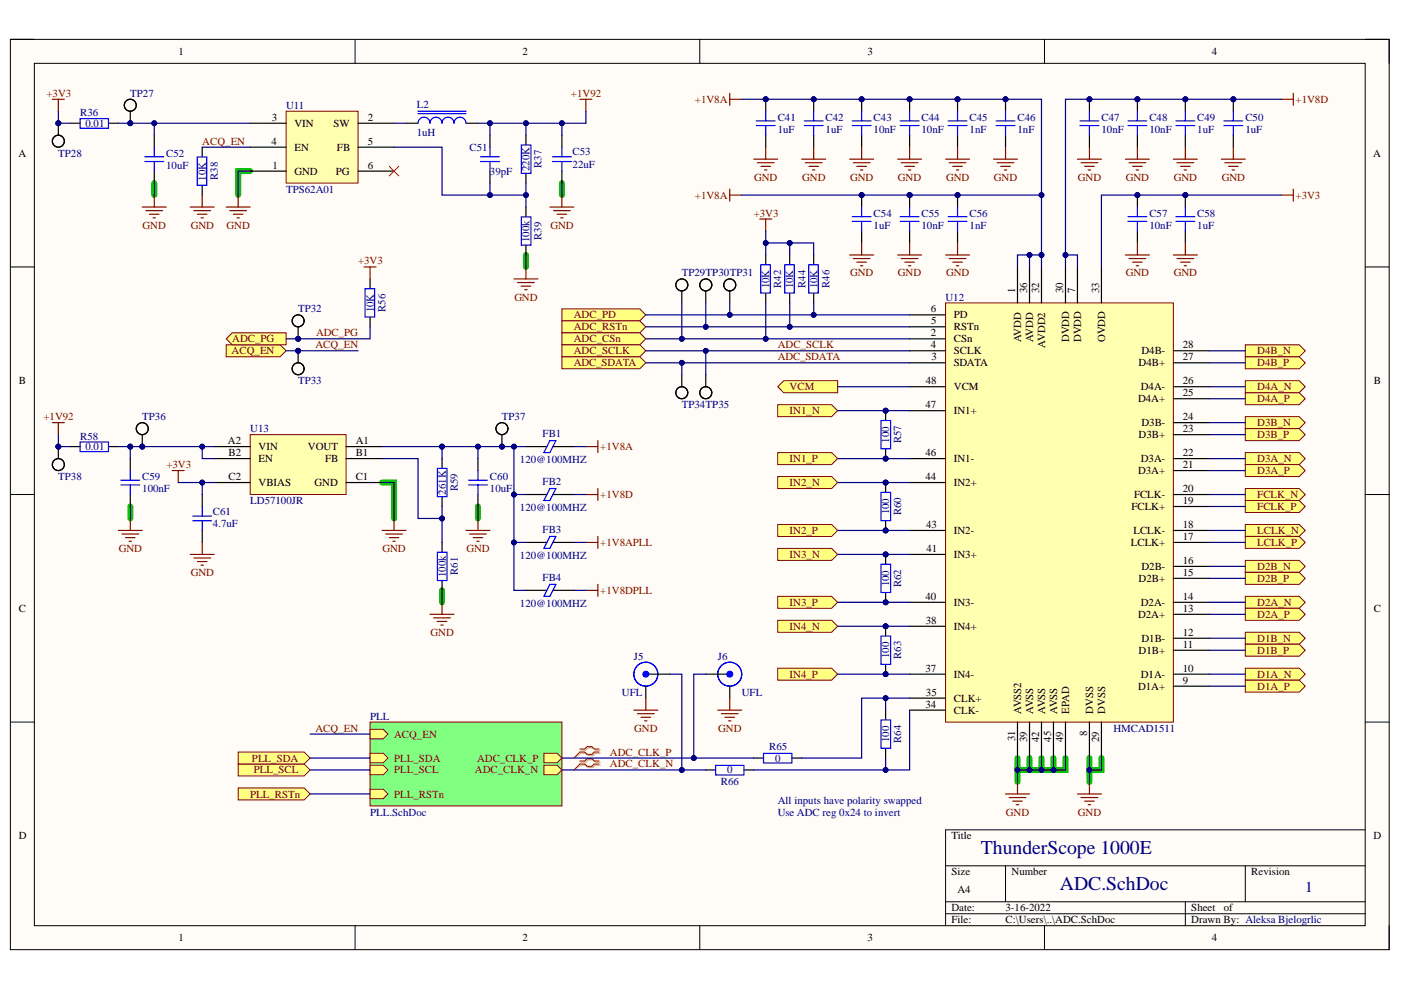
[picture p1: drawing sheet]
<svg xmlns="http://www.w3.org/2000/svg" width="297mm" height="210mm" viewBox="0 0 297 210" stroke-linecap="round" stroke-linejoin="round" font-family="sans-serif">
<defs><g id="words">
<g font-size="4.1" fill="#000080">
<text x="208" y="181.2">ThunderScope 1000E</text>
<text x="224.7" y="188.8">ADC.SchDoc</text>
</g>
<text font-size="3.2" fill="#000080" x="276.7" y="189.2">1</text>
<g font-size="2.3">
<text x="37.9" y="11.7">1</text>
<text x="110.8" y="11.7">2</text>
<text x="184" y="11.7">3</text>
<text x="256.9" y="11.7">4</text>
<text x="57.7" y="25.6">3</text>
<text x="62.4" y="26.9">VIN</text>
<text x="70.7" y="26.9">SW</text>
<text x="78" y="25.6">2</text>
<text x="3.9" y="33.2">A</text>
<text x="57.6" y="30.7">4</text>
<text x="57.8" y="35.8">1</text>
<text x="62.4" y="31.9">EN</text>
<text x="71.4" y="31.9">FB</text>
<text x="78" y="30.7">5</text>
<text x="78" y="35.8">6</text>
<text x="291.1" y="33.2">A</text>
<text x="62.4" y="37.1">GND</text>
<text x="71.2" y="37.1">PG</text>
<text x="215.2" y="62.2" transform="rotate(-90 215.2 62.2)">1</text>
<text x="217.8" y="62.2" transform="rotate(-90 217.8 62.2)">36</text>
<text x="220.3" y="62.2" transform="rotate(-90 220.3 62.2)">32</text>
<text x="225.4" y="62.2" transform="rotate(-90 225.4 62.2)">30</text>
<text x="228" y="62.2" transform="rotate(-90 228 62.2)">7</text>
<text x="233" y="62.2" transform="rotate(-90 233 62.2)">33</text>
<text x="197.4" y="66.3">6</text>
<text x="197.4" y="71.3">2</text>
<text x="197.5" y="68.8">5</text>
<text x="202.2" y="67.5">PD</text>
<text x="202.2" y="70.1">RSTn</text>
<text x="197.4" y="73.9">4</text>
<text x="197.5" y="76.4">3</text>
<text x="202.2" y="72.6">CSn</text>
<text x="202.2" y="75.1">SCLK</text>
<text x="202.2" y="77.7">SDATA</text>
<text x="216.5" y="72.5" transform="rotate(-90 216.5 72.5)">AVDD</text>
<text x="219" y="72.5" transform="rotate(-90 219 72.5)">AVDD</text>
<text x="221.6" y="73.7" transform="rotate(-90 221.6 73.7)">AVDD2</text>
<text x="226.7" y="72.5" transform="rotate(-90 226.7 72.5)">DVDD</text>
<text x="229.2" y="72.5" transform="rotate(-90 229.2 72.5)">DVDD</text>
<text x="234.3" y="72.5" transform="rotate(-90 234.3 72.5)">OVDD</text>
<text x="241.4" y="77.7">D4B+</text>
<text x="242" y="75.1">D4B-</text>
<text x="250.8" y="76.4">27</text>
<text x="250.8" y="73.9">28</text>
<text x="4" y="81.5">B</text>
<text x="196.3" y="81.5">48</text>
<text x="202.2" y="82.7">VCM</text>
<text x="241.9" y="82.7">D4A-</text>
<text x="250.8" y="81.5">26</text>
<text x="291.3" y="81.5">B</text>
<text x="196.2" y="86.5">47</text>
<text x="202.2" y="87.8">IN1+</text>
<text x="241.3" y="85.3">D4A+</text>
<text x="250.8" y="89.1">24</text>
<text x="250.8" y="84">25</text>
<text x="48.3" y="94.2">A2</text>
<text x="54.8" y="95.5">VIN</text>
<text x="65.3" y="95.5">VOUT</text>
<text x="75.4" y="94.2">A1</text>
<text x="241.4" y="92.9">D3B+</text>
<text x="242" y="90.4">D3B-</text>
<text x="250.8" y="91.6">23</text>
<text x="48.4" y="96.7">B2</text>
<text x="48.4" y="101.8">C2</text>
<text x="54.8" y="98">EN</text>
<text x="68.9" y="98">FB</text>
<text x="75.4" y="96.7">B1</text>
<text x="75.4" y="101.8">C1</text>
<text x="196.2" y="96.7">46</text>
<text x="196.2" y="101.8">44</text>
<text x="202.2" y="98">IN1-</text>
<text x="241.3" y="100.5">D3A+</text>
<text x="241.9" y="98">D3A-</text>
<text x="250.8" y="99.3">21</text>
<text x="250.8" y="96.7">22</text>
<text x="54.8" y="103.1">VBIAS</text>
<text x="66.7" y="103.1">GND</text>
<text x="202.2" y="103.1">IN2+</text>
<text x="240.4" y="105.6">FCLK-</text>
<text x="250.8" y="106.9">19</text>
<text x="250.8" y="104.3">20</text>
<text x="196.4" y="111.9">43</text>
<text x="202.2" y="113.2">IN2-</text>
<text x="239.9" y="108.1">FCLK+</text>
<text x="240.3" y="113.2">LCLK-</text>
<text x="250.8" y="111.9">18</text>
<text x="196.4" y="117">41</text>
<text x="202.2" y="118.3">IN3+</text>
<text x="239.8" y="115.8">LCLK+</text>
<text x="250.8" y="119.6">16</text>
<text x="250.8" y="114.5">17</text>
<text x="241.4" y="123.4">D2B+</text>
<text x="242" y="120.8">D2B-</text>
<text x="250.8" y="122.1">15</text>
<text x="4" y="129.7">C</text>
<text x="196.2" y="127.2">40</text>
<text x="202.2" y="128.5">IN3-</text>
<text x="241.3" y="131">D2A+</text>
<text x="241.9" y="128.5">D2A-</text>
<text x="250.8" y="129.7">13</text>
<text x="250.8" y="127.2">14</text>
<text x="291.3" y="129.7">C</text>
<text x="196.3" y="132.3">38</text>
<text x="202.2" y="133.5">IN4+</text>
<text x="242" y="136.1">D1B-</text>
<text x="250.8" y="137.3">11</text>
<text x="250.8" y="134.8">12</text>
<text x="196.2" y="142.4">37</text>
<text x="202.2" y="143.7">IN4-</text>
<text x="241.4" y="138.6">D1B+</text>
<text x="241.9" y="143.7">D1A-</text>
<text x="250.8" y="142.4">10</text>
<text x="196.3" y="147.5">35</text>
<text x="202.2" y="148.8">CLK+</text>
<text x="241.3" y="146.2">D1A+</text>
<text x="250.8" y="145">9</text>
<text x="196.2" y="150">34</text>
<text x="202.2" y="151.3">CLK-</text>
<text x="216.5" y="151.3" transform="rotate(-90 216.5 151.3)">AVSS2</text>
<text x="219" y="151.3" transform="rotate(-90 219 151.3)">AVSS</text>
<text x="221.6" y="151.3" transform="rotate(-90 221.6 151.3)">AVSS</text>
<text x="224.1" y="151.3" transform="rotate(-90 224.1 151.3)">AVSS</text>
<text x="226.7" y="151.3" transform="rotate(-90 226.7 151.3)">EPAD</text>
<text x="231.8" y="151.3" transform="rotate(-90 231.8 151.3)">DVSS</text>
<text x="234.3" y="151.3" transform="rotate(-90 234.3 151.3)">DVSS</text>
<text x="215.2" y="157.1" transform="rotate(-90 215.2 157.1)">31</text>
<text x="217.8" y="157.3" transform="rotate(-90 217.8 157.3)">39</text>
<text x="220.3" y="157.3" transform="rotate(-90 220.3 157.3)">42</text>
<text x="222.8" y="157.3" transform="rotate(-90 222.8 157.3)">45</text>
<text x="225.4" y="157.3" transform="rotate(-90 225.4 157.3)">49</text>
<text x="230.5" y="156.1" transform="rotate(-90 230.5 156.1)">8</text>
<text x="233" y="157.3" transform="rotate(-90 233 157.3)">29</text>
<text x="4" y="178">D</text>
<text x="201.7" y="178">Title</text>
<text x="291.2" y="178">D</text>
<text x="201.7" y="185.6">Size</text>
<text x="214.5" y="185.6">Number</text>
<text x="265.3" y="185.6">Revision</text>
<text x="203" y="189.4">A4</text>
<text x="201.7" y="193.2">Date:</text>
<text x="201.7" y="195.7">File:</text>
<text x="213.2" y="193.2">3-16-2022</text>
<text x="213.2" y="195.7">C:\Users\..\ADC.SchDoc</text>
<text x="252.6" y="193.2">Sheet</text>
<text x="252.6" y="195.7">Drawn By: Aleksa Bjelogrlic</text>
<text x="259.5" y="193.2">of</text>
<text x="37.9" y="199.6">1</text>
<text x="110.8" y="199.6">2</text>
<text x="184" y="199.6">3</text>
<text x="256.9" y="199.6">4</text>
</g>
<g font-size="2.3" fill="#800000">
<text x="9.9" y="20.5">+3V3</text>
<text x="121.1" y="20.5">+1V92</text>
<text x="147.3" y="21.8">+1V8A</text>
<text x="274.7" y="21.8">+1V8D</text>
<text x="42.9" y="30.7">ACQ_EN</text>
<text x="159.9" y="38.3">GND</text>
<text x="170.1" y="38.3">GND</text>
<text x="180.2" y="38.3">GND</text>
<text x="190.4" y="38.3">GND</text>
<text x="200.6" y="38.3">GND</text>
<text x="210.7" y="38.3">GND</text>
<text x="228.5" y="38.3">GND</text>
<text x="238.7" y="38.3">GND</text>
<text x="248.8" y="38.3">GND</text>
<text x="259" y="38.3">GND</text>
<text x="147.3" y="42.1">+1V8A</text>
<text x="159.8" y="45.9">+3V3</text>
<text x="274.7" y="42.1">+3V3</text>
<text x="30.2" y="48.5">GND</text>
<text x="40.4" y="48.5">GND</text>
<text x="48.1" y="48.5">GND</text>
<text x="116.7" y="48.5">GND</text>
<text x="75.9" y="56.1">+3V3</text>
<text x="180.2" y="58.6">GND</text>
<text x="190.4" y="58.6">GND</text>
<text x="200.6" y="58.6">GND</text>
<text x="238.7" y="58.6">GND</text>
<text x="248.8" y="58.6">GND</text>
<text x="109" y="63.7">GND</text>
<text x="67" y="71.3">ADC_PG</text>
<text x="121.7" y="67.5">ADC_PD</text>
<text x="121.7" y="70.1">ADC_RSTn</text>
<text x="49.1" y="75.1">ACQ_EN</text>
<text x="49.2" y="72.6">ADC_PG</text>
<text x="66.9" y="73.9">ACQ_EN</text>
<text x="121.7" y="72.6">ADC_CSn</text>
<text x="121.7" y="75.1">ADC_SCLK</text>
<text x="121.7" y="77.7">ADC_SDATA</text>
<text x="164.9" y="73.9">ADC_SCLK</text>
<text x="164.9" y="76.4">ADC_SDATA</text>
<text x="266.6" y="75.1">D4B_N</text>
<text x="266.6" y="77.7">D4B_P</text>
<text x="167.4" y="82.7">VCM</text>
<text x="266.6" y="82.7">D4A_N</text>
<text x="9.2" y="89.1">+1V92</text>
<text x="167.4" y="87.8">IN1_N</text>
<text x="266.6" y="85.3">D4A_P</text>
<text x="127.3" y="95.5">+1V8A</text>
<text x="266.6" y="90.4">D3B_N</text>
<text x="266.6" y="92.9">D3B_P</text>
<text x="35.3" y="99.3">+3V3</text>
<text x="167.4" y="98">IN1_P</text>
<text x="266.6" y="98">D3A_N</text>
<text x="266.6" y="100.5">D3A_P</text>
<text x="127.3" y="105.6">+1V8D</text>
<text x="167.4" y="103.1">IN2_N</text>
<text x="266.6" y="105.6">FCLK_N</text>
<text x="167.4" y="113.2">IN2_P</text>
<text x="266.6" y="108.1">FCLK_P</text>
<text x="266.6" y="113.2">LCLK_N</text>
<text x="25.2" y="117">GND</text>
<text x="81.1" y="117">GND</text>
<text x="98.9" y="117">GND</text>
<text x="127.3" y="115.8">+1V8APLL</text>
<text x="167.4" y="118.3">IN3_N</text>
<text x="266.6" y="115.8">LCLK_P</text>
<text x="40.4" y="122.1">GND</text>
<text x="127.3" y="125.9">+1V8DPLL</text>
<text x="266.6" y="120.8">D2B_N</text>
<text x="266.6" y="123.4">D2B_P</text>
<text x="167.4" y="128.5">IN3_P</text>
<text x="266.6" y="128.5">D2A_N</text>
<text x="266.6" y="131">D2A_P</text>
<text x="91.3" y="134.8">GND</text>
<text x="167.4" y="133.5">IN4_N</text>
<text x="266.6" y="136.1">D1B_N</text>
<text x="167.4" y="143.7">IN4_P</text>
<text x="266.6" y="138.6">D1B_P</text>
<text x="266.6" y="143.7">D1A_N</text>
<text x="266.6" y="146.2">D1A_P</text>
<text x="66.9" y="155.1">ACQ_EN</text>
<text x="134.5" y="155.1">GND</text>
<text x="152.3" y="155.1">GND</text>
<text x="53.4" y="161.5">PLL_SDA</text>
<text x="83.5" y="161.5">PLL_SDA</text>
<text x="83.5" y="156.4">ACQ_EN</text>
<text x="101.1" y="161.5">ADC_CLK_P</text>
<text x="129.3" y="160.2">ADC_CLK_P</text>
<text x="53.8" y="164">PLL_SCL</text>
<text x="83.5" y="164">PLL_SCL</text>
<text x="100.7" y="164">ADC_CLK_N</text>
<text x="129.3" y="162.7">ADC_CLK_N</text>
<text x="53" y="169.1">PLL_RSTn</text>
<text x="83.5" y="169.1">PLL_RSTn</text>
<text x="213.3" y="172.9">GND</text>
<text x="228.5" y="172.9">GND</text>
</g>
<g font-size="2.3" fill="#000080">
<text x="27.6" y="20.5">TP27</text>
<text x="60.7" y="23.1">U11</text>
<text x="88.4" y="22.8">L2</text>
<text x="17" y="24.6">R36</text>
<text x="18.1" y="26.9">0.01</text>
<text x="88.4" y="28.9">1uH</text>
<text x="164.9" y="25.6">C41</text>
<text x="164.9" y="28.1">1uF</text>
<text x="175" y="25.6">C42</text>
<text x="175" y="28.1">1uF</text>
<text x="185.2" y="25.6">C43</text>
<text x="185.2" y="28.1">10nF</text>
<text x="195.4" y="25.6">C44</text>
<text x="195.4" y="28.1">10nF</text>
<text x="205.6" y="25.6">C45</text>
<text x="205.6" y="28.1">1nF</text>
<text x="215.7" y="25.6">C46</text>
<text x="215.7" y="28.1">1nF</text>
<text x="233.5" y="25.6">C47</text>
<text x="233.5" y="28.1">10nF</text>
<text x="243.7" y="25.6">C48</text>
<text x="243.7" y="28.1">10nF</text>
<text x="253.8" y="25.6">C49</text>
<text x="253.8" y="28.1">1uF</text>
<text x="264" y="25.6">C50</text>
<text x="264" y="28.1">1uF</text>
<text x="12.4" y="33.2">TP28</text>
<text x="35.2" y="33.2">C52</text>
<text x="35.2" y="35.8">10uF</text>
<text x="99.6" y="31.9">C51</text>
<text x="114.8" y="35.6" transform="rotate(-90 114.8 35.6)">R37</text>
<text x="121.4" y="33">C53</text>
<text x="121.4" y="35.5">22uF</text>
<text x="43.7" y="38.3" transform="rotate(-90 43.7 38.3)">10K</text>
<text x="46.2" y="38.1" transform="rotate(-90 46.2 38.1)">R38</text>
<text x="60.7" y="40.9">TPS62A01</text>
<text x="103.9" y="37.1">39pF</text>
<text x="112.3" y="36.3" transform="rotate(-90 112.3 36.3)">220K</text>
<text x="185.2" y="45.9">C54</text>
<text x="195.4" y="45.9">C55</text>
<text x="205.6" y="45.9">C56</text>
<text x="243.7" y="45.9">C57</text>
<text x="253.8" y="45.9">C58</text>
<text x="112.3" y="51.3" transform="rotate(-90 112.3 51.3)">100k</text>
<text x="114.8" y="50.8" transform="rotate(-90 114.8 50.8)">R39</text>
<text x="185.2" y="48.5">1uF</text>
<text x="195.4" y="48.5">10nF</text>
<text x="205.6" y="48.5">1nF</text>
<text x="243.7" y="48.5">10nF</text>
<text x="253.8" y="48.5">1uF</text>
<text x="144.5" y="58.6">TP29TP30TP31</text>
<text x="163.1" y="61.1" transform="rotate(-90 163.1 61.1)">10K</text>
<text x="165.6" y="61" transform="rotate(-90 165.6 61)">R42</text>
<text x="168.2" y="61.1" transform="rotate(-90 168.2 61.1)">10K</text>
<text x="170.8" y="61" transform="rotate(-90 170.8 61)">R44</text>
<text x="173.3" y="61.1" transform="rotate(-90 173.3 61.1)">10K</text>
<text x="175.8" y="61" transform="rotate(-90 175.8 61)">R46</text>
<text x="200.5" y="63.7">U12</text>
<text x="63.2" y="66.3">TP32</text>
<text x="79.2" y="66.2" transform="rotate(-90 79.2 66.2)">10K</text>
<text x="81.8" y="66.1" transform="rotate(-90 81.8 66.1)">R56</text>
<text x="63.2" y="81.5">TP33</text>
<text x="30.2" y="89.1">TP36</text>
<text x="106.4" y="89.1">TP37</text>
<text x="144.5" y="86.5">TP34TP35</text>
<text x="17" y="93.2">R58</text>
<text x="18.1" y="95.5">0.01</text>
<text x="53" y="91.6">U13</text>
<text x="115.1" y="92.7">FB1</text>
<text x="188.5" y="93.8" transform="rotate(-90 188.5 93.8)">100</text>
<text x="191.1" y="94" transform="rotate(-90 191.1 94)">R57</text>
<text x="12.4" y="101.8">TP38</text>
<text x="30.2" y="101.8">C59</text>
<text x="103.9" y="101.8">C60</text>
<text x="110.2" y="98.2">120@100MHZ</text>
<text x="30.2" y="104.3">100nF</text>
<text x="53" y="106.9">LD57100JR</text>
<text x="94.5" y="104.9" transform="rotate(-90 94.5 104.9)">261K</text>
<text x="97" y="104.2" transform="rotate(-90 97 104.2)">R59</text>
<text x="103.9" y="104.3">10uF</text>
<text x="115.1" y="102.8">FB2</text>
<text x="45.1" y="109.1">C61</text>
<text x="45.1" y="111.7">4.7uF</text>
<text x="110.2" y="108.4">120@100MHZ</text>
<text x="115.1" y="112.9">FB3</text>
<text x="188.5" y="109.1" transform="rotate(-90 188.5 109.1)">100</text>
<text x="191.1" y="109.3" transform="rotate(-90 191.1 109.3)">R60</text>
<text x="110.2" y="118.6">120@100MHZ</text>
<text x="94.5" y="122.4" transform="rotate(-90 94.5 122.4)">100k</text>
<text x="97" y="121.9" transform="rotate(-90 97 121.9)">R61</text>
<text x="115.1" y="123.1">FB4</text>
<text x="188.5" y="124.3" transform="rotate(-90 188.5 124.3)">100</text>
<text x="191.1" y="124.5" transform="rotate(-90 191.1 124.5)">R62</text>
<text x="110.2" y="128.7">120@100MHZ</text>
<text x="134.4" y="139.9">J5</text>
<text x="152.2" y="139.9">J6</text>
<text x="188.5" y="139.5" transform="rotate(-90 188.5 139.5)">100</text>
<text x="191.1" y="139.7" transform="rotate(-90 191.1 139.7)">R63</text>
<text x="131.8" y="147.5">UFL</text>
<text x="157.3" y="147.5">UFL</text>
<text x="78.5" y="152.6">PLL</text>
<text x="236.1" y="155.1">HMCAD1511</text>
<text x="163.1" y="158.9">R65</text>
<text x="164.3" y="161.5">0</text>
<text x="188.5" y="157.3" transform="rotate(-90 188.5 157.3)">100</text>
<text x="191.1" y="157.5" transform="rotate(-90 191.1 157.5)">R64</text>
<text x="152.8" y="166.5">R66</text>
<text x="154.2" y="164">0</text>
<text x="78.5" y="172.9">PLL.SchDoc</text>
<text x="164.9" y="170.4">All inputs have polarity swapped</text>
<text x="164.9" y="172.9">Use ADC reg 0x24 to invert</text>
</g>
</g></defs>
<path d="M2.2 8.3h292.3v193.1h-292.3z" fill-rule="evenodd" fill="#fffcf8"/>
<path d="M2.2 8.3h292.3v193.1h-292.3z" fill="none" stroke="#000" stroke-width=".21"/>
<path d="M7.3 13.4h282.1v182.9h-282.1z" fill-rule="evenodd" fill="#fffcf8"/>
<g fill="none" stroke="#000" stroke-width=".21">
<path d="M2.2 8.3h5.1M7.3 13.4h282.1v182.9h-282.1zM75.3 8.3v5.1M148.4 8.3v5.1M221.5 8.3v5.1M289.4 8.3h5.1v5.1M2.2 56.6h5.1M289.4 56.6h5.1M2.2 104.8h5.1M289.4 104.9h5.1M2.2 153.1h5.1M289.4 153.1h5.1"/>
<path d="M289.4 176h-88.9v20.3M75.3 196.3v5.1M148.4 196.3v5.1M200.5 183.6h88.9M200.5 191.2h88.9M200.5 193.7h88.9M213.2 183.6v7.6M221.5 196.3v5.1M251.3 191.2v5.1M264 183.6v7.6M294.5 196.3v5.1"/>
</g>
<g fill="none" stroke="#00be00" stroke-width="1.3">
<path d="M32.7 38.8v2.6M53 36.3h-2.5v5.1M119.1 38.8v2.6M111.5 54.1v2.5M27.6 107.4v2.5M81 102.3h2.5v7.6M101.3 107.4v2.5M93.7 125.2v2.5M215.7 160.7v2.6M218.3 160.7v2.6M220.8 163.3h-5.1v2.5M220.8 160.7v2.6"/>
<path d="M223.4 160.7v2.6M225.9 160.7v2.6h-5.1M231 160.7v2.6h2.5v-2.6M231 163.3v2.5"/>
</g>
<path d="M93.7 97.2v2M101.3 97.2v2.6M93.7 105.4v2M93.7 115v2M101.3 104.8v2.6M93.7 123.2v2" fill="none" stroke="#000" stroke-width=".25"/>
<path d="M92.7 99.3h2.1v6h-2.1zM101.3 99.8v2M92.7 117.1h2.1v6h-2.1zM99.3 102.8h4M99.3 101.8h4M101.3 102.8v2" fill="none" stroke="#00f" stroke-width=".25"/>
<path d="M98.8 112.5h5.1M99.6 113.2h3.5M100.3 114h2.1M101.1 114.8h.5M101.3 109.9v2.6M91.2 130.2h5.1M91.9 131h3.6M92.7 131.8h2M93.5 132.5h.5M93.7 127.7v2.5" fill="none" stroke="#800000" stroke-width=".25"/>
<circle cx="241.2" cy="41.4" r=".51" fill="#000080"/>
<circle cx="241.2" cy="41.4" r=".51" fill="none" stroke="#000080" stroke-width=".21"/>
<path d="M241.2 41.4v2.5M241.2 49v2.5" fill="none" stroke="#000" stroke-width=".25"/>
<circle cx="241.2" cy="41.4" r=".51" fill="#000080"/>
<circle cx="241.2" cy="41.4" r=".51" fill="none" stroke="#000080" stroke-width=".21"/>
<path d="M239.2 46.9h3.9M239.2 45.9h3.9M241.2 43.9v2M241.2 46.9v2.1" fill="none" stroke="#00f" stroke-width=".25"/>
<circle cx="251.3" cy="41.4" r=".51" fill="#000080"/>
<circle cx="251.3" cy="41.4" r=".51" fill="none" stroke="#000080" stroke-width=".21"/>
<path d="M251.3 41.4v2.5M251.3 49v2.5" fill="none" stroke="#000" stroke-width=".25"/>
<circle cx="251.3" cy="41.4" r=".51" fill="#000080"/>
<circle cx="251.3" cy="41.4" r=".51" fill="none" stroke="#000080" stroke-width=".21"/>
<path d="M249.3 46.9h4M249.3 45.9h4M251.3 43.9v2M251.3 46.9v2.1" fill="none" stroke="#00f" stroke-width=".25"/>
<path d="M238.6 54.1h5.1M239.4 54.8h3.5M240.1 55.6h2.1M240.9 56.4h.5M241.2 51.5v2.6M248.8 54.1h5.1M249.5 54.8h3.6M250.3 55.6h2M251.1 56.4h.5M251.3 51.5v2.6M271.6 41.4h2.6M274.2 40.1v2.5" fill="none" stroke="#800000" stroke-width=".25"/>
<circle cx="231" cy="21" r=".51" fill="#000080"/>
<circle cx="231" cy="21" r=".51" fill="none" stroke="#000080" stroke-width=".21"/>
<path d="M231 21v2.6M231 28.7v2.5" fill="none" stroke="#000" stroke-width=".25"/>
<circle cx="231" cy="21" r=".51" fill="#000080"/>
<circle cx="231" cy="21" r=".51" fill="none" stroke="#000080" stroke-width=".21"/>
<path d="M229 26.6h4M229 25.6h4M231 23.6v2M231 26.6v2.1" fill="none" stroke="#00f" stroke-width=".25"/>
<circle cx="261.5" cy="21" r=".51" fill="#000080"/>
<circle cx="261.5" cy="21" r=".51" fill="none" stroke="#000080" stroke-width=".21"/>
<path d="M261.5 21v2.6M261.5 28.7v2.5" fill="none" stroke="#000" stroke-width=".25"/>
<circle cx="261.5" cy="21" r=".51" fill="#000080"/>
<circle cx="261.5" cy="21" r=".51" fill="none" stroke="#000080" stroke-width=".21"/>
<path d="M259.5 26.6h4M259.5 25.6h4M261.5 23.6v2M261.5 26.6v2.1" fill="none" stroke="#00f" stroke-width=".25"/>
<path d="M228.4 33.7h5.1M229.2 34.5h3.6M230 35.3h2M230.7 36h.5M231 31.2v2.5M258.9 33.7h5.1M259.7 34.5h3.6M260.5 35.3h2M261.2 36h.5M261.5 31.2v2.5" fill="none" stroke="#800000" stroke-width=".25"/>
<circle cx="241.2" cy="21" r=".51" fill="#000080"/>
<circle cx="241.2" cy="21" r=".51" fill="none" stroke="#000080" stroke-width=".21"/>
<path d="M241.2 21v2.6M241.2 28.7v2.5" fill="none" stroke="#000" stroke-width=".25"/>
<circle cx="241.2" cy="21" r=".51" fill="#000080"/>
<circle cx="241.2" cy="21" r=".51" fill="none" stroke="#000080" stroke-width=".21"/>
<path d="M239.2 26.6h3.9M239.2 25.6h3.9M241.2 23.6v2M241.2 26.6v2.1" fill="none" stroke="#00f" stroke-width=".25"/>
<circle cx="251.3" cy="21" r=".51" fill="#000080"/>
<circle cx="251.3" cy="21" r=".51" fill="none" stroke="#000080" stroke-width=".21"/>
<path d="M251.3 21v2.6M251.3 28.7v2.5" fill="none" stroke="#000" stroke-width=".25"/>
<circle cx="251.3" cy="21" r=".51" fill="#000080"/>
<circle cx="251.3" cy="21" r=".51" fill="none" stroke="#000080" stroke-width=".21"/>
<path d="M249.3 26.6h4M249.3 25.6h4M251.3 23.6v2M251.3 26.6v2.1" fill="none" stroke="#00f" stroke-width=".25"/>
<path d="M274.2 19.8v2.5M238.6 33.7h5.1M239.4 34.5h3.5M240.1 35.3h2.1M240.9 36h.5M241.2 31.2v2.5M248.8 33.7h5.1M249.5 34.5h3.6M250.3 35.3h2M251.1 36h.5M251.3 31.2v2.5M271.6 21h2.6" fill="none" stroke="#800000" stroke-width=".25"/>
<circle cx="192.9" cy="21" r=".51" fill="#000080"/>
<circle cx="192.9" cy="21" r=".51" fill="none" stroke="#000080" stroke-width=".21"/>
<path d="M192.9 21v2.6M192.9 28.7v2.5" fill="none" stroke="#000" stroke-width=".25"/>
<circle cx="192.9" cy="21" r=".51" fill="#000080"/>
<circle cx="192.9" cy="21" r=".51" fill="none" stroke="#000080" stroke-width=".21"/>
<path d="M190.8 26.6h4.1M190.8 25.6h4.1M192.9 23.6v2M192.9 26.6v2.1" fill="none" stroke="#00f" stroke-width=".25"/>
<circle cx="162.3" cy="21" r=".51" fill="#000080"/>
<circle cx="162.3" cy="21" r=".51" fill="none" stroke="#000080" stroke-width=".21"/>
<path d="M162.3 21v2.6M162.3 28.7v2.5" fill="none" stroke="#000" stroke-width=".25"/>
<circle cx="162.3" cy="21" r=".51" fill="#000080"/>
<circle cx="162.3" cy="21" r=".51" fill="none" stroke="#000080" stroke-width=".21"/>
<path d="M160.3 26.6h4M160.3 25.6h4M162.3 23.6v2M162.3 26.6v2.1" fill="none" stroke="#00f" stroke-width=".25"/>
<path d="M159.8 33.7h5.1M160.6 34.5h3.5M161.3 35.3h2.1M162.1 36h.5M162.3 31.2v2.5M190.3 33.7h5.1M191.1 34.5h3.5M191.8 35.3h2.1M192.6 36h.5M192.9 31.2v2.5" fill="none" stroke="#800000" stroke-width=".25"/>
<circle cx="182.7" cy="21" r=".51" fill="#000080"/>
<circle cx="182.7" cy="21" r=".51" fill="none" stroke="#000080" stroke-width=".21"/>
<path d="M182.7 21v2.6M182.7 28.7v2.5" fill="none" stroke="#000" stroke-width=".25"/>
<circle cx="182.7" cy="21" r=".51" fill="#000080"/>
<circle cx="182.7" cy="21" r=".51" fill="none" stroke="#000080" stroke-width=".21"/>
<path d="M180.7 26.6h4M180.7 25.6h4M182.7 23.6v2M182.7 26.6v2.1" fill="none" stroke="#00f" stroke-width=".25"/>
<circle cx="172.5" cy="21" r=".51" fill="#000080"/>
<circle cx="172.5" cy="21" r=".51" fill="none" stroke="#000080" stroke-width=".21"/>
<path d="M172.5 21v2.6M172.5 28.7v2.5" fill="none" stroke="#000" stroke-width=".25"/>
<circle cx="172.5" cy="21" r=".51" fill="#000080"/>
<circle cx="172.5" cy="21" r=".51" fill="none" stroke="#000080" stroke-width=".21"/>
<path d="M170.5 26.6h4M170.5 25.6h4M172.5 23.6v2M172.5 26.6v2.1" fill="none" stroke="#00f" stroke-width=".25"/>
<path d="M170 33.7h5.1M170.7 34.5h3.6M171.5 35.3h2M172.3 36h.5M172.5 31.2v2.5M180.1 33.7h5.1M180.9 34.5h3.6M181.7 35.3h2M182.4 36h.5M182.7 31.2v2.5" fill="none" stroke="#800000" stroke-width=".25"/>
<circle cx="203" cy="21" r=".51" fill="#000080"/>
<circle cx="203" cy="21" r=".51" fill="none" stroke="#000080" stroke-width=".21"/>
<path d="M203 21v2.6M203 28.7v2.5" fill="none" stroke="#000" stroke-width=".25"/>
<circle cx="203" cy="21" r=".51" fill="#000080"/>
<circle cx="203" cy="21" r=".51" fill="none" stroke="#000080" stroke-width=".21"/>
<path d="M201 26.6h4M201 25.6h4M203 23.6v2M203 26.6v2.1" fill="none" stroke="#00f" stroke-width=".25"/>
<path d="M200.5 33.7h5.1M201.2 34.5h3.6M202 35.3h2M202.8 36h.5M203 31.2v2.5" fill="none" stroke="#800000" stroke-width=".25"/>
<circle cx="213.2" cy="21" r=".51" fill="#000080"/>
<circle cx="213.2" cy="21" r=".51" fill="none" stroke="#000080" stroke-width=".21"/>
<path d="M213.2 21v2.6M213.2 28.7v2.5" fill="none" stroke="#000" stroke-width=".25"/>
<circle cx="213.2" cy="21" r=".51" fill="#000080"/>
<circle cx="213.2" cy="21" r=".51" fill="none" stroke="#000080" stroke-width=".21"/>
<path d="M211.2 26.6h4M211.2 25.6h4M213.2 23.6v2M213.2 26.6v2.1" fill="none" stroke="#00f" stroke-width=".25"/>
<path d="M210.6 33.7h5.1M211.4 34.5h3.6M212.2 35.3h2M212.9 36h.5M213.2 31.2v2.5" fill="none" stroke="#800000" stroke-width=".25"/>
<circle cx="182.7" cy="41.4" r=".51" fill="#000080"/>
<circle cx="182.7" cy="41.4" r=".51" fill="none" stroke="#000080" stroke-width=".21"/>
<path d="M182.7 41.4v2.5M182.7 49v2.5" fill="none" stroke="#000" stroke-width=".25"/>
<circle cx="182.7" cy="41.4" r=".51" fill="#000080"/>
<circle cx="182.7" cy="41.4" r=".51" fill="none" stroke="#000080" stroke-width=".21"/>
<path d="M180.7 46.9h4M180.7 45.9h4M182.7 43.9v2M182.7 46.9v2.1" fill="none" stroke="#00f" stroke-width=".25"/>
<path d="M180.1 54.1h5.1M180.9 54.8h3.6M181.7 55.6h2M182.4 56.4h.5M182.7 51.5v2.6" fill="none" stroke="#800000" stroke-width=".25"/>
<circle cx="192.9" cy="41.4" r=".51" fill="#000080"/>
<circle cx="192.9" cy="41.4" r=".51" fill="none" stroke="#000080" stroke-width=".21"/>
<path d="M192.9 41.4v2.5M192.9 49v2.5" fill="none" stroke="#000" stroke-width=".25"/>
<circle cx="192.9" cy="41.4" r=".51" fill="#000080"/>
<circle cx="192.9" cy="41.4" r=".51" fill="none" stroke="#000080" stroke-width=".21"/>
<path d="M190.8 46.9h4.1M190.8 45.9h4.1M192.9 43.9v2M192.9 46.9v2.1" fill="none" stroke="#00f" stroke-width=".25"/>
<path d="M190.3 54.1h5.1M191.1 54.8h3.5M191.8 55.6h2.1M192.6 56.4h.5M192.9 51.5v2.6" fill="none" stroke="#800000" stroke-width=".25"/>
<circle cx="203" cy="41.4" r=".51" fill="#000080"/>
<circle cx="203" cy="41.4" r=".51" fill="none" stroke="#000080" stroke-width=".21"/>
<path d="M203 41.4v2.5M203 49v2.5" fill="none" stroke="#000" stroke-width=".25"/>
<circle cx="203" cy="41.4" r=".51" fill="#000080"/>
<circle cx="203" cy="41.4" r=".51" fill="none" stroke="#000080" stroke-width=".21"/>
<path d="M161.3 56.1h2v6h-2zM166.4 56.1h2v6h-2zM171.5 56.1h2v6h-2zM201 46.9h4M201 45.9h4M203 43.9v2M203 46.9v2.1" fill="none" stroke="#00f" stroke-width=".25"/>
<path d="M200.5 54.1h5.1M201.2 54.8h3.6M202 55.6h2M202.8 56.4h.5M203 51.5v2.6" fill="none" stroke="#800000" stroke-width=".25"/>
<path d="M162.3 54.1v2M167.4 54.1v2M172.5 54.1v2M162.3 62.2v2M167.4 62.2v2M172.5 62.2v2" fill="none" stroke="#000" stroke-width=".25"/>
<path d="M200.5 64.2h48.3v88.9h-48.3z" fill-rule="evenodd" fill="#ffffb0"/>
<path d="M200.5 64.2h48.3v88.9h-48.3z" fill="none" stroke="#800000" stroke-width=".21"/>
<g fill="none" stroke="#000" stroke-width=".25">
<path d="M215.7 56.6v7.6M218.3 56.6v7.6M220.8 56.6v7.6M225.9 56.6v7.6M228.4 56.6v7.6M233.5 56.6v7.6M192.9 66.8h7.6M192.9 69.3h7.6M192.9 71.8h7.6M192.9 74.4h7.6M192.9 76.9h7.6M248.8 74.4h7.6"/>
<path d="M248.8 76.9h7.6M192.9 82h7.6M192.9 87.1h7.6M192.9 97.2h7.6M248.8 82h7.6M248.8 97.2h7.6M248.8 99.8h7.6M248.8 92.2h7.6M248.8 89.6h7.6M248.8 84.5h7.6M192.9 102.3h7.6M192.9 112.5h7.6"/>
<path d="M192.9 117.6h7.6M248.8 112.5h7.6M248.8 115h7.6M248.8 107.4h7.6M248.8 104.9h7.6M192.9 127.7h7.6M192.9 132.8h7.6M248.8 127.7h7.6M248.8 137.9h7.6M248.8 135.3h7.6M248.8 130.3h7.6M248.8 122.6h7.6"/>
<path d="M248.8 120.1h7.6M192.9 142.9h7.6M192.9 148h7.6M192.9 150.6h7.6M215.7 153.1v7.6M218.3 153.1v7.6M220.8 153.1v7.6M223.4 153.1v7.6M225.9 153.1v7.6M231 153.1v7.6M233.5 153.1v7.6M248.8 142.9h7.6"/>
<path d="M248.8 145.5h7.6"/>
</g>
<g fill="none" stroke="#800000" stroke-width=".25">
<path d="M154.7 19.8v2.5M154.7 21h2.6M154.7 40.1v2.5M154.7 41.4h2.6M161.1 46.4h2.5M162.3 46.4v2.6M213.2 168.3h5.1M214 169.1h3.5M214.7 169.9h2M215.5 170.6h.5M215.7 165.8v2.5M228.4 168.3h5.1"/>
<path d="M229.2 169.1h3.6M230 169.9h2M230.7 170.6h.5M231 165.8v2.5"/>
</g>
<circle cx="187.8" cy="87.1" r=".51" fill="#000080"/>
<circle cx="187.8" cy="87.1" r=".51" fill="none" stroke="#000080" stroke-width=".21"/>
<circle cx="187.8" cy="97.2" r=".51" fill="#000080"/>
<circle cx="187.8" cy="97.2" r=".51" fill="none" stroke="#000080" stroke-width=".21"/>
<path d="M187.8 87.1v2" fill="none" stroke="#000" stroke-width=".25"/>
<circle cx="187.8" cy="87.1" r=".51" fill="#000080"/>
<circle cx="187.8" cy="87.1" r=".51" fill="none" stroke="#000080" stroke-width=".21"/>
<path d="M187.8 95.2v2" fill="none" stroke="#000" stroke-width=".25"/>
<circle cx="187.8" cy="97.2" r=".51" fill="#000080"/>
<circle cx="187.8" cy="97.2" r=".51" fill="none" stroke="#000080" stroke-width=".21"/>
<path d="M186.8 89.2h2v6h-2z" fill="none" stroke="#00f" stroke-width=".25"/>
<circle cx="187.8" cy="102.3" r=".51" fill="#000080"/>
<circle cx="187.8" cy="102.3" r=".51" fill="none" stroke="#000080" stroke-width=".21"/>
<circle cx="187.8" cy="112.5" r=".51" fill="#000080"/>
<circle cx="187.8" cy="112.5" r=".51" fill="none" stroke="#000080" stroke-width=".21"/>
<path d="M187.8 102.3v2" fill="none" stroke="#000" stroke-width=".25"/>
<circle cx="187.8" cy="102.3" r=".51" fill="#000080"/>
<circle cx="187.8" cy="102.3" r=".51" fill="none" stroke="#000080" stroke-width=".21"/>
<path d="M187.8 110.5v2" fill="none" stroke="#000" stroke-width=".25"/>
<circle cx="187.8" cy="112.5" r=".51" fill="#000080"/>
<circle cx="187.8" cy="112.5" r=".51" fill="none" stroke="#000080" stroke-width=".21"/>
<path d="M186.8 104.4h2v6h-2z" fill="none" stroke="#00f" stroke-width=".25"/>
<circle cx="187.8" cy="117.6" r=".51" fill="#000080"/>
<circle cx="187.8" cy="117.6" r=".51" fill="none" stroke="#000080" stroke-width=".21"/>
<circle cx="187.8" cy="127.7" r=".51" fill="#000080"/>
<circle cx="187.8" cy="127.7" r=".51" fill="none" stroke="#000080" stroke-width=".21"/>
<path d="M187.8 117.6v1.9" fill="none" stroke="#000" stroke-width=".25"/>
<circle cx="187.8" cy="117.6" r=".51" fill="#000080"/>
<circle cx="187.8" cy="117.6" r=".51" fill="none" stroke="#000080" stroke-width=".21"/>
<path d="M187.8 125.7v2" fill="none" stroke="#000" stroke-width=".25"/>
<circle cx="187.8" cy="127.7" r=".51" fill="#000080"/>
<circle cx="187.8" cy="127.7" r=".51" fill="none" stroke="#000080" stroke-width=".21"/>
<path d="M186.8 119.6h2v6h-2z" fill="none" stroke="#00f" stroke-width=".25"/>
<circle cx="187.8" cy="132.8" r=".51" fill="#000080"/>
<circle cx="187.8" cy="132.8" r=".51" fill="none" stroke="#000080" stroke-width=".21"/>
<circle cx="187.8" cy="142.9" r=".51" fill="#000080"/>
<circle cx="187.8" cy="142.9" r=".51" fill="none" stroke="#000080" stroke-width=".21"/>
<path d="M187.8 132.8v2" fill="none" stroke="#000" stroke-width=".25"/>
<circle cx="187.8" cy="132.8" r=".51" fill="#000080"/>
<circle cx="187.8" cy="132.8" r=".51" fill="none" stroke="#000080" stroke-width=".21"/>
<path d="M187.8 140.9v2" fill="none" stroke="#000" stroke-width=".25"/>
<circle cx="187.8" cy="142.9" r=".51" fill="#000080"/>
<circle cx="187.8" cy="142.9" r=".51" fill="none" stroke="#000080" stroke-width=".21"/>
<path d="M186.8 134.9h2v6h-2z" fill="none" stroke="#00f" stroke-width=".25"/>
<path d="M264 73.1h11.5l1.2 1.3-1.2 1.2h-11.5z" fill-rule="evenodd" fill="#ffff80"/>
<path d="M264 73.1h11.5l1.2 1.3-1.2 1.2h-11.5z" fill="none" stroke="#800000" stroke-width=".21"/>
<path d="M264 75.6h11.5l1.2 1.3-1.2 1.3h-11.5z" fill-rule="evenodd" fill="#ffff80"/>
<path d="M264 75.6h11.5l1.2 1.3-1.2 1.3h-11.5z" fill="none" stroke="#800000" stroke-width=".21"/>
<path d="M264 80.7h11.5l1.2 1.3-1.2 1.3h-11.5z" fill-rule="evenodd" fill="#ffff80"/>
<path d="M264 80.7h11.5l1.2 1.3-1.2 1.3h-11.5z" fill="none" stroke="#800000" stroke-width=".21"/>
<path d="M264 83.3h11.5l1.2 1.2-1.2 1.3h-11.5z" fill-rule="evenodd" fill="#ffff80"/>
<path d="M264 83.3h11.5l1.2 1.2-1.2 1.3h-11.5z" fill="none" stroke="#800000" stroke-width=".21"/>
<path d="M264 88.3h11.5l1.2 1.3-1.2 1.3h-11.5z" fill-rule="evenodd" fill="#ffff80"/>
<path d="M264 88.3h11.5l1.2 1.3-1.2 1.3h-11.5z" fill="none" stroke="#800000" stroke-width=".21"/>
<path d="M264 90.9h11.5l1.2 1.3-1.2 1.2h-11.5z" fill-rule="evenodd" fill="#ffff80"/>
<path d="M264 90.9h11.5l1.2 1.3-1.2 1.2h-11.5z" fill="none" stroke="#800000" stroke-width=".21"/>
<path d="M264 96h11.5l1.2 1.2-1.2 1.3h-11.5z" fill-rule="evenodd" fill="#ffff80"/>
<path d="M264 96h11.5l1.2 1.2-1.2 1.3h-11.5z" fill="none" stroke="#800000" stroke-width=".21"/>
<path d="M264 98.5h11.5l1.2 1.3-1.2 1.2h-11.5z" fill-rule="evenodd" fill="#ffff80"/>
<path d="M264 98.5h11.5l1.2 1.3-1.2 1.2h-11.5z" fill="none" stroke="#800000" stroke-width=".21"/>
<path d="M264 103.6h11.5l1.2 1.3-1.2 1.2h-11.5z" fill-rule="evenodd" fill="#ffff80"/>
<path d="M264 103.6h11.5l1.2 1.3-1.2 1.2h-11.5z" fill="none" stroke="#800000" stroke-width=".21"/>
<path d="M264 106.1h11.5l1.2 1.3-1.2 1.3h-11.5z" fill-rule="evenodd" fill="#ffff80"/>
<path d="M264 106.1h11.5l1.2 1.3-1.2 1.3h-11.5z" fill="none" stroke="#800000" stroke-width=".21"/>
<path d="M264 111.2h11.5l1.2 1.3-1.2 1.2h-11.5z" fill-rule="evenodd" fill="#ffff80"/>
<path d="M264 111.2h11.5l1.2 1.3-1.2 1.2h-11.5z" fill="none" stroke="#800000" stroke-width=".21"/>
<path d="M264 113.7h11.5l1.2 1.3-1.2 1.3h-11.5z" fill-rule="evenodd" fill="#ffff80"/>
<path d="M264 113.7h11.5l1.2 1.3-1.2 1.3h-11.5z" fill="none" stroke="#800000" stroke-width=".21"/>
<path d="M264 118.8h11.5l1.2 1.3-1.2 1.3h-11.5z" fill-rule="evenodd" fill="#ffff80"/>
<path d="M264 118.8h11.5l1.2 1.3-1.2 1.3h-11.5z" fill="none" stroke="#800000" stroke-width=".21"/>
<path d="M264 121.4h11.5l1.2 1.2-1.2 1.3h-11.5z" fill-rule="evenodd" fill="#ffff80"/>
<path d="M264 121.4h11.5l1.2 1.2-1.2 1.3h-11.5z" fill="none" stroke="#800000" stroke-width=".21"/>
<path d="M264 126.4h11.5l1.2 1.3-1.2 1.3h-11.5z" fill-rule="evenodd" fill="#ffff80"/>
<path d="M264 126.4h11.5l1.2 1.3-1.2 1.3h-11.5z" fill="none" stroke="#800000" stroke-width=".21"/>
<path d="M264 129h11.5l1.2 1.3-1.2 1.2h-11.5z" fill-rule="evenodd" fill="#ffff80"/>
<path d="M264 129h11.5l1.2 1.3-1.2 1.2h-11.5z" fill="none" stroke="#800000" stroke-width=".21"/>
<path d="M264 134.1h11.5l1.2 1.2-1.2 1.3h-11.5z" fill-rule="evenodd" fill="#ffff80"/>
<path d="M264 134.1h11.5l1.2 1.2-1.2 1.3h-11.5z" fill="none" stroke="#800000" stroke-width=".21"/>
<path d="M264 136.6h11.5l1.2 1.3-1.2 1.2h-11.5z" fill-rule="evenodd" fill="#ffff80"/>
<path d="M264 136.6h11.5l1.2 1.3-1.2 1.2h-11.5z" fill="none" stroke="#800000" stroke-width=".21"/>
<path d="M264 141.7h11.5l1.2 1.2-1.2 1.3h-11.5z" fill-rule="evenodd" fill="#ffff80"/>
<path d="M264 141.7h11.5l1.2 1.2-1.2 1.3h-11.5z" fill="none" stroke="#800000" stroke-width=".21"/>
<path d="M264 144.2h11.5l1.2 1.3-1.2 1.3h-11.5z" fill-rule="evenodd" fill="#ffff80"/>
<path d="M264 144.2h11.5l1.2 1.3-1.2 1.3h-11.5z" fill="none" stroke="#800000" stroke-width=".21"/>
<path d="M119.1 65.5h16.6l1.2 1.3-1.2 1.2h-16.6z" fill-rule="evenodd" fill="#ffff80"/>
<path d="M119.1 65.5h16.6l1.2 1.3-1.2 1.2h-16.6z" fill="none" stroke="#800000" stroke-width=".21"/>
<path d="M119.1 68h16.6l1.2 1.3-1.2 1.3h-16.6z" fill-rule="evenodd" fill="#ffff80"/>
<path d="M119.1 68h16.6l1.2 1.3-1.2 1.3h-16.6z" fill="none" stroke="#800000" stroke-width=".21"/>
<path d="M119.1 70.6h16.6l1.2 1.2-1.2 1.3h-16.6z" fill-rule="evenodd" fill="#ffff80"/>
<path d="M119.1 70.6h16.6l1.2 1.2-1.2 1.3h-16.6z" fill="none" stroke="#800000" stroke-width=".21"/>
<path d="M164.9 82l1.3-1.3h11.4v2.6h-11.4z" fill-rule="evenodd" fill="#ffff80"/>
<path d="M164.9 82l1.3-1.3h11.4v2.6h-11.4z" fill="none" stroke="#800000" stroke-width=".21"/>
<path d="M119.1 73.1h16.6l1.2 1.3-1.2 1.2h-16.6z" fill-rule="evenodd" fill="#ffff80"/>
<path d="M119.1 73.1h16.6l1.2 1.3-1.2 1.2h-16.6z" fill="none" stroke="#800000" stroke-width=".21"/>
<path d="M119.1 75.6h16.6l1.2 1.3-1.2 1.3h-16.6z" fill-rule="evenodd" fill="#ffff80"/>
<path d="M119.1 75.6h16.6l1.2 1.3-1.2 1.3h-16.6z" fill="none" stroke="#800000" stroke-width=".21"/>
<path d="M48 73.1h11.4l1.3 1.3-1.3 1.2h-11.4z" fill-rule="evenodd" fill="#ffff80"/>
<path d="M48 73.1h11.4l1.3 1.3-1.3 1.2h-11.4z" fill="none" stroke="#800000" stroke-width=".21"/>
<path d="M111.5 94.7h4.5M117.2 94.7h4.5M111.5 104.8h4.5M117.2 104.8h4.5" fill="none" stroke="#000" stroke-width=".25"/>
<path d="M116.6 93.4h1.3l-1.3 2.6h-1.3zM116.6 103.6h1.3l-1.3 2.5h-1.3z" fill="none" stroke="#00f" stroke-width=".25"/>
<path d="M124.2 94.7h2.6M126.8 93.4v2.6M124.2 104.8h2.6M126.8 103.6v2.5" fill="none" stroke="#800000" stroke-width=".25"/>
<path d="M49.2 70.6h11.5v2.5h-11.5l-1.2-1.3z" fill-rule="evenodd" fill="#ffff80"/>
<path d="M49.2 70.6h11.5v2.5h-11.5l-1.2-1.3z" fill="none" stroke="#800000" stroke-width=".21"/>
<path d="M78.5 59.1v2M78.5 67.3v2M187.8 150.6v2M187.8 158.7v2" fill="none" stroke="#000" stroke-width=".25"/>
<path d="M77.4 61.2h2v6h-2zM186.8 152.6h2v6h-2z" fill="none" stroke="#00f" stroke-width=".25"/>
<path d="M77.2 56.6h2.5M78.5 56.6v2.5" fill="none" stroke="#800000" stroke-width=".25"/>
<circle cx="63.2" cy="71.8" r=".51" fill="#000080"/>
<circle cx="63.2" cy="71.8" r=".51" fill="none" stroke="#000080" stroke-width=".21"/>
<path d="M63.2 69.3v2.5" fill="none" stroke="#000" stroke-width=".25"/>
<circle cx="63.2" cy="71.8" r=".51" fill="#000080"/>
<circle cx="63.2" cy="71.8" r=".51" fill="none" stroke="#000080" stroke-width=".21"/>
<circle cx="63.2" cy="68" r="1.27" fill="none" stroke="#000" stroke-width=".25"/>
<circle cx="63.2" cy="74.4" r=".51" fill="#000080"/>
<circle cx="63.2" cy="74.4" r=".51" fill="none" stroke="#000080" stroke-width=".21"/>
<path d="M63.2 74.4v2.5" fill="none" stroke="#000" stroke-width=".25"/>
<circle cx="63.2" cy="74.4" r=".51" fill="#000080"/>
<circle cx="63.2" cy="74.4" r=".51" fill="none" stroke="#000080" stroke-width=".21"/>
<g fill="none" stroke="#000" stroke-width=".25">
<path d="M136.9 142.9h5.1M136.9 145.5v2.5M149.6 163.3h2M157.8 163.3h2M159.8 160.7h2M168 160.7h2"/>
<circle cx="63.2" cy="78.2" r="1.27"/>
</g>
<g fill="none" stroke="#00f" stroke-width=".25">
<path d="M161.9 159.7h6v2.1h-6zM151.7 162.3h6v2h-6z"/>
<circle cx="136.9" cy="142.9" r="2.54"/>
</g>
<circle cx="136.9" cy="142.9" r=".64" fill="#00f"/>
<circle cx="136.9" cy="142.9" r=".64" fill="none" stroke="#00f" stroke-width=".21"/>
<path d="M134.4 150.6h5.1M135.1 151.3h3.6M135.9 152.1h2M136.7 152.8h.5M136.9 148v2.6" fill="none" stroke="#800000" stroke-width=".25"/>
<circle cx="154.7" cy="142.9" r="2.54" fill="none" stroke="#00f" stroke-width=".25"/>
<path d="M149.6 142.9h5.1M154.7 145.5v2.5" fill="none" stroke="#000" stroke-width=".25"/>
<circle cx="154.7" cy="142.9" r=".63" fill="#00f"/>
<circle cx="154.7" cy="142.9" r=".63" fill="none" stroke="#00f" stroke-width=".21"/>
<path d="M152.2 150.6h5.1M152.9 151.3h3.6M153.7 152.1h2M154.5 152.8h.5M154.7 148v2.6" fill="none" stroke="#800000" stroke-width=".25"/>
<circle cx="106.4" cy="94.7" r=".51" fill="#000080"/>
<circle cx="106.4" cy="94.7" r=".51" fill="none" stroke="#000080" stroke-width=".21"/>
<path d="M106.4 92.2v2.5" fill="none" stroke="#000" stroke-width=".25"/>
<circle cx="106.4" cy="94.7" r=".51" fill="#000080"/>
<circle cx="106.4" cy="94.7" r=".51" fill="none" stroke="#000080" stroke-width=".21"/>
<g fill="none" stroke="#000" stroke-width=".25">
<path d="M144.6 61.7v2.5M144.6 79.5v2.5M149.6 61.7v2.5M149.6 79.5v2.5M154.7 61.7v2.5"/>
<circle cx="144.6" cy="60.4" r="1.27"/>
<circle cx="149.6" cy="60.4" r="1.27"/>
<circle cx="154.7" cy="60.4" r="1.27"/>
<circle cx="106.4" cy="90.9" r="1.27"/>
<circle cx="144.6" cy="83.3" r="1.27"/>
<circle cx="149.6" cy="83.3" r="1.27"/>
</g>
<path d="M164.9 96h11.4l1.3 1.2-1.3 1.3h-11.4z" fill-rule="evenodd" fill="#ffff80"/>
<path d="M164.9 96h11.4l1.3 1.2-1.3 1.3h-11.4z" fill="none" stroke="#800000" stroke-width=".21"/>
<path d="M164.9 85.8h11.4l1.3 1.3-1.3 1.2h-11.4z" fill-rule="evenodd" fill="#ffff80"/>
<path d="M164.9 85.8h11.4l1.3 1.3-1.3 1.2h-11.4z" fill="none" stroke="#800000" stroke-width=".21"/>
<path d="M164.9 111.2h11.4l1.3 1.3-1.3 1.2h-11.4z" fill-rule="evenodd" fill="#ffff80"/>
<path d="M164.9 111.2h11.4l1.3 1.3-1.3 1.2h-11.4z" fill="none" stroke="#800000" stroke-width=".21"/>
<path d="M164.9 101h11.4l1.3 1.3-1.3 1.3h-11.4z" fill-rule="evenodd" fill="#ffff80"/>
<path d="M164.9 101h11.4l1.3 1.3-1.3 1.3h-11.4z" fill="none" stroke="#800000" stroke-width=".21"/>
<path d="M164.9 126.4h11.4l1.3 1.3-1.3 1.3h-11.4z" fill-rule="evenodd" fill="#ffff80"/>
<path d="M164.9 126.4h11.4l1.3 1.3-1.3 1.3h-11.4z" fill="none" stroke="#800000" stroke-width=".21"/>
<path d="M164.9 116.3h11.4l1.3 1.3-1.3 1.2h-11.4z" fill-rule="evenodd" fill="#ffff80"/>
<path d="M164.9 116.3h11.4l1.3 1.3-1.3 1.2h-11.4z" fill="none" stroke="#800000" stroke-width=".21"/>
<path d="M164.9 141.7h11.4l1.3 1.2-1.3 1.3h-11.4z" fill-rule="evenodd" fill="#ffff80"/>
<path d="M164.9 141.7h11.4l1.3 1.2-1.3 1.3h-11.4z" fill="none" stroke="#800000" stroke-width=".21"/>
<path d="M164.9 131.5h11.4l1.3 1.3-1.3 1.3h-11.4z" fill-rule="evenodd" fill="#ffff80"/>
<path d="M164.9 131.5h11.4l1.3 1.3-1.3 1.3h-11.4z" fill="none" stroke="#800000" stroke-width=".21"/>
<path d="M78.5 153.1h40.6v17.8h-40.6z" fill-rule="evenodd" fill="#80ff80"/>
<path d="M78.5 153.1h40.6v17.8h-40.6z" fill="none" stroke="#800000" stroke-width=".21"/>
<path d="M115.3 159.7h2.8l1 1-1 1h-2.8z" fill-rule="evenodd" fill="#ffff80"/>
<path d="M115.3 159.7h2.8l1 1-1 1h-2.8z" fill="none" stroke="#800000" stroke-width=".21"/>
<path d="M115.3 162.2h2.8l1 1.1-1 1h-2.8z" fill-rule="evenodd" fill="#ffff80"/>
<path d="M115.3 162.2h2.8l1 1.1-1 1h-2.8z" fill="none" stroke="#800000" stroke-width=".21"/>
<path d="M78.5 167.3h2.8l1 1-1 1.1h-2.8z" fill-rule="evenodd" fill="#ffff80"/>
<path d="M78.5 167.3h2.8l1 1-1 1.1h-2.8z" fill="none" stroke="#800000" stroke-width=".21"/>
<path d="M78.5 159.7h2.8l1 1-1 1h-2.8z" fill-rule="evenodd" fill="#ffff80"/>
<path d="M78.5 159.7h2.8l1 1-1 1h-2.8z" fill="none" stroke="#800000" stroke-width=".21"/>
<path d="M78.5 162.2h2.8l1 1.1-1 1h-2.8z" fill-rule="evenodd" fill="#ffff80"/>
<path d="M78.5 162.2h2.8l1 1.1-1 1h-2.8z" fill="none" stroke="#800000" stroke-width=".21"/>
<path d="M78.5 154.6h2.8l1 1-1 1.1h-2.8z" fill-rule="evenodd" fill="#ffff80"/>
<path d="M78.5 154.6h2.8l1 1-1 1.1h-2.8z" fill="none" stroke="#800000" stroke-width=".21"/>
<path d="M123.2 159.1h1l.5-.5h1l.5 .5h1.1M123.2 159.7h1l.5 .5h1l.5-.5h1.1M123.2 161.6h1l.5-.5h1l.5 .5h1.1M123.2 162.2h1l.5 .5h1l.5-.5h1.1" fill="none" stroke="#d0a19e" stroke-width=".25"/>
<path d="M123.2 159.7l-1.5 1M123.2 162.2l-1.5 1.1" fill="none" stroke="#d0a19e" stroke-width=".21"/>
<path d="M122.9 158.8h1.1l.5-.5h1l.5 .5h1M122.9 159.4h1.1l.5 .6h1l.5-.6h1M122.9 161.4h1.1l.5-.6h1l.5 .6h1M122.9 162h1.1l.5 .5h1l.5-.5h1" fill="none" stroke="#f00" stroke-width=".25"/>
<path d="M122.9 159.4l-1.2 1.3M122.9 162l-1.2 1.3" fill="none" stroke="#f00" stroke-width=".21"/>
<path d="M60.7 23.6h15.2v15.2h-15.2z" fill-rule="evenodd" fill="#ffffb0"/>
<path d="M60.7 23.6h15.2v15.2h-15.2z" fill="none" stroke="#800000" stroke-width=".21"/>
<g fill="none" stroke="#000" stroke-width=".25">
<path d="M14.9 26.1h2M23.1 26.1h2M32.7 28.7v2.5M32.7 36.3v2.5M42.9 31.2v2M42.9 39.4v2M53 26.1h7.7M53 36.3h7.7M53 31.2h7.7M75.9 26.1h7.6M75.9 36.3h7.6M75.9 31.2h7.6"/>
<path d="M86.1 26.1h2.5M98.8 26.1h2.5M103.9 28.7v2.5M103.9 36.3v2.5M111.5 28.7v2M111.5 36.8v2M119.1 28.7v2.5M119.1 36.3v2.5M111.5 43.9v2M111.5 52.1v2"/>
</g>
<g fill="none" stroke="#800000" stroke-width=".25">
<path d="M122.9 21h2.6M124.2 21v2.6M30.2 43.9h5M30.9 44.7h3.6M31.7 45.4h2M32.4 46.2h.6M32.7 41.4v2.5M40.3 43.9h5.1M41.1 44.7h3.6M41.9 45.4h2M42.6 46.2h.5M42.9 41.4v2.5"/>
<path d="M48 43.9h5M48.7 44.7h3.6M49.5 45.4h2M50.2 46.2h.6M50.5 41.4v2.5M109 59.1h5.1M109.7 59.9h3.6M111.5 56.6v2.5M116.6 43.9h5.1M117.4 44.7h3.5M118.1 45.4h2M118.9 46.2h.5"/>
<path d="M119.1 41.4v2.5M110.5 60.7h2M111.3 61.4h.5"/>
</g>
<g fill="none" stroke="#00f" stroke-width=".25">
<path d="M17 25.1h6v2.1h-6zM30.7 34.2h4M30.7 33.2h4M32.7 31.2v2M32.7 34.2v2.1M41.8 33.3h2v6h-2zM88.6 26.1a1.27 1.27 0 0 1 1.3-1.2 1.27 1.27 0 0 1 1.3 1.2 1.27 1.27 0 0 1 1.2-1.2 1.27 1.27 0 0 1 1.3 1.2 1.27 1.27 0 0 1 1.3-1.2 1.27 1.27 0 0 1 1.3 1.2 1.27 1.27 0 0 1 1.2-1.2 1.27 1.27 0 0 1 1.3 1.2M88.6 24.1h10.2M88.6 23.6h10.2M101.9 34.2h4M101.9 33.2h4M103.9 31.2v2"/>
<path d="M103.9 34.2v2.1M110.5 30.7h2.1v6h-2.1zM117.1 34.2h4M117.1 33.2h4M119.1 31.2v2M119.1 34.2v2.1M110.5 46h2.1v6h-2.1z"/>
</g>
<path d="M82.5 35.3l2.1 2M84.6 35.3l-2.1 2" fill="none" stroke="#f00" stroke-width=".21"/>
<circle cx="12.4" cy="26.1" r=".51" fill="#000080"/>
<circle cx="12.4" cy="26.1" r=".51" fill="none" stroke="#000080" stroke-width=".21"/>
<path d="M12.4 26.1v2.6" fill="none" stroke="#000" stroke-width=".25"/>
<circle cx="12.4" cy="26.1" r=".51" fill="#000080"/>
<circle cx="12.4" cy="26.1" r=".51" fill="none" stroke="#000080" stroke-width=".21"/>
<circle cx="12.4" cy="29.9" r="1.27" fill="none" stroke="#000" stroke-width=".25"/>
<circle cx="27.6" cy="26.1" r=".51" fill="#000080"/>
<circle cx="27.6" cy="26.1" r=".51" fill="none" stroke="#000080" stroke-width=".21"/>
<path d="M27.6 23.6v2.5" fill="none" stroke="#000" stroke-width=".25"/>
<circle cx="27.6" cy="26.1" r=".51" fill="#000080"/>
<circle cx="27.6" cy="26.1" r=".51" fill="none" stroke="#000080" stroke-width=".21"/>
<circle cx="27.6" cy="22.3" r="1.27" fill="none" stroke="#000" stroke-width=".25"/>
<path d="M11.1 21h2.5M12.4 21v2.6" fill="none" stroke="#800000" stroke-width=".25"/>
<path d="M53 92.2h20.4v12.6h-20.4z" fill-rule="evenodd" fill="#ffffb0"/>
<path d="M53 92.2h20.4v12.6h-20.4z" fill="none" stroke="#800000" stroke-width=".21"/>
<path d="M14.9 94.7h2M23.1 94.7h2M27.6 97.2v2.6M45.4 94.7h7.6M45.4 97.2h7.6M73.4 94.7h7.6M73.4 97.2h7.6M27.6 104.8v2.6M45.4 102.3h7.6M73.4 102.3h7.6" fill="none" stroke="#000" stroke-width=".25"/>
<path d="M17 93.7h6v2h-6zM27.6 99.8v2M25.6 102.8h4M25.6 101.8h4M27.6 102.8v2" fill="none" stroke="#00f" stroke-width=".25"/>
<path d="M25.1 112.5h5.1M25.8 113.2h3.6M26.6 114h2M27.4 114.8h.5M27.6 109.9v2.6" fill="none" stroke="#800000" stroke-width=".25"/>
<circle cx="12.4" cy="94.7" r=".51" fill="#000080"/>
<circle cx="12.4" cy="94.7" r=".51" fill="none" stroke="#000080" stroke-width=".21"/>
<path d="M12.4 94.7v2.5" fill="none" stroke="#000" stroke-width=".25"/>
<circle cx="12.4" cy="94.7" r=".51" fill="#000080"/>
<circle cx="12.4" cy="94.7" r=".51" fill="none" stroke="#000080" stroke-width=".21"/>
<circle cx="12.4" cy="98.5" r="1.27" fill="none" stroke="#000" stroke-width=".25"/>
<circle cx="30.2" cy="94.7" r=".51" fill="#000080"/>
<circle cx="30.2" cy="94.7" r=".51" fill="none" stroke="#000080" stroke-width=".21"/>
<path d="M30.2 92.2v2.5" fill="none" stroke="#000" stroke-width=".25"/>
<circle cx="30.2" cy="94.7" r=".51" fill="#000080"/>
<circle cx="30.2" cy="94.7" r=".51" fill="none" stroke="#000080" stroke-width=".21"/>
<g fill="none" stroke="#000" stroke-width=".25">
<path d="M42.9 104.8v2.6M42.9 112.5v2.5M111.5 115h4.5M117.2 115h4.5M111.5 125.2h4.5M117.2 125.2h4.5"/>
<circle cx="30.2" cy="90.9" r="1.27"/>
</g>
<g fill="none" stroke="#800000" stroke-width=".25">
<path d="M11.1 89.6h2.5M12.4 89.6v2.6M36.5 99.8h2.6M37.8 99.8v2.5M40.3 117.5h5.1M41.1 118.3h3.6M41.9 119.1h2M42.6 119.8h.5M42.9 115v2.5M81 112.5h5.1M81.8 113.2h3.5M82.5 114h2.1"/>
<path d="M83.3 114.8h.5M83.5 109.9v2.6M124.2 115h2.6M126.8 113.7v2.6M124.2 125.2h2.6M126.8 123.9v2.5"/>
</g>
<path d="M40.9 110.4h4M40.9 109.4h4M42.9 107.4v2M42.9 110.4v2.1M116.6 113.7h1.3l-1.3 2.6h-1.3zM116.6 123.9h1.3l-1.3 2.5h-1.3z" fill="none" stroke="#00f" stroke-width=".25"/>
<path d="M50.5 167.1h14l1.2 1.2-1.2 1.3h-14z" fill-rule="evenodd" fill="#ffff80"/>
<path d="M50.5 167.1h14l1.2 1.2-1.2 1.3h-14z" fill="none" stroke="#800000" stroke-width=".21"/>
<path d="M50.5 162h14l1.2 1.3-1.2 1.2h-14z" fill-rule="evenodd" fill="#ffff80"/>
<path d="M50.5 162h14l1.2 1.3-1.2 1.2h-14z" fill="none" stroke="#800000" stroke-width=".21"/>
<path d="M50.5 159.4h14l1.2 1.3-1.2 1.3h-14z" fill-rule="evenodd" fill="#ffff80"/>
<path d="M50.5 159.4h14l1.2 1.3-1.2 1.3h-14z" fill="none" stroke="#800000" stroke-width=".21"/>
<path d="M93.7 107.4v2.5M101.3 107.4v2.5M93.7 125.2v2.5" fill="none" stroke="#000080" stroke-width=".25"/>
<circle cx="93.7" cy="109.9" r=".51" fill="#000080"/>
<circle cx="93.7" cy="109.9" r=".51" fill="none" stroke="#000080" stroke-width=".21"/>
<path d="M93.7 94.7v2.5" fill="none" stroke="#000080" stroke-width=".25"/>
<circle cx="93.7" cy="94.7" r=".51" fill="#000080"/>
<circle cx="93.7" cy="94.7" r=".51" fill="none" stroke="#000080" stroke-width=".21"/>
<path d="M172.5 64.2v2.6h20.4" fill="none" stroke="#000080" stroke-width=".25"/>
<circle cx="172.5" cy="66.8" r=".51" fill="#000080"/>
<circle cx="172.5" cy="66.8" r=".51" fill="none" stroke="#000080" stroke-width=".21"/>
<path d="M167.4 64.2v5.1h25.5" fill="none" stroke="#000080" stroke-width=".25"/>
<circle cx="167.4" cy="69.3" r=".51" fill="#000080"/>
<circle cx="167.4" cy="69.3" r=".51" fill="none" stroke="#000080" stroke-width=".21"/>
<path d="M162.3 64.2v7.6h30.6" fill="none" stroke="#000080" stroke-width=".25"/>
<circle cx="162.3" cy="71.8" r=".51" fill="#000080"/>
<circle cx="162.3" cy="71.8" r=".51" fill="none" stroke="#000080" stroke-width=".21"/>
<path d="M136.9 66.8h35.6" fill="none" stroke="#000080" stroke-width=".25"/>
<circle cx="172.5" cy="66.8" r=".51" fill="#000080"/>
<circle cx="172.5" cy="66.8" r=".51" fill="none" stroke="#000080" stroke-width=".21"/>
<circle cx="154.7" cy="66.8" r=".51" fill="#000080"/>
<circle cx="154.7" cy="66.8" r=".51" fill="none" stroke="#000080" stroke-width=".21"/>
<path d="M136.9 69.3h30.5" fill="none" stroke="#000080" stroke-width=".25"/>
<circle cx="167.4" cy="69.3" r=".51" fill="#000080"/>
<circle cx="167.4" cy="69.3" r=".51" fill="none" stroke="#000080" stroke-width=".21"/>
<circle cx="149.6" cy="69.3" r=".51" fill="#000080"/>
<circle cx="149.6" cy="69.3" r=".51" fill="none" stroke="#000080" stroke-width=".21"/>
<path d="M136.9 71.8h25.4" fill="none" stroke="#000080" stroke-width=".25"/>
<circle cx="144.6" cy="71.8" r=".51" fill="#000080"/>
<circle cx="144.6" cy="71.8" r=".51" fill="none" stroke="#000080" stroke-width=".21"/>
<circle cx="162.3" cy="71.8" r=".51" fill="#000080"/>
<circle cx="162.3" cy="71.8" r=".51" fill="none" stroke="#000080" stroke-width=".21"/>
<path d="M220.8 163.3h-5.1v2.5" fill="none" stroke="#000080" stroke-width=".25"/>
<circle cx="215.7" cy="163.3" r=".51" fill="#000080"/>
<circle cx="215.7" cy="163.3" r=".51" fill="none" stroke="#000080" stroke-width=".21"/>
<circle cx="218.3" cy="163.3" r=".51" fill="#000080"/>
<circle cx="218.3" cy="163.3" r=".51" fill="none" stroke="#000080" stroke-width=".21"/>
<circle cx="220.8" cy="163.3" r=".51" fill="#000080"/>
<circle cx="220.8" cy="163.3" r=".51" fill="none" stroke="#000080" stroke-width=".21"/>
<path d="M218.3 160.7v2.6" fill="none" stroke="#000080" stroke-width=".25"/>
<circle cx="218.3" cy="163.3" r=".51" fill="#000080"/>
<circle cx="218.3" cy="163.3" r=".51" fill="none" stroke="#000080" stroke-width=".21"/>
<path d="M220.8 160.7v2.6" fill="none" stroke="#000080" stroke-width=".25"/>
<circle cx="220.8" cy="163.3" r=".51" fill="#000080"/>
<circle cx="220.8" cy="163.3" r=".51" fill="none" stroke="#000080" stroke-width=".21"/>
<path d="M223.4 160.7v2.6" fill="none" stroke="#000080" stroke-width=".25"/>
<circle cx="223.4" cy="163.3" r=".51" fill="#000080"/>
<circle cx="223.4" cy="163.3" r=".51" fill="none" stroke="#000080" stroke-width=".21"/>
<path d="M231 160.7v2.6h2.5v-2.6" fill="none" stroke="#000080" stroke-width=".25"/>
<circle cx="231" cy="163.3" r=".51" fill="#000080"/>
<circle cx="231" cy="163.3" r=".51" fill="none" stroke="#000080" stroke-width=".21"/>
<path d="M231 163.3v2.5" fill="none" stroke="#000080" stroke-width=".25"/>
<circle cx="231" cy="163.3" r=".51" fill="#000080"/>
<circle cx="231" cy="163.3" r=".51" fill="none" stroke="#000080" stroke-width=".21"/>
<path d="M225.9 160.7v2.6h-5.1" fill="none" stroke="#000080" stroke-width=".25"/>
<circle cx="223.4" cy="163.3" r=".51" fill="#000080"/>
<circle cx="223.4" cy="163.3" r=".51" fill="none" stroke="#000080" stroke-width=".21"/>
<circle cx="220.8" cy="163.3" r=".51" fill="#000080"/>
<circle cx="220.8" cy="163.3" r=".51" fill="none" stroke="#000080" stroke-width=".21"/>
<path d="M215.7 160.7v2.6" fill="none" stroke="#000080" stroke-width=".25"/>
<circle cx="215.7" cy="163.3" r=".51" fill="#000080"/>
<circle cx="215.7" cy="163.3" r=".51" fill="none" stroke="#000080" stroke-width=".21"/>
<path d="M192.9 41.4h27.9v12.7" fill="none" stroke="#000080" stroke-width=".25"/>
<circle cx="220.8" cy="54.1" r=".51" fill="#000080"/>
<circle cx="220.8" cy="54.1" r=".51" fill="none" stroke="#000080" stroke-width=".21"/>
<circle cx="220.8" cy="41.4" r=".51" fill="#000080"/>
<circle cx="220.8" cy="41.4" r=".51" fill="none" stroke="#000080" stroke-width=".21"/>
<circle cx="203" cy="41.4" r=".51" fill="#000080"/>
<circle cx="203" cy="41.4" r=".51" fill="none" stroke="#000080" stroke-width=".21"/>
<circle cx="192.9" cy="41.4" r=".51" fill="#000080"/>
<circle cx="192.9" cy="41.4" r=".51" fill="none" stroke="#000080" stroke-width=".21"/>
<path d="M271.6 21h-45.7v33.1" fill="none" stroke="#000080" stroke-width=".25"/>
<circle cx="225.9" cy="54.1" r=".51" fill="#000080"/>
<circle cx="225.9" cy="54.1" r=".51" fill="none" stroke="#000080" stroke-width=".21"/>
<circle cx="231" cy="21" r=".51" fill="#000080"/>
<circle cx="231" cy="21" r=".51" fill="none" stroke="#000080" stroke-width=".21"/>
<circle cx="241.2" cy="21" r=".51" fill="#000080"/>
<circle cx="241.2" cy="21" r=".51" fill="none" stroke="#000080" stroke-width=".21"/>
<circle cx="251.3" cy="21" r=".51" fill="#000080"/>
<circle cx="251.3" cy="21" r=".51" fill="none" stroke="#000080" stroke-width=".21"/>
<circle cx="261.5" cy="21" r=".51" fill="#000080"/>
<circle cx="261.5" cy="21" r=".51" fill="none" stroke="#000080" stroke-width=".21"/>
<path d="M162.3 54.1v-2.6h10.2v2.6" fill="none" stroke="#000080" stroke-width=".25"/>
<circle cx="162.3" cy="51.5" r=".51" fill="#000080"/>
<circle cx="162.3" cy="51.5" r=".51" fill="none" stroke="#000080" stroke-width=".21"/>
<circle cx="167.4" cy="51.5" r=".51" fill="#000080"/>
<circle cx="167.4" cy="51.5" r=".51" fill="none" stroke="#000080" stroke-width=".21"/>
<path d="M167.4 51.5v2.6" fill="none" stroke="#000080" stroke-width=".25"/>
<circle cx="167.4" cy="51.5" r=".51" fill="#000080"/>
<circle cx="167.4" cy="51.5" r=".51" fill="none" stroke="#000080" stroke-width=".21"/>
<path d="M162.3 49v2.5" fill="none" stroke="#000080" stroke-width=".25"/>
<circle cx="162.3" cy="51.5" r=".51" fill="#000080"/>
<circle cx="162.3" cy="51.5" r=".51" fill="none" stroke="#000080" stroke-width=".21"/>
<path d="M271.6 41.4h-38.1v15.2" fill="none" stroke="#000080" stroke-width=".25"/>
<circle cx="251.3" cy="41.4" r=".51" fill="#000080"/>
<circle cx="251.3" cy="41.4" r=".51" fill="none" stroke="#000080" stroke-width=".21"/>
<circle cx="241.2" cy="41.4" r=".51" fill="#000080"/>
<circle cx="241.2" cy="41.4" r=".51" fill="none" stroke="#000080" stroke-width=".21"/>
<path d="M218.3 54.1v2.5" fill="none" stroke="#000080" stroke-width=".25"/>
<circle cx="218.3" cy="54.1" r=".51" fill="#000080"/>
<circle cx="218.3" cy="54.1" r=".51" fill="none" stroke="#000080" stroke-width=".21"/>
<path d="M225.9 56.6v-2.5h2.5v2.5" fill="none" stroke="#000080" stroke-width=".25"/>
<circle cx="225.9" cy="54.1" r=".51" fill="#000080"/>
<circle cx="225.9" cy="54.1" r=".51" fill="none" stroke="#000080" stroke-width=".21"/>
<path d="M215.7 56.6v-2.5h5.1v2.5" fill="none" stroke="#000080" stroke-width=".25"/>
<circle cx="218.3" cy="54.1" r=".51" fill="#000080"/>
<circle cx="218.3" cy="54.1" r=".51" fill="none" stroke="#000080" stroke-width=".21"/>
<circle cx="220.8" cy="54.1" r=".51" fill="#000080"/>
<circle cx="220.8" cy="54.1" r=".51" fill="none" stroke="#000080" stroke-width=".21"/>
<path d="M157.3 21h63.5v20.4" fill="none" stroke="#000080" stroke-width=".25"/>
<circle cx="220.8" cy="41.4" r=".51" fill="#000080"/>
<circle cx="220.8" cy="41.4" r=".51" fill="none" stroke="#000080" stroke-width=".21"/>
<circle cx="213.2" cy="21" r=".51" fill="#000080"/>
<circle cx="213.2" cy="21" r=".51" fill="none" stroke="#000080" stroke-width=".21"/>
<circle cx="203" cy="21" r=".51" fill="#000080"/>
<circle cx="203" cy="21" r=".51" fill="none" stroke="#000080" stroke-width=".21"/>
<circle cx="192.9" cy="21" r=".51" fill="#000080"/>
<circle cx="192.9" cy="21" r=".51" fill="none" stroke="#000080" stroke-width=".21"/>
<circle cx="182.7" cy="21" r=".51" fill="#000080"/>
<circle cx="182.7" cy="21" r=".51" fill="none" stroke="#000080" stroke-width=".21"/>
<circle cx="172.5" cy="21" r=".51" fill="#000080"/>
<circle cx="172.5" cy="21" r=".51" fill="none" stroke="#000080" stroke-width=".21"/>
<circle cx="162.3" cy="21" r=".51" fill="#000080"/>
<circle cx="162.3" cy="21" r=".51" fill="none" stroke="#000080" stroke-width=".21"/>
<path d="M157.3 41.4h35.6" fill="none" stroke="#000080" stroke-width=".25"/>
<circle cx="182.7" cy="41.4" r=".51" fill="#000080"/>
<circle cx="182.7" cy="41.4" r=".51" fill="none" stroke="#000080" stroke-width=".21"/>
<circle cx="192.9" cy="41.4" r=".51" fill="#000080"/>
<circle cx="192.9" cy="41.4" r=".51" fill="none" stroke="#000080" stroke-width=".21"/>
<path d="M177.6 87.1h15.3" fill="none" stroke="#000080" stroke-width=".25"/>
<circle cx="187.8" cy="87.1" r=".51" fill="#000080"/>
<circle cx="187.8" cy="87.1" r=".51" fill="none" stroke="#000080" stroke-width=".21"/>
<path d="M177.6 97.2h15.3" fill="none" stroke="#000080" stroke-width=".25"/>
<circle cx="187.8" cy="97.2" r=".51" fill="#000080"/>
<circle cx="187.8" cy="97.2" r=".51" fill="none" stroke="#000080" stroke-width=".21"/>
<path d="M177.6 102.3h15.3" fill="none" stroke="#000080" stroke-width=".25"/>
<circle cx="187.8" cy="102.3" r=".51" fill="#000080"/>
<circle cx="187.8" cy="102.3" r=".51" fill="none" stroke="#000080" stroke-width=".21"/>
<path d="M177.6 112.5h15.3" fill="none" stroke="#000080" stroke-width=".25"/>
<circle cx="187.8" cy="112.5" r=".51" fill="#000080"/>
<circle cx="187.8" cy="112.5" r=".51" fill="none" stroke="#000080" stroke-width=".21"/>
<path d="M177.6 117.6h15.3" fill="none" stroke="#000080" stroke-width=".25"/>
<circle cx="187.8" cy="117.6" r=".51" fill="#000080"/>
<circle cx="187.8" cy="117.6" r=".51" fill="none" stroke="#000080" stroke-width=".21"/>
<path d="M177.6 127.7h15.3" fill="none" stroke="#000080" stroke-width=".25"/>
<circle cx="187.8" cy="127.7" r=".51" fill="#000080"/>
<circle cx="187.8" cy="127.7" r=".51" fill="none" stroke="#000080" stroke-width=".21"/>
<path d="M177.6 132.8h15.3" fill="none" stroke="#000080" stroke-width=".25"/>
<circle cx="187.8" cy="132.8" r=".51" fill="#000080"/>
<circle cx="187.8" cy="132.8" r=".51" fill="none" stroke="#000080" stroke-width=".21"/>
<path d="M177.6 142.9h15.3" fill="none" stroke="#000080" stroke-width=".25"/>
<circle cx="187.8" cy="142.9" r=".51" fill="#000080"/>
<circle cx="187.8" cy="142.9" r=".51" fill="none" stroke="#000080" stroke-width=".21"/>
<g fill="none" stroke="#000080" stroke-width=".25">
<path d="M136.9 74.4h56M256.4 74.4h7.6M256.4 76.9h7.6M256.4 82h7.6M256.4 84.5h7.6M256.4 89.6h7.6M256.4 92.2h7.6M256.4 97.2h7.6M256.4 99.8h7.6M256.4 104.9h7.6M256.4 107.4h7.6M256.4 112.5h7.6"/>
<path d="M256.4 115h7.6M256.4 120.1h7.6M256.4 122.6h7.6M256.4 127.7h7.6M256.4 130.3h7.6M256.4 135.3h7.6M256.4 137.9h7.6M256.4 142.9h7.6M256.4 145.5h7.6"/>
</g>
<circle cx="149.6" cy="74.4" r=".51" fill="#000080"/>
<circle cx="149.6" cy="74.4" r=".51" fill="none" stroke="#000080" stroke-width=".21"/>
<path d="M136.9 76.9h56" fill="none" stroke="#000080" stroke-width=".25"/>
<circle cx="144.6" cy="76.9" r=".51" fill="#000080"/>
<circle cx="144.6" cy="76.9" r=".51" fill="none" stroke="#000080" stroke-width=".21"/>
<path d="M60.7 74.4h15.2M177.6 82h15.3" fill="none" stroke="#000080" stroke-width=".25"/>
<circle cx="63.2" cy="74.4" r=".51" fill="#000080"/>
<circle cx="63.2" cy="74.4" r=".51" fill="none" stroke="#000080" stroke-width=".21"/>
<path d="M109 94.7v10.1h2.5" fill="none" stroke="#000080" stroke-width=".25"/>
<circle cx="109" cy="104.8" r=".51" fill="#000080"/>
<circle cx="109" cy="104.8" r=".51" fill="none" stroke="#000080" stroke-width=".21"/>
<circle cx="109" cy="94.7" r=".51" fill="#000080"/>
<circle cx="109" cy="94.7" r=".51" fill="none" stroke="#000080" stroke-width=".21"/>
<path d="M93.7 94.7h17.8M121.7 94.7h2.5M121.7 104.8h2.5" fill="none" stroke="#000080" stroke-width=".25"/>
<circle cx="93.7" cy="94.7" r=".51" fill="#000080"/>
<circle cx="93.7" cy="94.7" r=".51" fill="none" stroke="#000080" stroke-width=".21"/>
<circle cx="101.3" cy="94.7" r=".51" fill="#000080"/>
<circle cx="101.3" cy="94.7" r=".51" fill="none" stroke="#000080" stroke-width=".21"/>
<circle cx="106.4" cy="94.7" r=".51" fill="#000080"/>
<circle cx="106.4" cy="94.7" r=".51" fill="none" stroke="#000080" stroke-width=".21"/>
<circle cx="109" cy="94.7" r=".51" fill="#000080"/>
<circle cx="109" cy="94.7" r=".51" fill="none" stroke="#000080" stroke-width=".21"/>
<path d="M81 94.7h12.7" fill="none" stroke="#000080" stroke-width=".25"/>
<circle cx="93.7" cy="94.7" r=".51" fill="#000080"/>
<circle cx="93.7" cy="94.7" r=".51" fill="none" stroke="#000080" stroke-width=".21"/>
<path d="M101.3 94.7v2.5" fill="none" stroke="#000080" stroke-width=".25"/>
<circle cx="101.3" cy="94.7" r=".51" fill="#000080"/>
<circle cx="101.3" cy="94.7" r=".51" fill="none" stroke="#000080" stroke-width=".21"/>
<path d="M78.5 69.3v2.5h-17.8" fill="none" stroke="#000080" stroke-width=".25"/>
<circle cx="63.2" cy="71.8" r=".51" fill="#000080"/>
<circle cx="63.2" cy="71.8" r=".51" fill="none" stroke="#000080" stroke-width=".21"/>
<path d="M187.8 160.7v2.6" fill="none" stroke="#000080" stroke-width=".25"/>
<circle cx="187.8" cy="163.3" r=".51" fill="#000080"/>
<circle cx="187.8" cy="163.3" r=".51" fill="none" stroke="#000080" stroke-width=".21"/>
<path d="M187.8 148v2.6" fill="none" stroke="#000080" stroke-width=".25"/>
<circle cx="187.8" cy="148" r=".51" fill="#000080"/>
<circle cx="187.8" cy="148" r=".51" fill="none" stroke="#000080" stroke-width=".21"/>
<path d="M119.1 163.3h30.5" fill="none" stroke="#000080" stroke-width=".25"/>
<circle cx="144.6" cy="163.3" r=".51" fill="#000080"/>
<circle cx="144.6" cy="163.3" r=".51" fill="none" stroke="#000080" stroke-width=".21"/>
<path d="M119.1 160.7h40.7" fill="none" stroke="#000080" stroke-width=".25"/>
<circle cx="147.1" cy="160.7" r=".51" fill="#000080"/>
<circle cx="147.1" cy="160.7" r=".51" fill="none" stroke="#000080" stroke-width=".21"/>
<path d="M192.9 148h-10.2v12.7h-12.7" fill="none" stroke="#000080" stroke-width=".25"/>
<circle cx="187.8" cy="148" r=".51" fill="#000080"/>
<circle cx="187.8" cy="148" r=".51" fill="none" stroke="#000080" stroke-width=".21"/>
<path d="M142 142.9h2.6v20.4" fill="none" stroke="#000080" stroke-width=".25"/>
<circle cx="144.6" cy="163.3" r=".51" fill="#000080"/>
<circle cx="144.6" cy="163.3" r=".51" fill="none" stroke="#000080" stroke-width=".21"/>
<path d="M149.6 142.9h-2.5v17.8" fill="none" stroke="#000080" stroke-width=".25"/>
<circle cx="147.1" cy="160.7" r=".51" fill="#000080"/>
<circle cx="147.1" cy="160.7" r=".51" fill="none" stroke="#000080" stroke-width=".21"/>
<path d="M154.7 64.2v2.6" fill="none" stroke="#000080" stroke-width=".25"/>
<circle cx="154.7" cy="66.8" r=".51" fill="#000080"/>
<circle cx="154.7" cy="66.8" r=".51" fill="none" stroke="#000080" stroke-width=".21"/>
<path d="M149.6 64.2v5.1" fill="none" stroke="#000080" stroke-width=".25"/>
<circle cx="149.6" cy="69.3" r=".51" fill="#000080"/>
<circle cx="149.6" cy="69.3" r=".51" fill="none" stroke="#000080" stroke-width=".21"/>
<path d="M144.6 64.2v7.6" fill="none" stroke="#000080" stroke-width=".25"/>
<circle cx="144.6" cy="71.8" r=".51" fill="#000080"/>
<circle cx="144.6" cy="71.8" r=".51" fill="none" stroke="#000080" stroke-width=".21"/>
<path d="M149.6 74.4v5.1" fill="none" stroke="#000080" stroke-width=".25"/>
<circle cx="149.6" cy="74.4" r=".51" fill="#000080"/>
<circle cx="149.6" cy="74.4" r=".51" fill="none" stroke="#000080" stroke-width=".21"/>
<path d="M144.6 76.9v2.6" fill="none" stroke="#000080" stroke-width=".25"/>
<circle cx="144.6" cy="76.9" r=".51" fill="#000080"/>
<circle cx="144.6" cy="76.9" r=".51" fill="none" stroke="#000080" stroke-width=".21"/>
<path d="M192.9 150.6v12.7h-33.1" fill="none" stroke="#000080" stroke-width=".25"/>
<circle cx="187.8" cy="163.3" r=".51" fill="#000080"/>
<circle cx="187.8" cy="163.3" r=".51" fill="none" stroke="#000080" stroke-width=".21"/>
<path d="M32.7 38.8v2.6M42.9 31.2h10.1M53 36.3h-2.5v5.1M53 26.1h-20.3v2.6M83.5 26.1h2.6" fill="none" stroke="#000080" stroke-width=".25"/>
<circle cx="32.7" cy="26.1" r=".51" fill="#000080"/>
<circle cx="32.7" cy="26.1" r=".51" fill="none" stroke="#000080" stroke-width=".21"/>
<path d="M119.1 38.8v2.6M124.2 23.6v2.5h-5.1" fill="none" stroke="#000080" stroke-width=".25"/>
<circle cx="119.1" cy="26.1" r=".51" fill="#000080"/>
<circle cx="119.1" cy="26.1" r=".51" fill="none" stroke="#000080" stroke-width=".21"/>
<path d="M111.5 26.1v2.6" fill="none" stroke="#000080" stroke-width=".25"/>
<circle cx="111.5" cy="26.1" r=".51" fill="#000080"/>
<circle cx="111.5" cy="26.1" r=".51" fill="none" stroke="#000080" stroke-width=".21"/>
<path d="M101.3 26.1h17.8v2.6" fill="none" stroke="#000080" stroke-width=".25"/>
<circle cx="103.9" cy="26.1" r=".51" fill="#000080"/>
<circle cx="103.9" cy="26.1" r=".51" fill="none" stroke="#000080" stroke-width=".21"/>
<circle cx="111.5" cy="26.1" r=".51" fill="#000080"/>
<circle cx="111.5" cy="26.1" r=".51" fill="none" stroke="#000080" stroke-width=".21"/>
<circle cx="119.1" cy="26.1" r=".51" fill="#000080"/>
<circle cx="119.1" cy="26.1" r=".51" fill="none" stroke="#000080" stroke-width=".21"/>
<path d="M103.9 26.1v2.6" fill="none" stroke="#000080" stroke-width=".25"/>
<circle cx="103.9" cy="26.1" r=".51" fill="#000080"/>
<circle cx="103.9" cy="26.1" r=".51" fill="none" stroke="#000080" stroke-width=".21"/>
<path d="M111.5 38.8v5.1M111.5 54.1v2.5" fill="none" stroke="#000080" stroke-width=".25"/>
<circle cx="111.5" cy="41.4" r=".51" fill="#000080"/>
<circle cx="111.5" cy="41.4" r=".51" fill="none" stroke="#000080" stroke-width=".21"/>
<path d="M83.5 31.2h10.2v10.2h17.8" fill="none" stroke="#000080" stroke-width=".25"/>
<circle cx="111.5" cy="41.4" r=".51" fill="#000080"/>
<circle cx="111.5" cy="41.4" r=".51" fill="none" stroke="#000080" stroke-width=".21"/>
<circle cx="103.9" cy="41.4" r=".51" fill="#000080"/>
<circle cx="103.9" cy="41.4" r=".51" fill="none" stroke="#000080" stroke-width=".21"/>
<path d="M103.9 38.8v2.6" fill="none" stroke="#000080" stroke-width=".25"/>
<circle cx="103.9" cy="41.4" r=".51" fill="#000080"/>
<circle cx="103.9" cy="41.4" r=".51" fill="none" stroke="#000080" stroke-width=".21"/>
<path d="M12.4 23.6v2.5h2.5" fill="none" stroke="#000080" stroke-width=".25"/>
<circle cx="12.4" cy="26.1" r=".51" fill="#000080"/>
<circle cx="12.4" cy="26.1" r=".51" fill="none" stroke="#000080" stroke-width=".21"/>
<path d="M25.1 26.1h7.6" fill="none" stroke="#000080" stroke-width=".25"/>
<circle cx="27.6" cy="26.1" r=".51" fill="#000080"/>
<circle cx="27.6" cy="26.1" r=".51" fill="none" stroke="#000080" stroke-width=".21"/>
<circle cx="32.7" cy="26.1" r=".51" fill="#000080"/>
<circle cx="32.7" cy="26.1" r=".51" fill="none" stroke="#000080" stroke-width=".21"/>
<path d="M12.4 92.2v2.5h2.5M27.6 107.4v2.5" fill="none" stroke="#000080" stroke-width=".25"/>
<circle cx="12.4" cy="94.7" r=".51" fill="#000080"/>
<circle cx="12.4" cy="94.7" r=".51" fill="none" stroke="#000080" stroke-width=".21"/>
<path d="M25.1 94.7h2.5" fill="none" stroke="#000080" stroke-width=".25"/>
<circle cx="27.6" cy="94.7" r=".51" fill="#000080"/>
<circle cx="27.6" cy="94.7" r=".51" fill="none" stroke="#000080" stroke-width=".21"/>
<path d="M27.6 94.7v2.5" fill="none" stroke="#000080" stroke-width=".25"/>
<circle cx="27.6" cy="94.7" r=".51" fill="#000080"/>
<circle cx="27.6" cy="94.7" r=".51" fill="none" stroke="#000080" stroke-width=".21"/>
<path d="M42.9 94.7v2.5h2.5" fill="none" stroke="#000080" stroke-width=".25"/>
<circle cx="42.9" cy="94.7" r=".51" fill="#000080"/>
<circle cx="42.9" cy="94.7" r=".51" fill="none" stroke="#000080" stroke-width=".21"/>
<path d="M27.6 94.7h17.8M81 102.3h2.5v7.6" fill="none" stroke="#000080" stroke-width=".25"/>
<circle cx="27.6" cy="94.7" r=".51" fill="#000080"/>
<circle cx="27.6" cy="94.7" r=".51" fill="none" stroke="#000080" stroke-width=".21"/>
<circle cx="30.2" cy="94.7" r=".51" fill="#000080"/>
<circle cx="30.2" cy="94.7" r=".51" fill="none" stroke="#000080" stroke-width=".21"/>
<circle cx="42.9" cy="94.7" r=".51" fill="#000080"/>
<circle cx="42.9" cy="94.7" r=".51" fill="none" stroke="#000080" stroke-width=".21"/>
<path d="M81 97.2h7.6v12.7h5.1v5.1" fill="none" stroke="#000080" stroke-width=".25"/>
<circle cx="93.7" cy="109.9" r=".51" fill="#000080"/>
<circle cx="93.7" cy="109.9" r=".51" fill="none" stroke="#000080" stroke-width=".21"/>
<path d="M45.4 102.3h-2.5v2.5" fill="none" stroke="#000080" stroke-width=".25"/>
<circle cx="42.9" cy="102.3" r=".51" fill="#000080"/>
<circle cx="42.9" cy="102.3" r=".51" fill="none" stroke="#000080" stroke-width=".21"/>
<path d="M37.8 102.3h5.1" fill="none" stroke="#000080" stroke-width=".25"/>
<circle cx="42.9" cy="102.3" r=".51" fill="#000080"/>
<circle cx="42.9" cy="102.3" r=".51" fill="none" stroke="#000080" stroke-width=".21"/>
<path d="M109 115v10.2h2.5" fill="none" stroke="#000080" stroke-width=".25"/>
<circle cx="109" cy="115" r=".51" fill="#000080"/>
<circle cx="109" cy="115" r=".51" fill="none" stroke="#000080" stroke-width=".21"/>
<path d="M109 104.8v10.2h2.5M121.7 115h2.5M121.7 125.2h2.5" fill="none" stroke="#000080" stroke-width=".25"/>
<circle cx="109" cy="104.8" r=".51" fill="#000080"/>
<circle cx="109" cy="104.8" r=".51" fill="none" stroke="#000080" stroke-width=".21"/>
<circle cx="109" cy="115" r=".51" fill="#000080"/>
<circle cx="109" cy="115" r=".51" fill="none" stroke="#000080" stroke-width=".21"/>
<path d="M65.7 155.6h12.8M65.7 160.7h12.8M65.7 163.3h12.8M65.7 168.3h12.8" fill="none" stroke="#000080" stroke-width=".25"/>
<use href="#words"/>
</svg>
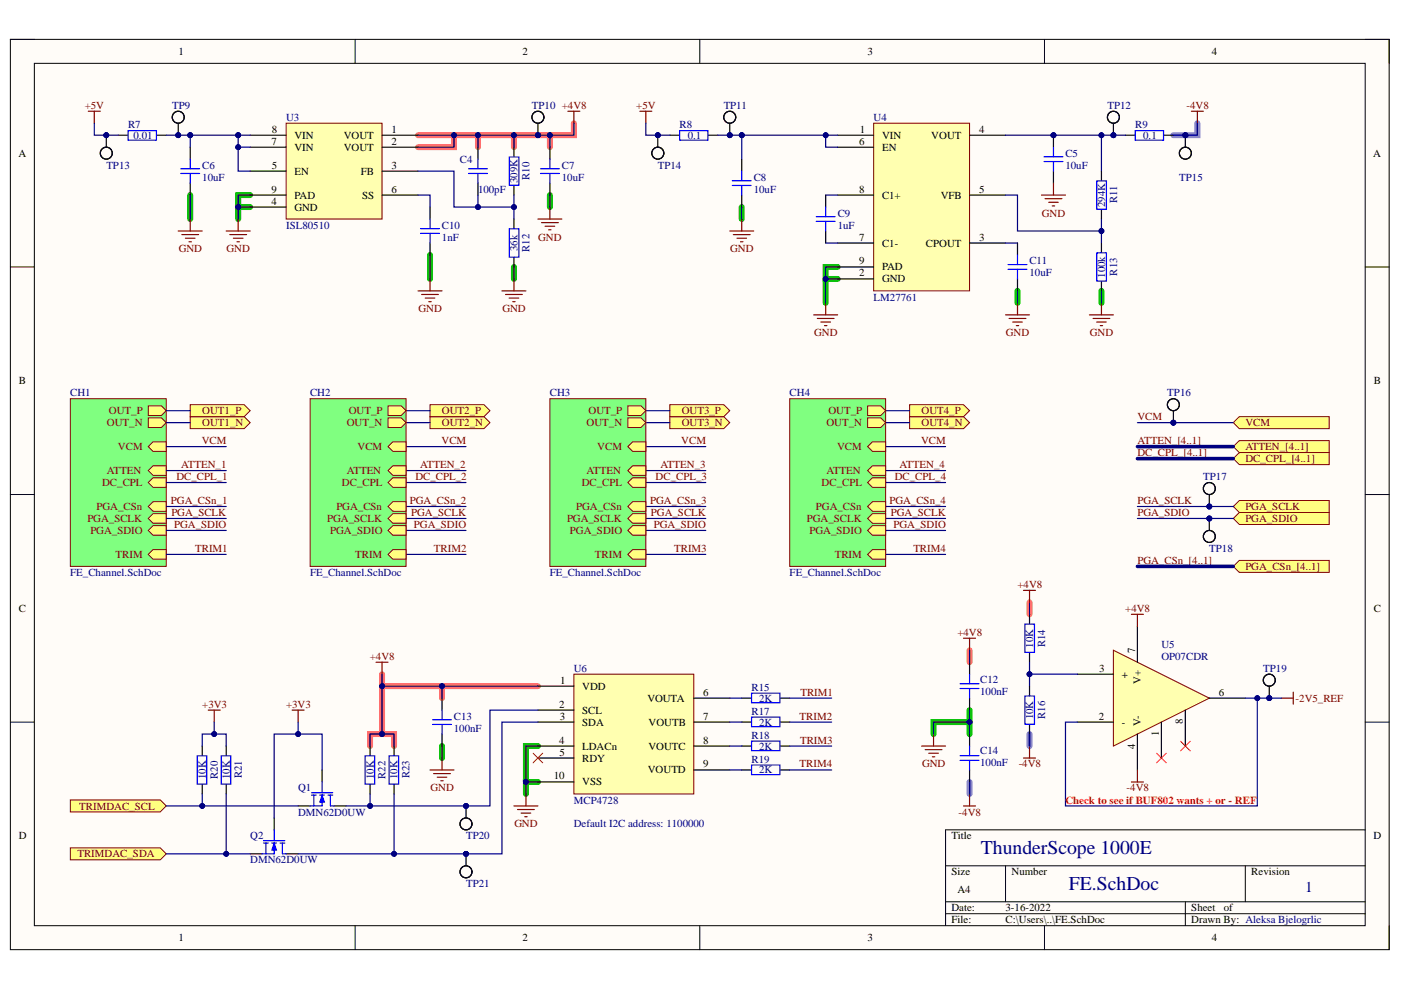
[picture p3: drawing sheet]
<svg xmlns="http://www.w3.org/2000/svg" width="297mm" height="210mm" viewBox="0 0 297 210" stroke-linecap="round" stroke-linejoin="round" font-family="sans-serif">
<defs><g id="words">
<g font-size="4.1" fill="#000080">
<text x="208" y="181.2">ThunderScope 1000E</text>
<text x="226.6" y="188.8">FE.SchDoc</text>
</g>
<text font-size="3.2" fill="#000080" x="276.7" y="189.2">1</text>
<g font-size="2.3">
<text x="37.9" y="11.7">1</text>
<text x="110.8" y="11.7">2</text>
<text x="184" y="11.7">3</text>
<text x="256.9" y="11.7">4</text>
<text x="57.6" y="28.1">8</text>
<text x="62.4" y="29.4">VIN</text>
<text x="72.9" y="29.4">VOUT</text>
<text x="83" y="28.1">1</text>
<text x="182.3" y="28.1">1</text>
<text x="187" y="29.4">VIN</text>
<text x="197.5" y="29.4">VOUT</text>
<text x="207.6" y="28.1">4</text>
<text x="3.9" y="33.2">A</text>
<text x="57.6" y="30.7">7</text>
<text x="57.7" y="35.8">5</text>
<text x="62.4" y="31.9">VIN</text>
<text x="72.9" y="31.9">VOUT</text>
<text x="83" y="30.7">2</text>
<text x="83" y="35.8">3</text>
<text x="182.1" y="30.7">6</text>
<text x="187" y="31.9">EN</text>
<text x="291.1" y="33.2">A</text>
<text x="57.6" y="40.9">9</text>
<text x="62.4" y="37.1">EN</text>
<text x="76.5" y="37.1">FB</text>
<text x="83" y="40.9">6</text>
<text x="182.2" y="40.9">8</text>
<text x="207.6" y="40.9">5</text>
<text x="57.6" y="43.4">4</text>
<text x="62.4" y="44.7">GND</text>
<text x="62.4" y="42.1">PAD</text>
<text x="76.8" y="42.1">SS</text>
<text x="187" y="42.1">C1+</text>
<text x="199.4" y="42.1">VFB</text>
<text x="182.1" y="51">7</text>
<text x="187" y="52.3">C1-</text>
<text x="196.3" y="52.3">CPOUT</text>
<text x="207.6" y="51">3</text>
<text x="182.1" y="58.6">2</text>
<text x="182.1" y="56.1">9</text>
<text x="187" y="59.9">GND</text>
<text x="187" y="57.3">PAD</text>
<text x="4" y="81.5">B</text>
<text x="291.3" y="81.5">B</text>
<text x="4" y="129.7">C</text>
<text x="291.3" y="129.7">C</text>
<text x="233.1" y="142.4">3</text>
<text x="237.9" y="143.7">+</text>
<text x="240.6" y="138.4" transform="rotate(-90 240.6 138.4)">7</text>
<text x="118.8" y="145">1</text>
<text x="123.4" y="146.2">VDD</text>
<text x="137.3" y="148.8">VOUTA</text>
<text x="149.1" y="147.5">6</text>
<text x="241.9" y="145.1" transform="rotate(-90 241.9 145.1)">V+</text>
<text x="258.4" y="147.5">6</text>
<text x="118.6" y="150">2</text>
<text x="118.7" y="152.6">3</text>
<text x="123.4" y="151.3">SCL</text>
<text x="123.4" y="153.9">SDA</text>
<text x="137.5" y="153.9">VOUTB</text>
<text x="149.1" y="152.6">7</text>
<text x="233" y="152.6">2</text>
<text x="237.9" y="153.9">-</text>
<text x="241.9" y="153.9" transform="rotate(-90 241.9 153.9)">V-</text>
<text x="250.8" y="153.6" transform="rotate(-90 250.8 153.6)">8</text>
<text x="118.6" y="157.7">4</text>
<text x="118.7" y="160.2">5</text>
<text x="123.4" y="158.9">LDACn</text>
<text x="123.4" y="161.5">RDY</text>
<text x="137.5" y="158.9">VOUTC</text>
<text x="149.1" y="157.7">8</text>
<text x="240.6" y="158.8" transform="rotate(-90 240.6 158.8)">4</text>
<text x="245.7" y="156" transform="rotate(-90 245.7 156)">1</text>
<text x="117.4" y="165.3">10</text>
<text x="123.4" y="166.5">VSS</text>
<text x="137.3" y="164">VOUTD</text>
<text x="149.1" y="162.7">9</text>
<text x="4" y="178">D</text>
<text x="201.7" y="178">Title</text>
<text x="291.2" y="178">D</text>
<text x="201.7" y="185.6">Size</text>
<text x="214.5" y="185.6">Number</text>
<text x="265.3" y="185.6">Revision</text>
<text x="203" y="189.4">A4</text>
<text x="201.7" y="193.2">Date:</text>
<text x="201.7" y="195.7">File:</text>
<text x="213.2" y="193.2">3-16-2022</text>
<text x="213.2" y="195.7">C:\Users\..\FE.SchDoc</text>
<text x="252.6" y="193.2">Sheet</text>
<text x="252.6" y="195.7">Drawn By: Aleksa Bjelogrlic</text>
<text x="259.5" y="193.2">of</text>
<text x="37.9" y="199.6">1</text>
<text x="110.8" y="199.6">2</text>
<text x="184" y="199.6">3</text>
<text x="256.9" y="199.6">4</text>
</g>
<g font-size="2.3" fill="#800000">
<text x="18" y="23.1">+5V</text>
<text x="134.9" y="23.1">+5V</text>
<text x="251.6" y="23.1">-4V8</text>
<text x="220.9" y="45.9">GND</text>
<text x="37.9" y="53.5">GND</text>
<text x="48.1" y="53.5">GND</text>
<text x="114.1" y="51">GND</text>
<text x="154.8" y="53.5">GND</text>
<text x="88.7" y="66.3">GND</text>
<text x="106.5" y="66.3">GND</text>
<text x="172.6" y="71.3">GND</text>
<text x="213.3" y="71.3">GND</text>
<text x="231.1" y="71.3">GND</text>
<text x="23.1" y="87.8">OUT_P</text>
<text x="42.9" y="87.8">OUT1_P</text>
<text x="73.9" y="87.8">OUT_P</text>
<text x="93.7" y="87.8">OUT2_P</text>
<text x="124.8" y="87.8">OUT_P</text>
<text x="144.5" y="87.8">OUT3_P</text>
<text x="175.6" y="87.8">OUT_P</text>
<text x="195.4" y="87.8">OUT4_P</text>
<text x="241.2" y="89.1">VCM</text>
<text x="22.7" y="90.4">OUT_N</text>
<text x="25" y="95.5">VCM</text>
<text x="42.8" y="94.2">VCM</text>
<text x="42.9" y="90.4">OUT1_N</text>
<text x="73.5" y="90.4">OUT_N</text>
<text x="75.8" y="95.5">VCM</text>
<text x="93.6" y="94.2">VCM</text>
<text x="93.7" y="90.4">OUT2_N</text>
<text x="124.4" y="90.4">OUT_N</text>
<text x="126.6" y="95.5">VCM</text>
<text x="144.5" y="94.2">VCM</text>
<text x="144.5" y="90.4">OUT3_N</text>
<text x="175.2" y="90.4">OUT_N</text>
<text x="177.5" y="95.5">VCM</text>
<text x="195.3" y="94.2">VCM</text>
<text x="195.4" y="90.4">OUT4_N</text>
<text x="241.2" y="94.2">ATTEN_[4..1]</text>
<text x="264" y="95.5">ATTEN_[4..1]</text>
<text x="264" y="90.4">VCM</text>
<text x="22.7" y="100.5">ATTEN</text>
<text x="37.4" y="101.8">DC_CPL_1</text>
<text x="38.4" y="99.3">ATTEN_1</text>
<text x="73.5" y="100.5">ATTEN</text>
<text x="88.1" y="101.8">DC_CPL_2</text>
<text x="89.1" y="99.3">ATTEN_2</text>
<text x="124.4" y="100.5">ATTEN</text>
<text x="139" y="101.8">DC_CPL_3</text>
<text x="140" y="99.3">ATTEN_3</text>
<text x="175.2" y="100.5">ATTEN</text>
<text x="189.7" y="101.8">DC_CPL_4</text>
<text x="190.7" y="99.3">ATTEN_4</text>
<text x="241.2" y="96.7">DC_CPL_[4..1]</text>
<text x="264" y="98">DC_CPL_[4..1]</text>
<text x="21.7" y="103.1">DC_CPL</text>
<text x="36.3" y="106.9">PGA_CSn_1</text>
<text x="72.5" y="103.1">DC_CPL</text>
<text x="86.9" y="106.9">PGA_CSn_2</text>
<text x="123.3" y="103.1">DC_CPL</text>
<text x="137.9" y="106.9">PGA_CSn_3</text>
<text x="174.2" y="103.1">DC_CPL</text>
<text x="188.6" y="106.9">PGA_CSn_4</text>
<text x="241.2" y="106.9">PGA_SCLK</text>
<text x="18.5" y="110.7">PGA_SCLK</text>
<text x="19.2" y="113.2">PGA_SDIO</text>
<text x="20.5" y="108.1">PGA_CSn</text>
<text x="36.3" y="109.4">PGA_SCLK</text>
<text x="36.9" y="111.9">PGA_SDIO</text>
<text x="69.4" y="110.7">PGA_SCLK</text>
<text x="70" y="113.2">PGA_SDIO</text>
<text x="71.3" y="108.1">PGA_CSn</text>
<text x="87.2" y="109.4">PGA_SCLK</text>
<text x="87.8" y="111.9">PGA_SDIO</text>
<text x="120.2" y="110.7">PGA_SCLK</text>
<text x="120.9" y="113.2">PGA_SDIO</text>
<text x="122.2" y="108.1">PGA_CSn</text>
<text x="138" y="109.4">PGA_SCLK</text>
<text x="138.6" y="111.9">PGA_SDIO</text>
<text x="171.1" y="110.7">PGA_SCLK</text>
<text x="171.7" y="113.2">PGA_SDIO</text>
<text x="173" y="108.1">PGA_CSn</text>
<text x="188.9" y="109.4">PGA_SCLK</text>
<text x="189.5" y="111.9">PGA_SDIO</text>
<text x="241.2" y="109.4">PGA_SDIO</text>
<text x="264" y="108.1">PGA_SCLK</text>
<text x="264" y="110.7">PGA_SDIO</text>
<text x="24.5" y="118.3">TRIM</text>
<text x="41.4" y="117">TRIM1</text>
<text x="75.3" y="118.3">TRIM</text>
<text x="92" y="117">TRIM2</text>
<text x="126.1" y="118.3">TRIM</text>
<text x="142.9" y="117">TRIM3</text>
<text x="177" y="118.3">TRIM</text>
<text x="193.6" y="117">TRIM4</text>
<text x="241.2" y="119.6">PGA_CSn_[4..1]</text>
<text x="215.7" y="124.7">+4V8</text>
<text x="264" y="120.8">PGA_CSn_[4..1]</text>
<text x="238.6" y="129.7">+4V8</text>
<text x="203" y="134.8">+4V8</text>
<text x="78.4" y="139.9">+4V8</text>
<text x="169.7" y="147.5">TRIM1</text>
<text x="274.7" y="148.8">-2V5_REF</text>
<text x="42.9" y="150">+3V3</text>
<text x="60.7" y="150">+3V3</text>
<text x="169.5" y="152.6">TRIM2</text>
<text x="169.6" y="157.7">TRIM3</text>
<text x="91.3" y="167.8">GND</text>
<text x="169.5" y="162.7">TRIM4</text>
<text x="195.5" y="162.7">GND</text>
<text x="216" y="162.7">-4V8</text>
<text x="238.9" y="167.8">-4V8</text>
<text x="16.8" y="171.6">TRIMDAC_SCL</text>
<text x="203.3" y="172.9">-4V8</text>
<text x="109" y="175.4">GND</text>
<text x="16.4" y="181.8">TRIMDAC_SDA</text>
</g>
<g font-size="2.3" fill="#000080">
<text x="36.5" y="23.1">TP9</text>
<text x="112.8" y="23.1">TP10 +4V8</text>
<text x="153.5" y="23.1">TP11</text>
<text x="234.8" y="23.1">TP12</text>
<text x="27.2" y="27.2">R7</text>
<text x="28.3" y="29.4">0.01</text>
<text x="60.7" y="25.6">U3</text>
<text x="144.1" y="27.2">R8</text>
<text x="145.8" y="29.4">0.1</text>
<text x="185.2" y="25.6">U4</text>
<text x="240.7" y="27.2">R9</text>
<text x="242.4" y="29.4">0.1</text>
<text x="22.5" y="35.8">TP13</text>
<text x="42.9" y="35.8">C6</text>
<text x="97.5" y="34.5">C4</text>
<text x="119.1" y="35.8">C7</text>
<text x="139.5" y="35.8">TP14</text>
<text x="225.9" y="33.2">C5</text>
<text x="225.9" y="35.8">10uF</text>
<text x="42.9" y="38.3">10uF</text>
<text x="101.4" y="40.9">100pF</text>
<text x="109.7" y="38.8" transform="rotate(-90 109.7 38.8)">309K</text>
<text x="112.3" y="38.2" transform="rotate(-90 112.3 38.2)">R10</text>
<text x="119.1" y="38.3">10uF</text>
<text x="159.8" y="38.3">C8</text>
<text x="159.8" y="40.9">10uF</text>
<text x="250" y="38.3">TP15</text>
<text x="177.6" y="45.9">C9</text>
<text x="234.3" y="43.9" transform="rotate(-90 234.3 43.9)">294K</text>
<text x="236.8" y="43.1" transform="rotate(-90 236.8 43.1)">R11</text>
<text x="60.7" y="48.5">ISL80510</text>
<text x="93.7" y="48.5">C10</text>
<text x="93.7" y="51">1nF</text>
<text x="109.7" y="53.2" transform="rotate(-90 109.7 53.2)">36k</text>
<text x="112.3" y="53.4" transform="rotate(-90 112.3 53.4)">R12</text>
<text x="177.6" y="48.5">1uF</text>
<text x="218.3" y="56.1">C11</text>
<text x="218.3" y="58.6">10uF</text>
<text x="234.3" y="58.9" transform="rotate(-90 234.3 58.9)">100k</text>
<text x="236.8" y="58.4" transform="rotate(-90 236.8 58.4)">R13</text>
<text x="185.2" y="63.7">LM27761</text>
<text x="14.9" y="84">CH1</text>
<text x="65.7" y="84">CH2</text>
<text x="116.6" y="84">CH3</text>
<text x="167.4" y="84">CH4</text>
<text x="247.5" y="84">TP16</text>
<text x="255.1" y="101.8">TP17</text>
<text x="256.4" y="117">TP18</text>
<text x="14.9" y="122.1">FE_Channel.SchDoc</text>
<text x="65.7" y="122.1">FE_Channel.SchDoc</text>
<text x="116.6" y="122.1">FE_Channel.SchDoc</text>
<text x="167.4" y="122.1">FE_Channel.SchDoc</text>
<text x="219" y="137.3" transform="rotate(-90 219 137.3)">10K</text>
<text x="221.6" y="137.2" transform="rotate(-90 221.6 137.2)">R14</text>
<text x="246.2" y="137.3">U5</text>
<text x="121.7" y="142.4">U6</text>
<text x="246.2" y="139.9">OP07CDR</text>
<text x="267.8" y="142.4">TP19</text>
<text x="159.3" y="146.5">R15</text>
<text x="161" y="148.8">2K</text>
<text x="207.8" y="144.7">C12</text>
<text x="207.8" y="147.3">100nF</text>
<text x="96.2" y="152.6">C13</text>
<text x="96.2" y="155.1">100nF</text>
<text x="159.3" y="151.5">R17</text>
<text x="161" y="153.9">2K</text>
<text x="219" y="152.5" transform="rotate(-90 219 152.5)">10K</text>
<text x="221.6" y="152.4" transform="rotate(-90 221.6 152.4)">R16</text>
<text x="159.3" y="156.6">R18</text>
<text x="159.3" y="161.7">R19</text>
<text x="161" y="158.9">2K</text>
<text x="207.8" y="159.9">C14</text>
<text x="43.7" y="165.2" transform="rotate(-90 43.7 165.2)">10K</text>
<text x="46.2" y="165.1" transform="rotate(-90 46.2 165.1)">R20</text>
<text x="48.7" y="165.2" transform="rotate(-90 48.7 165.2)">10K</text>
<text x="51.3" y="165" transform="rotate(-90 51.3 165)">R21</text>
<text x="63.2" y="167.8">Q1</text>
<text x="79.2" y="165.2" transform="rotate(-90 79.2 165.2)">10K</text>
<text x="81.8" y="165.1" transform="rotate(-90 81.8 165.1)">R22</text>
<text x="84.3" y="165.2" transform="rotate(-90 84.3 165.2)">10K</text>
<text x="86.8" y="165.1" transform="rotate(-90 86.8 165.1)">R23</text>
<text x="161" y="164">2K</text>
<text x="207.8" y="162.5">100nF</text>
<text x="63.2" y="172.9">DMN62D0UW</text>
<text x="121.7" y="170.4">MCP4728</text>
<text x="53" y="178">Q2</text>
<text x="98.8" y="178">TP20</text>
<text x="121.7" y="175.4">Default I2C address: 1100000</text>
<text x="53" y="183.1">DMN62D0UW</text>
<text x="98.8" y="188.1">TP21</text>
</g>
<text font-size="2.3" fill="#f00" x="225.9" y="170.4">Check to see if BUF802 wants + or - REF</text>
</g></defs>
<path d="M2.2 8.3h292.3v193.1h-292.3z" fill-rule="evenodd" fill="#fffcf8"/>
<path d="M2.2 8.3h292.3v193.1h-292.3z" fill="none" stroke="#000" stroke-width=".21"/>
<path d="M7.3 13.4h282.1v182.9h-282.1z" fill-rule="evenodd" fill="#fffcf8"/>
<g fill="none" stroke="#000" stroke-width=".21">
<path d="M2.2 8.3h5.1M7.3 13.4h282.1v182.9h-282.1zM75.3 8.3v5.1M148.4 8.3v5.1M221.5 8.3v5.1M289.4 8.3h5.1v5.1M2.2 56.6h5.1M289.4 56.6h5.1M2.2 104.8h5.1M289.4 104.9h5.1M2.2 153.1h5.1M289.4 153.1h5.1"/>
<path d="M289.4 176h-88.9v20.3M75.3 196.3v5.1M148.4 196.3v5.1M200.5 183.6h88.9M200.5 191.2h88.9M200.5 193.7h88.9M213.2 183.6v7.6M221.5 196.3v5.1M251.3 191.2v5.1M264 183.6v7.6M294.5 196.3v5.1"/>
</g>
<path d="M88.6 28.7h7.7v2.5h-7.7M96.3 28.7h20.3v2.5M101.3 28.7v2.5M109 28.7v2.5M121.7 26.1v2.6h-5.1M205.6 137.9v2.5M218.3 127.7v2.6M81 155.6h-2.5v2.6M81 142.9v12.7h2.5v2.6M81 145.5h33.1M93.7 145.5v2.5" fill="none" stroke="#ff6e6e" stroke-width="1.3"/>
<g fill="none" stroke="#00be00" stroke-width="1.3">
<path d="M40.3 41.4v5M50.5 43.9h2.5M53 41.4h-2.5v5M91.2 54.1v5M109 56.6v2.5M116.6 41.4v2.5M157.3 43.9v2.5M175.1 59.1v5.1M177.6 56.6h-2.5v2.5h2.5M215.7 61.7v2.5M233.5 61.7v2.5M93.7 158.2v2.5"/>
<path d="M114.1 158.2h-2.6v7.6M205.6 150.6v5M205.6 153.1h-7.7v2.5M114.1 165.8h-2.6v2.5"/>
</g>
<path d="M253.9 26.1v2.6h-5.1M218.3 155.6v2.6M205.6 165.8v2.5" fill="none" stroke="#6e6eff" stroke-width="1.3"/>
<path d="M14.9 84.5h20.3v35.6h-20.3z" fill-rule="evenodd" fill="#80ff80"/>
<path d="M14.9 84.5h20.3v35.6h-20.3z" fill="none" stroke="#800000" stroke-width=".21"/>
<path d="M31.4 86.1h2.8l1 1-1 1h-2.8z" fill-rule="evenodd" fill="#ffff80"/>
<path d="M31.4 86.1h2.8l1 1-1 1h-2.8z" fill="none" stroke="#800000" stroke-width=".21"/>
<path d="M31.4 94.7l1-1h2.8v2h-2.8z" fill-rule="evenodd" fill="#ffff80"/>
<path d="M31.4 94.7l1-1h2.8v2h-2.8z" fill="none" stroke="#800000" stroke-width=".21"/>
<path d="M31.4 88.6h2.8l1 1-1 1h-2.8z" fill-rule="evenodd" fill="#ffff80"/>
<path d="M31.4 88.6h2.8l1 1-1 1h-2.8z" fill="none" stroke="#800000" stroke-width=".21"/>
<path d="M32.4 116.5h2.8v2.1h-2.8l-1-1.1z" fill-rule="evenodd" fill="#ffff80"/>
<path d="M32.4 116.5h2.8v2.1h-2.8l-1-1.1z" fill="none" stroke="#800000" stroke-width=".21"/>
<path d="M32.4 98.8h2.8v2h-2.8l-1-1z" fill-rule="evenodd" fill="#ffff80"/>
<path d="M32.4 98.8h2.8v2h-2.8l-1-1z" fill="none" stroke="#800000" stroke-width=".21"/>
<path d="M31.4 102.3l1-1h2.8v2h-2.8z" fill-rule="evenodd" fill="#ffff80"/>
<path d="M31.4 102.3l1-1h2.8v2h-2.8z" fill="none" stroke="#800000" stroke-width=".21"/>
<path d="M32.4 106.4h2.8v2h-2.8l-1-1z" fill-rule="evenodd" fill="#ffff80"/>
<path d="M32.4 106.4h2.8v2h-2.8l-1-1z" fill="none" stroke="#800000" stroke-width=".21"/>
<path d="M32.4 108.9h2.8v2h-2.8l-1-1z" fill-rule="evenodd" fill="#ffff80"/>
<path d="M32.4 108.9h2.8v2h-2.8l-1-1z" fill="none" stroke="#800000" stroke-width=".21"/>
<path d="M31.4 112.5l1-1h2.8v2h-2.8z" fill-rule="evenodd" fill="#ffff80"/>
<path d="M31.4 112.5l1-1h2.8v2h-2.8z" fill="none" stroke="#800000" stroke-width=".21"/>
<path d="M93.7 148v2.6M93.7 155.6v2.6M157.3 148h2M165.4 148h2M63.2 170.9h2.5M68.3 163.3v2.5M70.8 170.9h2.6" fill="none" stroke="#000" stroke-width=".25"/>
<g fill="none" stroke="#00f" stroke-width=".25">
<path d="M91.7 153.6h4M91.7 152.6h4M93.7 150.6v2M93.7 153.6v2M159.3 147h6.1v2h-6.1zM66 168.1h4.5M66 168.6h1M66.5 168.6v2.3M67.8 168.6h1M68.3 165.8v2.3M68.3 168.6v2.3h-2.6M69.5 168.6h1"/>
<path d="M70 168.6v2.3"/>
</g>
<path d="M91.2 163.3h5.1M91.9 164h3.6M92.7 164.8h2M93.5 165.5h.5M93.7 160.7v2.6M109 170.9h5.1M109.7 171.6h3.6M110.5 172.4h2M111.3 173.2h.5M111.5 168.3v2.6" fill="none" stroke="#800000" stroke-width=".25"/>
<path d="M68.3 168.6l.5 1.5h-1z" fill="#00f"/>
<path d="M68.3 168.6l.5 1.5h-1z" fill="none" stroke="#00f" stroke-width=".21"/>
<path d="M55.9 178.2h4.5M55.9 178.7h1M56.4 178.7v2.3M57.6 178.7h1M58.1 176v2.2M58.1 178.7v2.3h-2.5M59.4 178.7h1M59.9 178.7v2.3M70.1 170.9h.7" fill="none" stroke="#00f" stroke-width=".25"/>
<path d="M58.1 173.4v2.6M53 181h2.6M60.7 181h2.5" fill="none" stroke="#000" stroke-width=".25"/>
<path d="M58.1 178.7l.5 1.5h-1z" fill="#00f"/>
<path d="M58.1 178.7l.5 1.5h-1z" fill="none" stroke="#00f" stroke-width=".21"/>
<path d="M41.8 160.3h2v6h-2zM46.9 160.3h2v6h-2zM77.4 160.3h2v6h-2zM82.5 160.3h2v6h-2zM59.9 181h.8" fill="none" stroke="#00f" stroke-width=".25"/>
<path d="M42.9 158.2v2M48 158.2v2M78.5 158.2v2M83.5 158.2v2M42.9 166.3v2M48 166.3v2M78.5 166.3v2M83.5 166.3v2" fill="none" stroke="#000" stroke-width=".25"/>
<path d="M44.1 150.6h2.6M45.4 150.6v2.5M61.9 150.6h2.6M63.2 150.6v2.5" fill="none" stroke="#800000" stroke-width=".25"/>
<path d="M14.9 169.6h19.1l1.2 1.3-1.2 1.2h-19.1z" fill-rule="evenodd" fill="#ffff80"/>
<path d="M14.9 169.6h19.1l1.2 1.3-1.2 1.2h-19.1z" fill="none" stroke="#800000" stroke-width=".21"/>
<path d="M14.9 179.8h19.1l1.2 1.2-1.2 1.3h-19.1z" fill-rule="evenodd" fill="#ffff80"/>
<path d="M14.9 179.8h19.1l1.2 1.2-1.2 1.3h-19.1z" fill="none" stroke="#800000" stroke-width=".21"/>
<path d="M236.1 137.9l20.3 10.1-20.3 10.2z" fill="#ffffb0"/>
<path d="M236.1 137.9l20.3 10.1-20.3 10.2z" fill="none" stroke="#800000" stroke-width=".21"/>
<path d="M218.3 130.3v1.9M218.3 138.4v2M241.2 132.8v7.6M218.3 145.5v2M218.3 153.6v2M228.4 142.9h7.7M228.4 153.1h7.7M241.2 155.6v7.7M246.2 153.1v7.6M251.3 150.6v7.6M256.4 148h7.6" fill="none" stroke="#000" stroke-width=".25"/>
<path d="M245.2 159.7l2.1 2M247.3 159.7l-2.1 2M250.3 157.2l2 2M252.3 157.2l-2 2" fill="none" stroke="#f00" stroke-width=".21"/>
<path d="M217.3 132.3h2v6h-2zM217.3 147.6h2v6h-2z" fill="none" stroke="#00f" stroke-width=".25"/>
<path d="M271.6 148h2.6M274.2 146.8v2.5" fill="none" stroke="#800000" stroke-width=".25"/>
<path d="M121.7 142.9h25.4v25.4h-25.4z" fill-rule="evenodd" fill="#ffffb0"/>
<path d="M121.7 142.9h25.4v25.4h-25.4z" fill="none" stroke="#800000" stroke-width=".21"/>
<g fill="none" stroke="#000" stroke-width=".25">
<path d="M114.1 145.5h7.6M114.1 150.6h7.6M114.1 153.1h7.6M114.1 158.2h7.6M147.1 153.1h7.6M147.1 158.2h7.6M147.1 148h7.6M157.3 153.1h2M157.3 158.2h2M165.4 153.1h2M165.4 158.2h2M114.1 160.7h7.6"/>
<path d="M114.1 165.8h7.6M147.1 163.3h7.6M157.3 163.3h2M165.4 163.3h2"/>
</g>
<path d="M159.3 152h6.1v2.1h-6.1zM159.3 157.1h6.1v2.1h-6.1zM159.3 162.2h6.1v2h-6.1z" fill="none" stroke="#00f" stroke-width=".25"/>
<path d="M113 159.7l2.1 2M115.1 159.7l-2.1 2" fill="none" stroke="#f00" stroke-width=".21"/>
<path d="M261.5 94.7l1.3-1.3h19v2.6h-19z" fill-rule="evenodd" fill="#ffff80"/>
<path d="M261.5 94.7l1.3-1.3h19v2.6h-19z" fill="none" stroke="#800000" stroke-width=".21"/>
<path d="M262.8 96h19v2.5h-19l-1.3-1.3z" fill-rule="evenodd" fill="#ffff80"/>
<path d="M262.8 96h19v2.5h-19l-1.3-1.3z" fill="none" stroke="#800000" stroke-width=".21"/>
<path d="M261.5 107.4l1.3-1.3h19v2.6h-19z" fill-rule="evenodd" fill="#ffff80"/>
<path d="M261.5 107.4l1.3-1.3h19v2.6h-19z" fill="none" stroke="#800000" stroke-width=".21"/>
<path d="M261.5 109.9l1.3-1.2h19v2.5h-19z" fill-rule="evenodd" fill="#ffff80"/>
<path d="M261.5 109.9l1.3-1.2h19v2.5h-19z" fill="none" stroke="#800000" stroke-width=".21"/>
<path d="M261.5 120.1l1.3-1.3h19v2.6h-19z" fill-rule="evenodd" fill="#ffff80"/>
<path d="M261.5 120.1l1.3-1.3h19v2.6h-19z" fill="none" stroke="#800000" stroke-width=".21"/>
<path d="M261.5 89.6l1.3-1.3h19v2.6h-19z" fill-rule="evenodd" fill="#ffff80"/>
<path d="M261.5 89.6l1.3-1.3h19v2.6h-19z" fill="none" stroke="#800000" stroke-width=".21"/>
<path d="M40.3 88.3h11.5l1.2 1.3-1.2 1.3h-11.5z" fill-rule="evenodd" fill="#ffff80"/>
<path d="M40.3 88.3h11.5l1.2 1.3-1.2 1.3h-11.5z" fill="none" stroke="#800000" stroke-width=".21"/>
<path d="M40.3 85.8h11.5l1.2 1.3-1.2 1.2h-11.5z" fill-rule="evenodd" fill="#ffff80"/>
<path d="M40.3 85.8h11.5l1.2 1.3-1.2 1.2h-11.5z" fill="none" stroke="#800000" stroke-width=".21"/>
<path d="M91.2 88.3h11.4l1.3 1.3-1.3 1.3h-11.4z" fill-rule="evenodd" fill="#ffff80"/>
<path d="M91.2 88.3h11.4l1.3 1.3-1.3 1.3h-11.4z" fill="none" stroke="#800000" stroke-width=".21"/>
<path d="M91.2 85.8h11.4l1.3 1.3-1.3 1.2h-11.4z" fill-rule="evenodd" fill="#ffff80"/>
<path d="M91.2 85.8h11.4l1.3 1.3-1.3 1.2h-11.4z" fill="none" stroke="#800000" stroke-width=".21"/>
<path d="M142 88.3h11.4l1.3 1.3-1.3 1.3h-11.4z" fill-rule="evenodd" fill="#ffff80"/>
<path d="M142 88.3h11.4l1.3 1.3-1.3 1.3h-11.4z" fill="none" stroke="#800000" stroke-width=".21"/>
<path d="M142 85.8h11.4l1.3 1.3-1.3 1.2h-11.4z" fill-rule="evenodd" fill="#ffff80"/>
<path d="M142 85.8h11.4l1.3 1.3-1.3 1.2h-11.4z" fill="none" stroke="#800000" stroke-width=".21"/>
<path d="M192.9 88.3h11.4l1.3 1.3-1.3 1.3h-11.4z" fill-rule="evenodd" fill="#ffff80"/>
<path d="M192.9 88.3h11.4l1.3 1.3-1.3 1.3h-11.4z" fill="none" stroke="#800000" stroke-width=".21"/>
<path d="M192.9 85.8h11.4l1.3 1.3-1.3 1.2h-11.4z" fill-rule="evenodd" fill="#ffff80"/>
<path d="M192.9 85.8h11.4l1.3 1.3-1.3 1.2h-11.4z" fill="none" stroke="#800000" stroke-width=".21"/>
<path d="M185.2 26.1h20.4v35.6h-20.4z" fill-rule="evenodd" fill="#ffffb0"/>
<path d="M185.2 26.1h20.4v35.6h-20.4z" fill="none" stroke="#800000" stroke-width=".21"/>
<g fill="none" stroke="#000" stroke-width=".25">
<path d="M157.3 33.7v2.6M177.6 28.7h7.6M177.6 31.2h7.6M205.6 28.7h7.6M233.5 36.3v2M157.3 41.4v2.5M175.1 41.4v2.5M175.1 49v2.5M177.6 59.1h7.6M177.6 51.5h7.6M177.6 41.4h7.6M177.6 56.6h7.6"/>
<path d="M205.6 51.5h7.6M205.6 41.4h7.6M215.7 51.5v2.6M215.7 59.1v2.6M233.5 44.4v2M233.5 51.5v2M233.5 59.7v2"/>
</g>
<g fill="none" stroke="#00f" stroke-width=".25">
<path d="M155.3 39.3h4M155.3 38.3h4M157.3 36.3v2M157.3 39.3v2.1M232.5 38.4h2.1v6h-2.1zM173.1 46.9h4M173.1 45.9h4M175.1 43.9v2M175.1 46.9v2.1M213.7 57.1h4M213.7 56.1h4M215.7 54.1v2"/>
<path d="M215.7 57.1v2M232.5 53.6h2.1v6h-2.1z"/>
</g>
<g fill="none" stroke="#800000" stroke-width=".25">
<path d="M135.7 23.6h2.5M136.9 23.6v2.5M154.7 49h5.1M155.5 49.7h3.5M156.2 50.5h2.1M157 51.3h.5M157.3 46.4v2.6M172.5 66.8h5.1M173.3 67.5h3.5M174 68.3h2.1M174.8 69h.5M175.1 64.2v2.6"/>
<path d="M213.2 66.8h5.1M214 67.5h3.5M214.7 68.3h2M215.5 69h.5M215.7 64.2v2.6M231 66.8h5.1M231.8 67.5h3.5M232.5 68.3h2M233.3 69h.5M233.5 64.2v2.6"/>
</g>
<circle cx="223.4" cy="28.7" r=".51" fill="#000080"/>
<circle cx="223.4" cy="28.7" r=".51" fill="none" stroke="#000080" stroke-width=".21"/>
<path d="M223.4 28.7v2.5M223.4 36.3v2.5" fill="none" stroke="#000" stroke-width=".25"/>
<circle cx="223.4" cy="28.7" r=".51" fill="#000080"/>
<circle cx="223.4" cy="28.7" r=".51" fill="none" stroke="#000080" stroke-width=".21"/>
<path d="M221.4 34.3h4M221.4 33.2h4M223.4 31.2v2M223.4 34.3v2M240.7 27.7h6v2h-6z" fill="none" stroke="#00f" stroke-width=".25"/>
<path d="M223.4 38.8v2.6M252.6 23.6h2.5M253.9 23.6v2.5M220.8 41.4h5.1M221.6 42.1h3.5M222.3 42.9h2.1M223.1 43.7h.5" fill="none" stroke="#800000" stroke-width=".25"/>
<path d="M238.6 28.7h2M246.8 28.7h2" fill="none" stroke="#000" stroke-width=".25"/>
<path d="M60.7 26.1h20.3v20.3h-20.3z" fill-rule="evenodd" fill="#ffffb0"/>
<path d="M60.7 26.1h20.3v20.3h-20.3z" fill="none" stroke="#800000" stroke-width=".21"/>
<g fill="none" stroke="#000" stroke-width=".25">
<path d="M25.1 28.7h2M33.2 28.7h2M40.3 31.2v2.5M40.3 38.8v2.6M53 28.7h7.7M53 31.2h7.7M53 36.3h7.7M81 28.7h7.6M81 31.2h7.6M81 36.3h7.6M101.3 31.2v2.5M101.3 38.8v2.6"/>
<path d="M109 31.2v2M109 39.4v2M116.6 31.2v2.5M116.6 38.8v2.6M142 28.7h2M150.2 28.7h2M53 43.9h7.7M53 41.4h7.7M81 41.4h7.6M91.2 43.9v2.5M91.2 51.5v2.6M109 46.4v2"/>
<path d="M109 54.6v2"/>
</g>
<g fill="none" stroke="#800000" stroke-width=".25">
<path d="M18.7 23.6h2.6M20 23.6v2.5M120.4 23.6h2.5M121.7 23.6v2.5M37.8 49h5.1M38.6 49.7h3.5M39.3 50.5h2M40.1 51.3h.5M40.3 46.4v2.6M48 49h5M48.7 49.7h3.6M49.5 50.5h2"/>
<path d="M50.2 51.3h.6M50.5 46.4v2.6M91.2 59.1v2.6M109 59.1v2.6M114.1 46.4h5M114.8 47.2h3.6M115.6 48h2M116.3 48.7h.5M116.6 43.9v2.5M88.6 61.7h5.1M89.4 62.4h3.5M90.2 63.2h2"/>
<path d="M90.9 64h.5M106.4 61.7h5.1M107.2 62.4h3.5M107.9 63.2h2.1M108.7 64h.5"/>
</g>
<g fill="none" stroke="#00f" stroke-width=".25">
<path d="M27.2 27.7h6v2h-6zM38.3 36.8h4M38.3 35.8h4M40.3 33.7v2.1M40.3 36.8v2M99.3 36.8h4M99.3 35.8h4M101.3 33.7v2.1M101.3 36.8v2M108 33.3h2v6h-2zM114.6 36.8h4M114.6 35.8h4"/>
<path d="M116.6 33.7v2.1M116.6 36.8v2M144.1 27.7h6v2h-6zM89.2 49.5h4M89.2 48.5h4M91.2 46.4v2.1M91.2 49.5v2M108 48.5h2v6h-2z"/>
</g>
<circle cx="22.5" cy="28.7" r=".51" fill="#000080"/>
<circle cx="22.5" cy="28.7" r=".51" fill="none" stroke="#000080" stroke-width=".21"/>
<path d="M22.5 28.7v2.5" fill="none" stroke="#000" stroke-width=".25"/>
<circle cx="22.5" cy="28.7" r=".51" fill="#000080"/>
<circle cx="22.5" cy="28.7" r=".51" fill="none" stroke="#000080" stroke-width=".21"/>
<circle cx="22.5" cy="32.5" r="1.27" fill="none" stroke="#000" stroke-width=".25"/>
<circle cx="37.8" cy="28.7" r=".51" fill="#000080"/>
<circle cx="37.8" cy="28.7" r=".51" fill="none" stroke="#000080" stroke-width=".21"/>
<path d="M37.8 26.1v2.6" fill="none" stroke="#000" stroke-width=".25"/>
<circle cx="37.8" cy="28.7" r=".51" fill="#000080"/>
<circle cx="37.8" cy="28.7" r=".51" fill="none" stroke="#000080" stroke-width=".21"/>
<circle cx="37.8" cy="24.9" r="1.27" fill="none" stroke="#000" stroke-width=".25"/>
<circle cx="139.5" cy="28.7" r=".51" fill="#000080"/>
<circle cx="139.5" cy="28.7" r=".51" fill="none" stroke="#000080" stroke-width=".21"/>
<path d="M139.5 28.7v2.5" fill="none" stroke="#000" stroke-width=".25"/>
<circle cx="139.5" cy="28.7" r=".51" fill="#000080"/>
<circle cx="139.5" cy="28.7" r=".51" fill="none" stroke="#000080" stroke-width=".21"/>
<circle cx="139.5" cy="32.5" r="1.27" fill="none" stroke="#000" stroke-width=".25"/>
<circle cx="154.7" cy="28.7" r=".51" fill="#000080"/>
<circle cx="154.7" cy="28.7" r=".51" fill="none" stroke="#000080" stroke-width=".21"/>
<path d="M154.7 26.1v2.6" fill="none" stroke="#000" stroke-width=".25"/>
<circle cx="154.7" cy="28.7" r=".51" fill="#000080"/>
<circle cx="154.7" cy="28.7" r=".51" fill="none" stroke="#000080" stroke-width=".21"/>
<circle cx="154.7" cy="24.9" r="1.27" fill="none" stroke="#000" stroke-width=".25"/>
<circle cx="236.1" cy="28.7" r=".51" fill="#000080"/>
<circle cx="236.1" cy="28.7" r=".51" fill="none" stroke="#000080" stroke-width=".21"/>
<path d="M236.1 26.1v2.6" fill="none" stroke="#000" stroke-width=".25"/>
<circle cx="236.1" cy="28.7" r=".51" fill="#000080"/>
<circle cx="236.1" cy="28.7" r=".51" fill="none" stroke="#000080" stroke-width=".21"/>
<circle cx="236.1" cy="24.9" r="1.27" fill="none" stroke="#000" stroke-width=".25"/>
<circle cx="251.3" cy="28.7" r=".51" fill="#000080"/>
<circle cx="251.3" cy="28.7" r=".51" fill="none" stroke="#000080" stroke-width=".21"/>
<path d="M251.3 28.7v2.5" fill="none" stroke="#000" stroke-width=".25"/>
<circle cx="251.3" cy="28.7" r=".51" fill="#000080"/>
<circle cx="251.3" cy="28.7" r=".51" fill="none" stroke="#000080" stroke-width=".21"/>
<circle cx="251.3" cy="32.5" r="1.27" fill="none" stroke="#000" stroke-width=".25"/>
<circle cx="269.1" cy="148" r=".51" fill="#000080"/>
<circle cx="269.1" cy="148" r=".51" fill="none" stroke="#000080" stroke-width=".21"/>
<path d="M269.1 145.5v2.5" fill="none" stroke="#000" stroke-width=".25"/>
<circle cx="269.1" cy="148" r=".51" fill="#000080"/>
<circle cx="269.1" cy="148" r=".51" fill="none" stroke="#000080" stroke-width=".21"/>
<circle cx="269.1" cy="144.2" r="1.27" fill="none" stroke="#000" stroke-width=".25"/>
<circle cx="248.8" cy="89.6" r=".51" fill="#000080"/>
<circle cx="248.8" cy="89.6" r=".51" fill="none" stroke="#000080" stroke-width=".21"/>
<path d="M248.8 87.1v2.5" fill="none" stroke="#000" stroke-width=".25"/>
<circle cx="248.8" cy="89.6" r=".51" fill="#000080"/>
<circle cx="248.8" cy="89.6" r=".51" fill="none" stroke="#000080" stroke-width=".21"/>
<circle cx="248.8" cy="85.8" r="1.27" fill="none" stroke="#000" stroke-width=".25"/>
<circle cx="256.4" cy="107.4" r=".51" fill="#000080"/>
<circle cx="256.4" cy="107.4" r=".51" fill="none" stroke="#000080" stroke-width=".21"/>
<path d="M256.4 104.9v2.5" fill="none" stroke="#000" stroke-width=".25"/>
<circle cx="256.4" cy="107.4" r=".51" fill="#000080"/>
<circle cx="256.4" cy="107.4" r=".51" fill="none" stroke="#000080" stroke-width=".21"/>
<circle cx="256.4" cy="103.6" r="1.27" fill="none" stroke="#000" stroke-width=".25"/>
<circle cx="256.4" cy="109.9" r=".51" fill="#000080"/>
<circle cx="256.4" cy="109.9" r=".51" fill="none" stroke="#000080" stroke-width=".21"/>
<path d="M256.4 109.9v2.6" fill="none" stroke="#000" stroke-width=".25"/>
<circle cx="256.4" cy="109.9" r=".51" fill="#000080"/>
<circle cx="256.4" cy="109.9" r=".51" fill="none" stroke="#000080" stroke-width=".21"/>
<circle cx="256.4" cy="113.7" r="1.27" fill="none" stroke="#000" stroke-width=".25"/>
<circle cx="98.8" cy="170.9" r=".51" fill="#000080"/>
<circle cx="98.8" cy="170.9" r=".51" fill="none" stroke="#000080" stroke-width=".21"/>
<path d="M98.8 170.9v2.5" fill="none" stroke="#000" stroke-width=".25"/>
<circle cx="98.8" cy="170.9" r=".51" fill="#000080"/>
<circle cx="98.8" cy="170.9" r=".51" fill="none" stroke="#000080" stroke-width=".21"/>
<circle cx="98.8" cy="174.7" r="1.27" fill="none" stroke="#000" stroke-width=".25"/>
<circle cx="98.8" cy="181" r=".51" fill="#000080"/>
<circle cx="98.8" cy="181" r=".51" fill="none" stroke="#000080" stroke-width=".21"/>
<path d="M98.8 181v2.6" fill="none" stroke="#000" stroke-width=".25"/>
<circle cx="98.8" cy="181" r=".51" fill="#000080"/>
<circle cx="98.8" cy="181" r=".51" fill="none" stroke="#000080" stroke-width=".21"/>
<circle cx="98.8" cy="184.8" r="1.27" fill="none" stroke="#000" stroke-width=".25"/>
<circle cx="114" cy="28.7" r=".51" fill="#000080"/>
<circle cx="114" cy="28.7" r=".51" fill="none" stroke="#000080" stroke-width=".21"/>
<path d="M114.1 26.1v2.6" fill="none" stroke="#000" stroke-width=".25"/>
<circle cx="114" cy="28.7" r=".51" fill="#000080"/>
<circle cx="114" cy="28.7" r=".51" fill="none" stroke="#000080" stroke-width=".21"/>
<g fill="none" stroke="#000" stroke-width=".25">
<path d="M205.6 140.4v2.5M205.6 148v2.6M205.6 155.6v2.6M205.6 163.3v2.5"/>
<circle cx="114" cy="24.9" r="1.27"/>
</g>
<path d="M203.6 145h4M203.6 146h4M205.6 142.9v2.1M205.6 146v2M205.6 158.2v2M203.6 160.2h4M203.6 161.2h4M205.6 161.2v2.1" fill="none" stroke="#00f" stroke-width=".25"/>
<g fill="none" stroke="#800000" stroke-width=".25">
<path d="M204.3 135.3h2.5M205.6 135.3v2.6M239.9 130.3h2.5M241.2 130.3v2.5M79.7 140.4h2.6M81 140.4v2.5M195.4 158.2h5.1M196.2 158.9h3.5M196.9 159.7h2.1M197.9 155.6v2.6M218.3 158.2v2.5M197.7 160.5h.5"/>
<path d="M204.3 170.9h2.5M205.6 168.3v2.6M217 160.7h2.5M239.9 165.8h2.5M241.2 163.3v2.5"/>
</g>
<path d="M218.3 127.7v2.6M45.4 155.6h-2.5v2.6" fill="none" stroke="#000080" stroke-width=".25"/>
<circle cx="45.4" cy="155.6" r=".51" fill="#000080"/>
<circle cx="45.4" cy="155.6" r=".51" fill="none" stroke="#000080" stroke-width=".21"/>
<path d="M45.4 153.1v2.5h2.6v2.6" fill="none" stroke="#000080" stroke-width=".25"/>
<circle cx="45.4" cy="155.6" r=".51" fill="#000080"/>
<circle cx="45.4" cy="155.6" r=".51" fill="none" stroke="#000080" stroke-width=".21"/>
<path d="M81 155.6h-2.5v2.6" fill="none" stroke="#000080" stroke-width=".25"/>
<circle cx="81" cy="155.6" r=".51" fill="#000080"/>
<circle cx="81" cy="155.6" r=".51" fill="none" stroke="#000080" stroke-width=".21"/>
<path d="M114.1 165.8h-2.6v2.5" fill="none" stroke="#000080" stroke-width=".25"/>
<circle cx="111.5" cy="165.8" r=".51" fill="#000080"/>
<circle cx="111.5" cy="165.8" r=".51" fill="none" stroke="#000080" stroke-width=".21"/>
<path d="M218.3 142.9h10.1" fill="none" stroke="#000080" stroke-width=".25"/>
<circle cx="218.3" cy="142.9" r=".51" fill="#000080"/>
<circle cx="218.3" cy="142.9" r=".51" fill="none" stroke="#000080" stroke-width=".21"/>
<path d="M264 148h2.6v22.9h-40.7v-17.8h2.5" fill="none" stroke="#000080" stroke-width=".25"/>
<circle cx="266.6" cy="148" r=".51" fill="#000080"/>
<circle cx="266.6" cy="148" r=".51" fill="none" stroke="#000080" stroke-width=".21"/>
<path d="M266.6 148h5" fill="none" stroke="#000080" stroke-width=".25"/>
<circle cx="266.6" cy="148" r=".51" fill="#000080"/>
<circle cx="266.6" cy="148" r=".51" fill="none" stroke="#000080" stroke-width=".21"/>
<circle cx="269.1" cy="148" r=".51" fill="#000080"/>
<circle cx="269.1" cy="148" r=".51" fill="none" stroke="#000080" stroke-width=".21"/>
<path d="M42.9 168.3v2.6" fill="none" stroke="#000080" stroke-width=".25"/>
<circle cx="42.9" cy="170.9" r=".51" fill="#000080"/>
<circle cx="42.9" cy="170.9" r=".51" fill="none" stroke="#000080" stroke-width=".21"/>
<path d="M48 168.3v12.7" fill="none" stroke="#000080" stroke-width=".25"/>
<circle cx="48" cy="181" r=".51" fill="#000080"/>
<circle cx="48" cy="181" r=".51" fill="none" stroke="#000080" stroke-width=".21"/>
<path d="M63.2 153.1v2.5" fill="none" stroke="#000080" stroke-width=".25"/>
<circle cx="63.2" cy="155.6" r=".51" fill="#000080"/>
<circle cx="63.2" cy="155.6" r=".51" fill="none" stroke="#000080" stroke-width=".21"/>
<path d="M78.5 168.3v2.6" fill="none" stroke="#000080" stroke-width=".25"/>
<circle cx="78.5" cy="170.9" r=".51" fill="#000080"/>
<circle cx="78.5" cy="170.9" r=".51" fill="none" stroke="#000080" stroke-width=".21"/>
<path d="M83.6 168.3v12.7" fill="none" stroke="#000080" stroke-width=".25"/>
<circle cx="83.5" cy="181" r=".51" fill="#000080"/>
<circle cx="83.5" cy="181" r=".51" fill="none" stroke="#000080" stroke-width=".21"/>
<path d="M93.7 145.5v2.5M93.7 158.2v2.5" fill="none" stroke="#000080" stroke-width=".25"/>
<circle cx="93.7" cy="145.5" r=".51" fill="#000080"/>
<circle cx="93.7" cy="145.5" r=".51" fill="none" stroke="#000080" stroke-width=".21"/>
<path d="M114.1 158.2h-2.6v7.6M218.3 155.6v2.6" fill="none" stroke="#000080" stroke-width=".25"/>
<circle cx="111.5" cy="165.8" r=".51" fill="#000080"/>
<circle cx="111.5" cy="165.8" r=".51" fill="none" stroke="#000080" stroke-width=".21"/>
<g fill="none" stroke="#000080" stroke-width=".25">
<path d="M35.2 99.8h12.8M86.1 99.8h12.7M136.9 99.8h12.7M187.8 99.8h12.7M35.2 117.5h12.8M35.2 109.9h12.8M35.2 112.5h12.8M35.2 107.4h12.8M35.2 102.3h12.8M86.1 117.5h12.7M86.1 109.9h12.7M86.1 112.5h12.7"/>
<path d="M86.1 107.4h12.7M86.1 102.3h12.7M136.9 117.5h12.7M136.9 109.9h12.7M136.9 112.5h12.7M136.9 107.4h12.7M136.9 102.3h12.7M187.8 117.6h12.7M187.8 109.9h12.7M187.8 112.5h12.7M187.8 107.4h12.7M187.8 102.3h12.7"/>
<path d="M241.2 107.4h20.3M154.7 148h2.6M154.7 153.1h2.6M154.7 158.2h2.6M154.7 163.3h2.6"/>
</g>
<circle cx="256.4" cy="107.4" r=".51" fill="#000080"/>
<circle cx="256.4" cy="107.4" r=".51" fill="none" stroke="#000080" stroke-width=".21"/>
<path d="M241.2 109.9h20.3" fill="none" stroke="#000080" stroke-width=".25"/>
<circle cx="256.4" cy="109.9" r=".51" fill="#000080"/>
<circle cx="256.4" cy="109.9" r=".51" fill="none" stroke="#000080" stroke-width=".21"/>
<g fill="none" stroke="#000080" stroke-width=".25">
<path d="M35.2 94.7h12.8M35.2 87.1h5.1M35.2 89.6h5.1M86.1 94.7h12.7M86.1 87.1h5.1M86.1 89.6h5.1M136.9 94.7h12.7M136.9 87.1h5.1M136.9 89.6h5.1M187.8 94.7h12.7M187.8 87.1h5.1M187.8 89.6h5.1"/>
<path d="M241.2 89.6h20.3"/>
</g>
<circle cx="248.8" cy="89.6" r=".51" fill="#000080"/>
<circle cx="248.8" cy="89.6" r=".51" fill="none" stroke="#000080" stroke-width=".21"/>
<path d="M218.3 140.4v5.1" fill="none" stroke="#000080" stroke-width=".25"/>
<circle cx="218.3" cy="142.9" r=".51" fill="#000080"/>
<circle cx="218.3" cy="142.9" r=".51" fill="none" stroke="#000080" stroke-width=".21"/>
<path d="M177.6 56.6h-2.5v2.5h2.5" fill="none" stroke="#000080" stroke-width=".25"/>
<circle cx="175.1" cy="59.1" r=".51" fill="#000080"/>
<circle cx="175.1" cy="59.1" r=".51" fill="none" stroke="#000080" stroke-width=".21"/>
<path d="M175.1 51.5h2.5M175.1 41.4h2.5M213.2 41.4h2.5v7.6h17.8v2.5M213.2 51.5h2.5" fill="none" stroke="#000080" stroke-width=".25"/>
<circle cx="233.5" cy="49" r=".51" fill="#000080"/>
<circle cx="233.5" cy="49" r=".51" fill="none" stroke="#000080" stroke-width=".21"/>
<path d="M253.9 26.1v2.6h-5.1" fill="none" stroke="#000080" stroke-width=".25"/>
<circle cx="251.3" cy="28.7" r=".51" fill="#000080"/>
<circle cx="251.3" cy="28.7" r=".51" fill="none" stroke="#000080" stroke-width=".21"/>
<path d="M157.3 28.7v5M157.3 43.9v2.5" fill="none" stroke="#000080" stroke-width=".25"/>
<circle cx="157.3" cy="28.7" r=".51" fill="#000080"/>
<circle cx="157.3" cy="28.7" r=".51" fill="none" stroke="#000080" stroke-width=".21"/>
<path d="M175.1 59.1v5.1" fill="none" stroke="#000080" stroke-width=".25"/>
<circle cx="175.1" cy="59.1" r=".51" fill="#000080"/>
<circle cx="175.1" cy="59.1" r=".51" fill="none" stroke="#000080" stroke-width=".21"/>
<path d="M233.5 46.4v2.6M215.7 61.7v2.5M233.5 61.7v2.5" fill="none" stroke="#000080" stroke-width=".25"/>
<circle cx="233.5" cy="49" r=".51" fill="#000080"/>
<circle cx="233.5" cy="49" r=".51" fill="none" stroke="#000080" stroke-width=".21"/>
<path d="M233.5 28.7v7.6" fill="none" stroke="#000080" stroke-width=".25"/>
<circle cx="233.5" cy="28.7" r=".51" fill="#000080"/>
<circle cx="233.5" cy="28.7" r=".51" fill="none" stroke="#000080" stroke-width=".21"/>
<path d="M213.2 28.7h25.4" fill="none" stroke="#000080" stroke-width=".25"/>
<circle cx="223.4" cy="28.7" r=".51" fill="#000080"/>
<circle cx="223.4" cy="28.7" r=".51" fill="none" stroke="#000080" stroke-width=".21"/>
<circle cx="233.5" cy="28.7" r=".51" fill="#000080"/>
<circle cx="233.5" cy="28.7" r=".51" fill="none" stroke="#000080" stroke-width=".21"/>
<circle cx="236.1" cy="28.7" r=".51" fill="#000080"/>
<circle cx="236.1" cy="28.7" r=".51" fill="none" stroke="#000080" stroke-width=".21"/>
<path d="M50.5 28.7v2.5h2.5" fill="none" stroke="#000080" stroke-width=".25"/>
<circle cx="50.5" cy="31.2" r=".51" fill="#000080"/>
<circle cx="50.5" cy="31.2" r=".51" fill="none" stroke="#000080" stroke-width=".21"/>
<circle cx="50.5" cy="28.7" r=".51" fill="#000080"/>
<circle cx="50.5" cy="28.7" r=".51" fill="none" stroke="#000080" stroke-width=".21"/>
<path d="M91.2 54.1v5M101.3 41.4v2.5" fill="none" stroke="#000080" stroke-width=".25"/>
<circle cx="101.3" cy="43.9" r=".51" fill="#000080"/>
<circle cx="101.3" cy="43.9" r=".51" fill="none" stroke="#000080" stroke-width=".21"/>
<path d="M88.6 28.7h7.7v2.5h-7.7" fill="none" stroke="#000080" stroke-width=".25"/>
<circle cx="96.3" cy="28.7" r=".51" fill="#000080"/>
<circle cx="96.3" cy="28.7" r=".51" fill="none" stroke="#000080" stroke-width=".21"/>
<path d="M101.3 28.7v2.5M109 56.6v2.5M116.6 41.4v2.5" fill="none" stroke="#000080" stroke-width=".25"/>
<circle cx="101.3" cy="28.7" r=".51" fill="#000080"/>
<circle cx="101.3" cy="28.7" r=".51" fill="none" stroke="#000080" stroke-width=".21"/>
<path d="M109 41.4v2.5" fill="none" stroke="#000080" stroke-width=".25"/>
<circle cx="109" cy="43.9" r=".51" fill="#000080"/>
<circle cx="109" cy="43.9" r=".51" fill="none" stroke="#000080" stroke-width=".21"/>
<path d="M109 28.7v2.5" fill="none" stroke="#000080" stroke-width=".25"/>
<circle cx="109" cy="28.7" r=".51" fill="#000080"/>
<circle cx="109" cy="28.7" r=".51" fill="none" stroke="#000080" stroke-width=".21"/>
<path d="M35.2 181h17.8" fill="none" stroke="#000080" stroke-width=".25"/>
<circle cx="48" cy="181" r=".51" fill="#000080"/>
<circle cx="48" cy="181" r=".51" fill="none" stroke="#000080" stroke-width=".21"/>
<path d="M35.2 170.9h28" fill="none" stroke="#000080" stroke-width=".25"/>
<circle cx="42.9" cy="170.9" r=".51" fill="#000080"/>
<circle cx="42.9" cy="170.9" r=".51" fill="none" stroke="#000080" stroke-width=".21"/>
<path d="M68.3 163.3v-7.7h-10.2v17.8" fill="none" stroke="#000080" stroke-width=".25"/>
<circle cx="63.2" cy="155.6" r=".51" fill="#000080"/>
<circle cx="63.2" cy="155.6" r=".51" fill="none" stroke="#000080" stroke-width=".21"/>
<path d="M114.1 153.1h-7.7v27.9h-43.2" fill="none" stroke="#000080" stroke-width=".25"/>
<circle cx="83.5" cy="181" r=".51" fill="#000080"/>
<circle cx="83.5" cy="181" r=".51" fill="none" stroke="#000080" stroke-width=".21"/>
<circle cx="98.8" cy="181" r=".51" fill="#000080"/>
<circle cx="98.8" cy="181" r=".51" fill="none" stroke="#000080" stroke-width=".21"/>
<path d="M114.1 150.6h-10.2v20.3h-30.5" fill="none" stroke="#000080" stroke-width=".25"/>
<circle cx="98.8" cy="170.9" r=".51" fill="#000080"/>
<circle cx="98.8" cy="170.9" r=".51" fill="none" stroke="#000080" stroke-width=".21"/>
<circle cx="78.5" cy="170.9" r=".51" fill="#000080"/>
<circle cx="78.5" cy="170.9" r=".51" fill="none" stroke="#000080" stroke-width=".21"/>
<path d="M81 142.9v12.7h2.5v2.6" fill="none" stroke="#000080" stroke-width=".25"/>
<circle cx="81" cy="145.5" r=".51" fill="#000080"/>
<circle cx="81" cy="145.5" r=".51" fill="none" stroke="#000080" stroke-width=".21"/>
<circle cx="81" cy="155.6" r=".51" fill="#000080"/>
<circle cx="81" cy="155.6" r=".51" fill="none" stroke="#000080" stroke-width=".21"/>
<path d="M81 145.5h33.1" fill="none" stroke="#000080" stroke-width=".25"/>
<circle cx="93.7" cy="145.5" r=".51" fill="#000080"/>
<circle cx="93.7" cy="145.5" r=".51" fill="none" stroke="#000080" stroke-width=".21"/>
<circle cx="81" cy="145.5" r=".51" fill="#000080"/>
<circle cx="81" cy="145.5" r=".51" fill="none" stroke="#000080" stroke-width=".21"/>
<path d="M136.9 26.1v2.6h5.1" fill="none" stroke="#000080" stroke-width=".25"/>
<circle cx="139.5" cy="28.7" r=".51" fill="#000080"/>
<circle cx="139.5" cy="28.7" r=".51" fill="none" stroke="#000080" stroke-width=".21"/>
<path d="M157.3 28.7h20.3" fill="none" stroke="#000080" stroke-width=".25"/>
<circle cx="175.1" cy="28.7" r=".51" fill="#000080"/>
<circle cx="175.1" cy="28.7" r=".51" fill="none" stroke="#000080" stroke-width=".21"/>
<circle cx="157.3" cy="28.7" r=".51" fill="#000080"/>
<circle cx="157.3" cy="28.7" r=".51" fill="none" stroke="#000080" stroke-width=".21"/>
<path d="M121.7 26.1v2.6h-5.1" fill="none" stroke="#000080" stroke-width=".25"/>
<circle cx="116.6" cy="28.7" r=".51" fill="#000080"/>
<circle cx="116.6" cy="28.7" r=".51" fill="none" stroke="#000080" stroke-width=".21"/>
<path d="M50.5 28.7h2.5" fill="none" stroke="#000080" stroke-width=".25"/>
<circle cx="50.5" cy="28.7" r=".51" fill="#000080"/>
<circle cx="50.5" cy="28.7" r=".51" fill="none" stroke="#000080" stroke-width=".21"/>
<path d="M35.2 28.7h5.1" fill="none" stroke="#000080" stroke-width=".25"/>
<circle cx="37.8" cy="28.7" r=".51" fill="#000080"/>
<circle cx="37.8" cy="28.7" r=".51" fill="none" stroke="#000080" stroke-width=".21"/>
<circle cx="40.3" cy="28.7" r=".51" fill="#000080"/>
<circle cx="40.3" cy="28.7" r=".51" fill="none" stroke="#000080" stroke-width=".21"/>
<path d="M40.3 28.7h10.2" fill="none" stroke="#000080" stroke-width=".25"/>
<circle cx="40.3" cy="28.7" r=".51" fill="#000080"/>
<circle cx="40.3" cy="28.7" r=".51" fill="none" stroke="#000080" stroke-width=".21"/>
<circle cx="50.5" cy="28.7" r=".51" fill="#000080"/>
<circle cx="50.5" cy="28.7" r=".51" fill="none" stroke="#000080" stroke-width=".21"/>
<path d="M20 26.1v2.6h5.1" fill="none" stroke="#000080" stroke-width=".25"/>
<circle cx="22.5" cy="28.7" r=".51" fill="#000080"/>
<circle cx="22.5" cy="28.7" r=".51" fill="none" stroke="#000080" stroke-width=".21"/>
<path d="M40.3 28.7v2.5M40.3 41.4v5" fill="none" stroke="#000080" stroke-width=".25"/>
<circle cx="40.3" cy="28.7" r=".51" fill="#000080"/>
<circle cx="40.3" cy="28.7" r=".51" fill="none" stroke="#000080" stroke-width=".21"/>
<path d="M152.2 28.7h5.1" fill="none" stroke="#000080" stroke-width=".25"/>
<circle cx="157.3" cy="28.7" r=".51" fill="#000080"/>
<circle cx="157.3" cy="28.7" r=".51" fill="none" stroke="#000080" stroke-width=".21"/>
<circle cx="154.7" cy="28.7" r=".51" fill="#000080"/>
<circle cx="154.7" cy="28.7" r=".51" fill="none" stroke="#000080" stroke-width=".21"/>
<path d="M205.6 137.9v2.5M205.6 150.6v5M205.6 165.8v2.5" fill="none" stroke="#000080" stroke-width=".25"/>
<circle cx="205.6" cy="153.1" r=".51" fill="#000080"/>
<circle cx="205.6" cy="153.1" r=".51" fill="none" stroke="#000080" stroke-width=".21"/>
<path d="M205.6 153.1h-7.7v2.5" fill="none" stroke="#000080" stroke-width=".25"/>
<circle cx="205.6" cy="153.1" r=".51" fill="#000080"/>
<circle cx="205.6" cy="153.1" r=".51" fill="none" stroke="#000080" stroke-width=".21"/>
<path d="M50.5 31.2v5.1h2.5M167.4 158.2h8.9M167.4 153.1h8.9M167.4 148h8.9M167.4 163.3h8.9" fill="none" stroke="#000080" stroke-width=".25"/>
<circle cx="50.5" cy="31.2" r=".51" fill="#000080"/>
<circle cx="50.5" cy="31.2" r=".51" fill="none" stroke="#000080" stroke-width=".21"/>
<path d="M50.5 43.9h2.5" fill="none" stroke="#000080" stroke-width=".25"/>
<circle cx="50.5" cy="43.9" r=".51" fill="#000080"/>
<circle cx="50.5" cy="43.9" r=".51" fill="none" stroke="#000080" stroke-width=".21"/>
<path d="M175.1 28.7v2.5h2.5" fill="none" stroke="#000080" stroke-width=".25"/>
<circle cx="175.1" cy="28.7" r=".51" fill="#000080"/>
<circle cx="175.1" cy="28.7" r=".51" fill="none" stroke="#000080" stroke-width=".21"/>
<path d="M53 41.4h-2.5v5" fill="none" stroke="#000080" stroke-width=".25"/>
<circle cx="50.5" cy="43.9" r=".51" fill="#000080"/>
<circle cx="50.5" cy="43.9" r=".51" fill="none" stroke="#000080" stroke-width=".21"/>
<path d="M241.2 94.7h20.3M241.2 97.2h20.3M241.2 120.1h20.3" fill="none" stroke="#000080" stroke-width=".76"/>
<path d="M96.3 28.7h20.3v2.5" fill="none" stroke="#000080" stroke-width=".25"/>
<circle cx="96.3" cy="28.7" r=".51" fill="#000080"/>
<circle cx="96.3" cy="28.7" r=".51" fill="none" stroke="#000080" stroke-width=".21"/>
<circle cx="101.3" cy="28.7" r=".51" fill="#000080"/>
<circle cx="101.3" cy="28.7" r=".51" fill="none" stroke="#000080" stroke-width=".21"/>
<circle cx="109" cy="28.7" r=".51" fill="#000080"/>
<circle cx="109" cy="28.7" r=".51" fill="none" stroke="#000080" stroke-width=".21"/>
<circle cx="114" cy="28.7" r=".51" fill="#000080"/>
<circle cx="114" cy="28.7" r=".51" fill="none" stroke="#000080" stroke-width=".21"/>
<circle cx="116.6" cy="28.7" r=".51" fill="#000080"/>
<circle cx="116.6" cy="28.7" r=".51" fill="none" stroke="#000080" stroke-width=".21"/>
<path d="M88.6 36.3h7.7v7.6h12.7v2.5" fill="none" stroke="#000080" stroke-width=".25"/>
<circle cx="101.3" cy="43.9" r=".51" fill="#000080"/>
<circle cx="101.3" cy="43.9" r=".51" fill="none" stroke="#000080" stroke-width=".21"/>
<circle cx="109" cy="43.9" r=".51" fill="#000080"/>
<circle cx="109" cy="43.9" r=".51" fill="none" stroke="#000080" stroke-width=".21"/>
<path d="M88.6 41.4h2.6v2.5" fill="none" stroke="#000080" stroke-width=".25"/>
<path d="M217 125.2h2.5M218.3 125.2v2.5" fill="none" stroke="#800000" stroke-width=".25"/>
<path d="M65.7 84.5h20.4v35.6h-20.4z" fill-rule="evenodd" fill="#80ff80"/>
<path d="M65.7 84.5h20.4v35.6h-20.4z" fill="none" stroke="#800000" stroke-width=".21"/>
<path d="M82.3 86.1h2.8l1 1-1 1h-2.8z" fill-rule="evenodd" fill="#ffff80"/>
<path d="M82.3 86.1h2.8l1 1-1 1h-2.8z" fill="none" stroke="#800000" stroke-width=".21"/>
<path d="M82.3 94.7l1-1h2.8v2h-2.8z" fill-rule="evenodd" fill="#ffff80"/>
<path d="M82.3 94.7l1-1h2.8v2h-2.8z" fill="none" stroke="#800000" stroke-width=".21"/>
<path d="M82.3 88.6h2.8l1 1-1 1h-2.8z" fill-rule="evenodd" fill="#ffff80"/>
<path d="M82.3 88.6h2.8l1 1-1 1h-2.8z" fill="none" stroke="#800000" stroke-width=".21"/>
<path d="M82.3 117.5l1-1h2.8v2.1h-2.8z" fill-rule="evenodd" fill="#ffff80"/>
<path d="M82.3 117.5l1-1h2.8v2.1h-2.8z" fill="none" stroke="#800000" stroke-width=".21"/>
<path d="M82.3 99.8l1-1h2.8v2h-2.8z" fill-rule="evenodd" fill="#ffff80"/>
<path d="M82.3 99.8l1-1h2.8v2h-2.8z" fill="none" stroke="#800000" stroke-width=".21"/>
<path d="M82.3 102.3l1-1h2.8v2h-2.8z" fill-rule="evenodd" fill="#ffff80"/>
<path d="M82.3 102.3l1-1h2.8v2h-2.8z" fill="none" stroke="#800000" stroke-width=".21"/>
<path d="M82.3 107.4l1-1h2.8v2h-2.8z" fill-rule="evenodd" fill="#ffff80"/>
<path d="M82.3 107.4l1-1h2.8v2h-2.8z" fill="none" stroke="#800000" stroke-width=".21"/>
<path d="M82.3 109.9l1-1h2.8v2h-2.8z" fill-rule="evenodd" fill="#ffff80"/>
<path d="M82.3 109.9l1-1h2.8v2h-2.8z" fill="none" stroke="#800000" stroke-width=".21"/>
<path d="M82.3 112.5l1-1h2.8v2h-2.8z" fill-rule="evenodd" fill="#ffff80"/>
<path d="M82.3 112.5l1-1h2.8v2h-2.8z" fill="none" stroke="#800000" stroke-width=".21"/>
<path d="M116.6 84.5h20.3v35.6h-20.3z" fill-rule="evenodd" fill="#80ff80"/>
<path d="M116.6 84.5h20.3v35.6h-20.3z" fill="none" stroke="#800000" stroke-width=".21"/>
<path d="M133.1 86.1h2.8l1 1-1 1h-2.8z" fill-rule="evenodd" fill="#ffff80"/>
<path d="M133.1 86.1h2.8l1 1-1 1h-2.8z" fill="none" stroke="#800000" stroke-width=".21"/>
<path d="M133.1 94.7l1-1h2.8v2h-2.8z" fill-rule="evenodd" fill="#ffff80"/>
<path d="M133.1 94.7l1-1h2.8v2h-2.8z" fill="none" stroke="#800000" stroke-width=".21"/>
<path d="M133.1 88.6h2.8l1 1-1 1h-2.8z" fill-rule="evenodd" fill="#ffff80"/>
<path d="M133.1 88.6h2.8l1 1-1 1h-2.8z" fill="none" stroke="#800000" stroke-width=".21"/>
<path d="M133.1 117.5l1-1h2.8v2.1h-2.8z" fill-rule="evenodd" fill="#ffff80"/>
<path d="M133.1 117.5l1-1h2.8v2.1h-2.8z" fill="none" stroke="#800000" stroke-width=".21"/>
<path d="M133.1 99.8l1-1h2.8v2h-2.8z" fill-rule="evenodd" fill="#ffff80"/>
<path d="M133.1 99.8l1-1h2.8v2h-2.8z" fill="none" stroke="#800000" stroke-width=".21"/>
<path d="M133.1 102.3l1-1h2.8v2h-2.8z" fill-rule="evenodd" fill="#ffff80"/>
<path d="M133.1 102.3l1-1h2.8v2h-2.8z" fill="none" stroke="#800000" stroke-width=".21"/>
<path d="M133.1 107.4l1-1h2.8v2h-2.8z" fill-rule="evenodd" fill="#ffff80"/>
<path d="M133.1 107.4l1-1h2.8v2h-2.8z" fill="none" stroke="#800000" stroke-width=".21"/>
<path d="M133.1 109.9l1-1h2.8v2h-2.8z" fill-rule="evenodd" fill="#ffff80"/>
<path d="M133.1 109.9l1-1h2.8v2h-2.8z" fill="none" stroke="#800000" stroke-width=".21"/>
<path d="M133.1 112.5l1-1h2.8v2h-2.8z" fill-rule="evenodd" fill="#ffff80"/>
<path d="M133.1 112.5l1-1h2.8v2h-2.8z" fill="none" stroke="#800000" stroke-width=".21"/>
<path d="M167.4 84.5h20.4v35.6h-20.4z" fill-rule="evenodd" fill="#80ff80"/>
<path d="M167.4 84.5h20.4v35.6h-20.4z" fill="none" stroke="#800000" stroke-width=".21"/>
<path d="M184 86.1h2.8l1 1-1 1h-2.8z" fill-rule="evenodd" fill="#ffff80"/>
<path d="M184 86.1h2.8l1 1-1 1h-2.8z" fill="none" stroke="#800000" stroke-width=".21"/>
<path d="M184 94.7l1-1h2.8v2h-2.8z" fill-rule="evenodd" fill="#ffff80"/>
<path d="M184 94.7l1-1h2.8v2h-2.8z" fill="none" stroke="#800000" stroke-width=".21"/>
<path d="M184 88.6h2.8l1 1-1 1h-2.8z" fill-rule="evenodd" fill="#ffff80"/>
<path d="M184 88.6h2.8l1 1-1 1h-2.8z" fill="none" stroke="#800000" stroke-width=".21"/>
<path d="M184 117.6l1-1.1h2.8v2.1h-2.8z" fill-rule="evenodd" fill="#ffff80"/>
<path d="M184 117.6l1-1.1h2.8v2.1h-2.8z" fill="none" stroke="#800000" stroke-width=".21"/>
<path d="M184 99.8l1-1h2.8v2h-2.8z" fill-rule="evenodd" fill="#ffff80"/>
<path d="M184 99.8l1-1h2.8v2h-2.8z" fill="none" stroke="#800000" stroke-width=".21"/>
<path d="M184 102.3l1-1h2.8v2h-2.8z" fill-rule="evenodd" fill="#ffff80"/>
<path d="M184 102.3l1-1h2.8v2h-2.8z" fill="none" stroke="#800000" stroke-width=".21"/>
<path d="M184 107.4l1-1h2.8v2h-2.8z" fill-rule="evenodd" fill="#ffff80"/>
<path d="M184 107.4l1-1h2.8v2h-2.8z" fill="none" stroke="#800000" stroke-width=".21"/>
<path d="M184 109.9l1-1h2.8v2.1h-2.8z" fill-rule="evenodd" fill="#ffff80"/>
<path d="M184 109.9l1-1h2.8v2.1h-2.8z" fill="none" stroke="#800000" stroke-width=".21"/>
<path d="M184 112.5l1-1h2.8v2h-2.8z" fill-rule="evenodd" fill="#ffff80"/>
<path d="M184 112.5l1-1h2.8v2h-2.8z" fill="none" stroke="#800000" stroke-width=".21"/>
<use href="#words"/>
</svg>
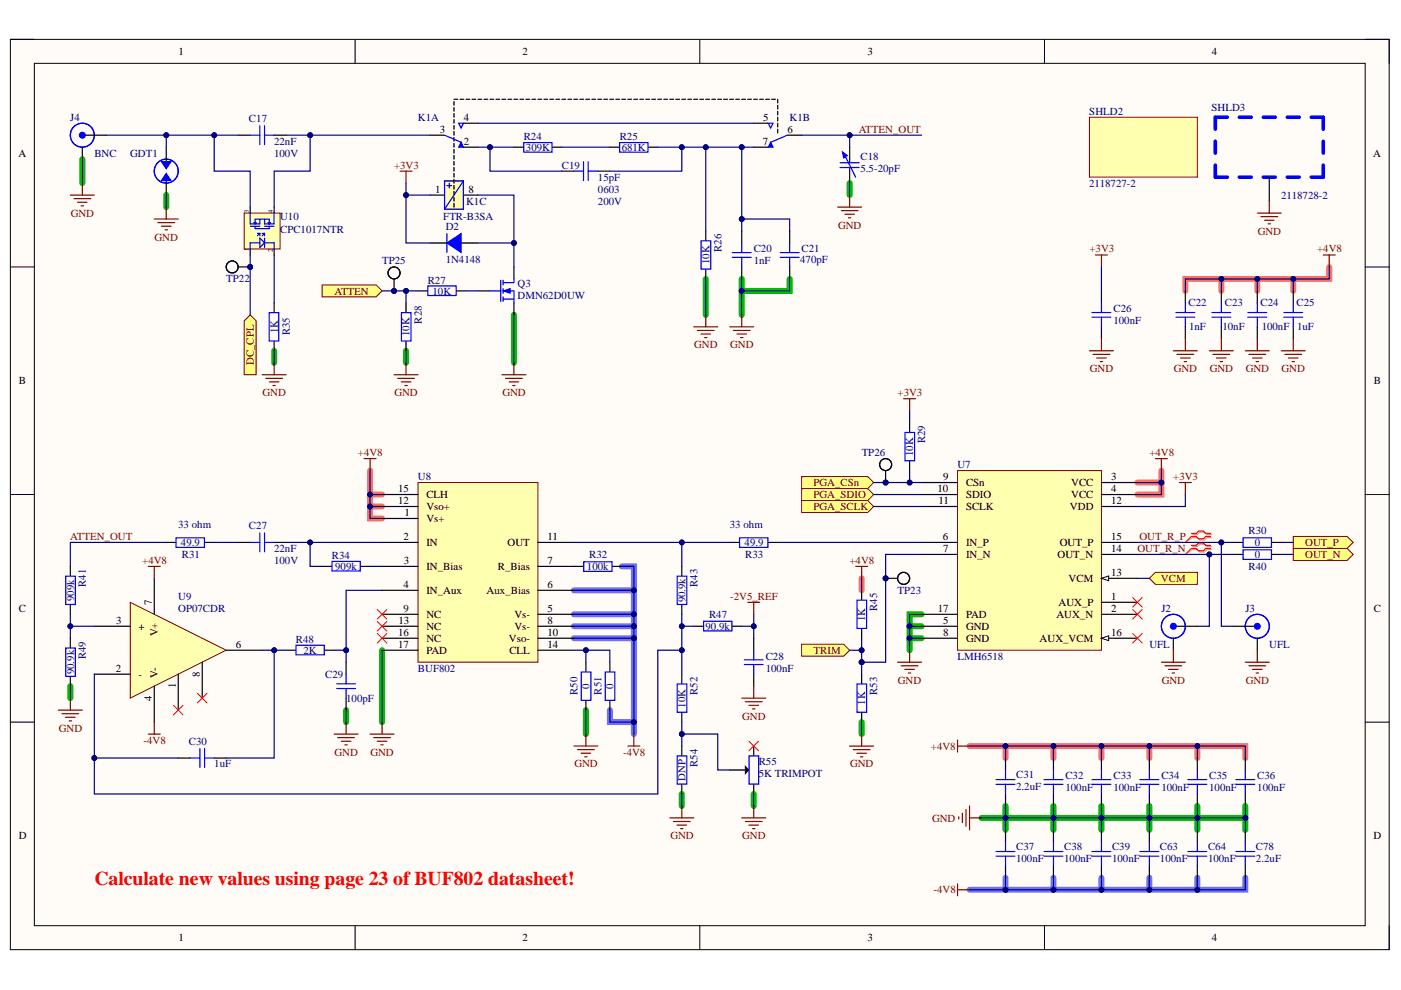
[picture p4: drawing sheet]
<svg xmlns="http://www.w3.org/2000/svg" width="297mm" height="210mm" viewBox="0 0 297 210" stroke-linecap="round" stroke-linejoin="round" font-family="sans-serif">
<defs><g id="words">
<text font-size="4.1" fill="#f00" x="20" y="187.7">Calculate new values using page 23 of BUF802 datasheet!</text>
<g font-size="2.3">
<text x="37.9" y="11.7">1</text>
<text x="110.8" y="11.7">2</text>
<text x="184" y="11.7">3</text>
<text x="256.9" y="11.7">4</text>
<text x="93.2" y="28.1">3</text>
<text x="98.3" y="25.6">4</text>
<text x="161.8" y="25.6">5</text>
<text x="167" y="28.1">6</text>
<text x="3.9" y="33.2">A</text>
<text x="98.3" y="30.7">2</text>
<text x="161.8" y="30.7">7</text>
<text x="291.1" y="33.2">A</text>
<text x="92.3" y="40.9">1</text>
<text x="99.3" y="40.9">8</text>
<text x="4" y="81.5">B</text>
<text x="291.3" y="81.5">B</text>
<text x="200" y="101.8">9</text>
<text x="235.6" y="101.8">3</text>
<text x="84.4" y="106.9">12</text>
<text x="84.4" y="104.3">15</text>
<text x="90.4" y="105.6">CLH</text>
<text x="198.8" y="104.3">10</text>
<text x="199" y="106.9">11</text>
<text x="204.8" y="103.1">CSn</text>
<text x="204.8" y="105.6">SDIO</text>
<text x="227.1" y="103.1">VCC</text>
<text x="227.1" y="105.6">VCC</text>
<text x="235.6" y="106.9">12</text>
<text x="235.6" y="104.3">4</text>
<text x="85.7" y="109.4">1</text>
<text x="90.4" y="110.7">Vs+</text>
<text x="90.4" y="108.1">Vso+</text>
<text x="204.8" y="108.1">SCLK</text>
<text x="226.9" y="108.1">VDD</text>
<text x="85.5" y="114.5">2</text>
<text x="85.6" y="119.6">3</text>
<text x="90.4" y="115.8">IN</text>
<text x="107.6" y="115.8">OUT</text>
<text x="116.1" y="119.6">7</text>
<text x="116.1" y="114.5">11</text>
<text x="199.9" y="114.5">6</text>
<text x="200" y="117">7</text>
<text x="204.8" y="115.8">IN_P</text>
<text x="204.8" y="118.3">IN_N</text>
<text x="224.2" y="118.3">OUT_N</text>
<text x="224.7" y="115.8">OUT_P</text>
<text x="235.6" y="117">14</text>
<text x="235.6" y="114.5">15</text>
<text x="85.5" y="124.7">4</text>
<text x="90.4" y="120.8">IN_Bias</text>
<text x="90.4" y="125.9">IN_Aux</text>
<text x="103.2" y="125.9">Aux_Bias</text>
<text x="105.6" y="120.8">R_Bias</text>
<text x="116.1" y="124.7">6</text>
<text x="226.6" y="123.4">VCM</text>
<text x="235.6" y="122.1">13</text>
<text x="4" y="129.7">C</text>
<text x="32.2" y="128.2" transform="rotate(-90 32.2 128.2)">7</text>
<text x="85.5" y="129.7">9</text>
<text x="90.4" y="131">NC</text>
<text x="109" y="131">Vs-</text>
<text x="116.1" y="129.7">5</text>
<text x="198.8" y="129.7">17</text>
<text x="204.8" y="131">PAD</text>
<text x="224" y="131">AUX_N</text>
<text x="224.4" y="128.5">AUX_P</text>
<text x="235.6" y="127.2">1</text>
<text x="235.6" y="129.7">2</text>
<text x="291.3" y="129.7">C</text>
<text x="24.6" y="132.3">3</text>
<text x="29.4" y="133.5">+</text>
<text x="33.5" y="134.9" transform="rotate(-90 33.5 134.9)">V+</text>
<text x="50" y="137.3">6</text>
<text x="84.4" y="134.8">16</text>
<text x="84.4" y="137.3">17</text>
<text x="84.5" y="132.3">13</text>
<text x="90.4" y="133.5">NC</text>
<text x="90.4" y="136.1">NC</text>
<text x="107.9" y="136.1">Vso-</text>
<text x="109" y="133.5">Vs-</text>
<text x="116.1" y="132.3">8</text>
<text x="116.1" y="134.8">10</text>
<text x="116.1" y="137.3">14</text>
<text x="200" y="134.8">8</text>
<text x="200" y="132.3">5</text>
<text x="204.8" y="136.1">GND</text>
<text x="204.8" y="133.5">GND</text>
<text x="220.4" y="136.1">AUX_VCM</text>
<text x="235.6" y="134.8">16</text>
<text x="24.5" y="142.4">2</text>
<text x="29.4" y="143.7">-</text>
<text x="33.5" y="143.7" transform="rotate(-90 33.5 143.7)">V-</text>
<text x="42.4" y="143.5" transform="rotate(-90 42.4 143.5)">8</text>
<text x="90.4" y="138.6">PAD</text>
<text x="108" y="138.6">CLL</text>
<text x="32.2" y="148.6" transform="rotate(-90 32.2 148.6)">4</text>
<text x="37.3" y="145.8" transform="rotate(-90 37.3 145.8)">1</text>
<text x="4" y="178">D</text>
<text x="291.2" y="178">D</text>
<text x="37.9" y="199.6">1</text>
<text x="110.8" y="199.6">2</text>
<text x="184" y="199.6">3</text>
<text x="256.9" y="199.6">4</text>
</g>
<g font-size="2.3" fill="#000080">
<text x="256.9" y="23.6">SHLD3</text>
<text x="14.9" y="25.6">J4</text>
<text x="52.8" y="25.9">C17</text>
<text x="88.6" y="25.6">K1A</text>
<text x="111" y="29.7">R24</text>
<text x="131.4" y="29.7">R25</text>
<text x="167.4" y="25.6">K1B</text>
<text x="231" y="24.3">SHLD2</text>
<text x="20" y="33.2">BNC</text>
<text x="27.6" y="33.2">GDT1</text>
<text x="58.1" y="33.2">100V</text>
<text x="58.1" y="30.7">22nF</text>
<text x="111.5" y="31.9">309K</text>
<text x="119.1" y="35.8">C19</text>
<text x="131.8" y="31.9">681K</text>
<text x="182.4" y="34">C18</text>
<text x="126.8" y="40.9">0603</text>
<text x="126.8" y="38.3">15pF</text>
<text x="182.4" y="36.5">5.5-20pF</text>
<text x="231" y="39.6">2118727-2</text>
<text x="59.4" y="46.7">U10</text>
<text x="94" y="46.6">FTR-B3SA</text>
<text x="98.8" y="43.4">K1C</text>
<text x="126.8" y="43.4">200V</text>
<text x="271.6" y="42.1">2118728-2</text>
<text x="59.4" y="49.3">CPC1017NTR</text>
<text x="94.5" y="48.8">D2</text>
<text x="153" y="53.4" transform="rotate(-90 153 53.4)">R26</text>
<text x="159.8" y="53.5">C20</text>
<text x="170" y="53.5">C21</text>
<text x="48" y="59.9">TP22</text>
<text x="81" y="56.1">TP25</text>
<text x="94.5" y="55.8">1N4148</text>
<text x="150.4" y="56" transform="rotate(-90 150.4 56)">10K</text>
<text x="159.8" y="56.1">1nF</text>
<text x="169.7" y="55.8">470pF</text>
<text x="90.7" y="60.1">R27</text>
<text x="91.7" y="62.4">10K</text>
<text x="109.7" y="60.9">Q3</text>
<text x="109.7" y="63.5">DMN62D0UW</text>
<text x="252" y="65">C22</text>
<text x="259.7" y="65">C23</text>
<text x="267.3" y="65">C24</text>
<text x="274.9" y="65">C25</text>
<text x="58.9" y="70.7" transform="rotate(-90 58.9 70.7)">1K</text>
<text x="61.4" y="71.1" transform="rotate(-90 61.4 71.1)">R35</text>
<text x="86.8" y="71.3" transform="rotate(-90 86.8 71.3)">10K</text>
<text x="89.4" y="68.6" transform="rotate(-90 89.4 68.6)">R28</text>
<text x="236.1" y="66.3">C26</text>
<text x="236.1" y="68.8">100nF</text>
<text x="252.1" y="70.1">1nF</text>
<text x="259.2" y="70.1">10nF</text>
<text x="267.5" y="70.1">100nF</text>
<text x="275" y="70.1">1uF</text>
<text x="196.1" y="94" transform="rotate(-90 196.1 94)">R29</text>
<text x="88.6" y="101.8">U8</text>
<text x="182.7" y="96.7">TP26</text>
<text x="193.6" y="96.7" transform="rotate(-90 193.6 96.7)">10K</text>
<text x="203" y="99.3">U7</text>
<text x="37.8" y="111.9">33 ohm</text>
<text x="52.8" y="112.2">C27</text>
<text x="154.7" y="111.9">33 ohm</text>
<text x="264.7" y="113.2">R30</text>
<text x="38.4" y="115.8">49.9</text>
<text x="38.5" y="118.3">R31</text>
<text x="58.1" y="119.6">100V</text>
<text x="58.1" y="117">22nF</text>
<text x="70.4" y="118.5">R34</text>
<text x="124.9" y="118.3">R32</text>
<text x="157.9" y="115.8">49.9</text>
<text x="158" y="118.3">R33</text>
<text x="266" y="115.8">0</text>
<text x="266" y="118.3">0</text>
<text x="18.2" y="124.4" transform="rotate(-90 18.2 124.4)">R41</text>
<text x="71.1" y="120.8">909k</text>
<text x="124.4" y="120.8">100k</text>
<text x="147.9" y="124.4" transform="rotate(-90 147.9 124.4)">R43</text>
<text x="190.3" y="125.9">TP23</text>
<text x="264.7" y="120.8">R40</text>
<text x="15.7" y="127.4" transform="rotate(-90 15.7 127.4)">909k</text>
<text x="37.8" y="127.2">U9</text>
<text x="37.8" y="129.7">OP07CDR</text>
<text x="145.3" y="127.7" transform="rotate(-90 145.3 127.7)">90.9k</text>
<text x="150.3" y="131">R47</text>
<text x="183.5" y="131.7" transform="rotate(-90 183.5 131.7)">1K</text>
<text x="186" y="129.6" transform="rotate(-90 186 129.6)">R45</text>
<text x="246.2" y="129.7">J2</text>
<text x="264" y="129.7">J3</text>
<text x="62.7" y="136.3">R48</text>
<text x="149.6" y="133.5">90.9k</text>
<text x="243.7" y="137.3">UFL</text>
<text x="269.1" y="137.3">UFL</text>
<text x="15.7" y="143" transform="rotate(-90 15.7 143)">90.9k</text>
<text x="18.2" y="139.7" transform="rotate(-90 18.2 139.7)">R49</text>
<text x="64.3" y="138.6">2K</text>
<text x="68.9" y="143.7">C29</text>
<text x="88.6" y="142.4">BUF802</text>
<text x="162.3" y="139.9">C28</text>
<text x="162.3" y="142.4">100nF</text>
<text x="203" y="139.9">LMH6518</text>
<text x="73.4" y="148.8">100pF</text>
<text x="122.5" y="147.3" transform="rotate(-90 122.5 147.3)">R50</text>
<text x="125" y="146" transform="rotate(-90 125 146)">0</text>
<text x="127.5" y="147.3" transform="rotate(-90 127.5 147.3)">R51</text>
<text x="130.1" y="146" transform="rotate(-90 130.1 146)">0</text>
<text x="147.9" y="147.3" transform="rotate(-90 147.9 147.3)">R52</text>
<text x="183.5" y="149.4" transform="rotate(-90 183.5 149.4)">1K</text>
<text x="186" y="147.3" transform="rotate(-90 186 147.3)">R53</text>
<text x="145.3" y="150" transform="rotate(-90 145.3 150)">10K</text>
<text x="40.1" y="158">C30</text>
<text x="45.4" y="162.7">1uF</text>
<text x="145.3" y="165.5" transform="rotate(-90 145.3 165.5)">DNP</text>
<text x="147.9" y="162.6" transform="rotate(-90 147.9 162.6)">R54</text>
<text x="160.9" y="162.3">R55</text>
<text x="160.9" y="164.8">5K TRIMPOT</text>
<text x="215.4" y="165">C31</text>
<text x="215.4" y="167.5">2.2uF</text>
<text x="225.9" y="165.3">C32</text>
<text x="225.9" y="167.8">100nF</text>
<text x="236.1" y="165.3">C33</text>
<text x="236.1" y="167.8">100nF</text>
<text x="246.2" y="165.3">C34</text>
<text x="246.2" y="167.8">100nF</text>
<text x="256.4" y="165.3">C35</text>
<text x="256.4" y="167.8">100nF</text>
<text x="266.6" y="165.3">C36</text>
<text x="266.6" y="167.8">100nF</text>
<text x="215.4" y="180.3">C37</text>
<text x="215.4" y="182.8">100nF</text>
<text x="225.6" y="180.3">C38</text>
<text x="225.6" y="182.8">100nF</text>
<text x="235.8" y="180.3">C39</text>
<text x="235.8" y="182.8">100nF</text>
<text x="245.9" y="180.3">C63</text>
<text x="245.9" y="182.8">100nF</text>
<text x="256.1" y="180.3">C64</text>
<text x="256.1" y="182.8">100nF</text>
<text x="266.3" y="180.3">C78</text>
<text x="266.3" y="182.8">2.2uF</text>
</g>
<g font-size="2.3" fill="#800000">
<text x="182.1" y="28.1">ATTEN_OUT</text>
<text x="83.5" y="35.8">+3V3</text>
<text x="15" y="45.9">GND</text>
<text x="32.8" y="51">GND</text>
<text x="177.7" y="48.5">GND</text>
<text x="231" y="53.5">+3V3</text>
<text x="266.7" y="49.7">GND</text>
<text x="279.3" y="53.5">+4V8</text>
<text x="70.9" y="62.4">ATTEN</text>
<text x="53.8" y="77.4" transform="rotate(-90 53.8 77.4)">DC_CPL</text>
<text x="147.2" y="73.9">GND</text>
<text x="154.8" y="73.9">GND</text>
<text x="231.1" y="78.9">GND</text>
<text x="248.8" y="78.9">GND</text>
<text x="256.5" y="78.9">GND</text>
<text x="264.1" y="78.9">GND</text>
<text x="271.7" y="78.9">GND</text>
<text x="55.7" y="84">GND</text>
<text x="83.6" y="84">GND</text>
<text x="106.5" y="84">GND</text>
<text x="190.3" y="84">+3V3</text>
<text x="75.9" y="96.7">+4V8</text>
<text x="243.7" y="96.7">+4V8</text>
<text x="248.8" y="101.8">+3V3</text>
<text x="172.5" y="103.1">PGA_CSn</text>
<text x="172.5" y="105.6">PGA_SDIO</text>
<text x="172.5" y="108.1">PGA_SCLK</text>
<text x="14.9" y="114.5">ATTEN_OUT</text>
<text x="30.2" y="119.6">+4V8</text>
<text x="180.1" y="119.6">+4V8</text>
<text x="241.2" y="117">OUT_R_N</text>
<text x="241.6" y="114.5">OUT_R_P</text>
<text x="276.7" y="115.8">OUT_P</text>
<text x="276.7" y="118.3">OUT_N</text>
<text x="246.1" y="123.4">VCM</text>
<text x="154.8" y="127.2">-2V5_REF</text>
<text x="172.5" y="138.6">TRIM</text>
<text x="190.4" y="145">GND</text>
<text x="246.3" y="145">GND</text>
<text x="264.1" y="145">GND</text>
<text x="12.5" y="155.1">GND</text>
<text x="157.4" y="152.6">GND</text>
<text x="30.4" y="157.7">-4V8</text>
<text x="70.9" y="160.2">GND</text>
<text x="78.6" y="160.2">GND</text>
<text x="132.1" y="160.2">-4V8</text>
<text x="197.4" y="158.9">+4V8</text>
<text x="121.8" y="162.7">GND</text>
<text x="180.2" y="162.7">GND</text>
<text x="142.1" y="178">GND</text>
<text x="157.4" y="178">GND</text>
<text x="197.6" y="174.2">GND</text>
<text x="197.9" y="189.4">-4V8</text>
</g>
<g font-size="1.4">
<text x="52.7" y="45.2" transform="rotate(-90 52.7 45.2)">3</text>
<text x="57.8" y="45.2" transform="rotate(-90 57.8 45.2)">4</text>
<text x="52.7" y="53.3" transform="rotate(-90 52.7 53.3)">1</text>
<text x="57.8" y="53.4" transform="rotate(-90 57.8 53.4)">2</text>
</g>
</g></defs>
<path d="M2.2 8.3h292.3v193.1h-292.3z" fill-rule="evenodd" fill="#fffcf8"/>
<path d="M2.2 8.3h292.3v193.1h-292.3z" fill="none" stroke="#000" stroke-width=".21"/>
<path d="M7.3 13.4h282.1v182.9h-282.1z" fill-rule="evenodd" fill="#fffcf8"/>
<g fill="none" stroke="#000" stroke-width=".21">
<path d="M2.2 8.3h5.1M7.3 13.4h282.1v182.9h-282.1zM75.3 8.3v5.1M148.4 8.3v5.1M221.5 8.3v5.1M289.4 8.3h5.1v5.1M2.2 56.6h5.1M289.4 56.6h5.1M2.2 104.8h5.1M289.4 104.9h5.1M2.2 153.1h5.1M289.4 153.1h5.1"/>
<path d="M75.3 196.3v5.1M148.4 196.3v5.1M221.5 196.3v5.1M294.5 196.3v5.1"/>
</g>
<g fill="none" stroke="#00be00" stroke-width="1.3">
<path d="M17.5 33.7v5.1M180.1 38.8v2.6M35.2 41.4v2.5M149.6 59.1v7.7M157.3 59.1v7.7M167.4 59.1v2.6h-10.1M58.1 74.4v2.5M86.1 74.4v2.5M109 66.8v10.1M81 137.9v15.2M192.9 132.8h2.5M192.9 135.3v2.6"/>
<path d="M195.4 130.3h-2.5v5h2.5M14.9 145.5v2.5M73.4 150.6v2.5M124.2 150.6v5M182.7 153.1v2.5M144.6 168.3v2.6M159.8 168.3v2.6M208.1 173.4h55.9M213.2 170.9v5.1M223.4 170.9v5.1M233.5 170.9v5.1M243.7 170.9v5.1"/>
<path d="M253.9 170.9v5.1M264 170.9v5.1"/>
</g>
<g fill="none" stroke="#ff6e6e" stroke-width="1.3">
<path d="M258.9 59.1h-7.6v2.6M266.6 59.1h-7.7v2.6M274.2 59.1v2.6M281.8 56.6v2.5h-15.2v2.6M78.5 99.8v10.1h2.5M246.2 99.8v5.1h-5M78.5 107.4h2.5M78.5 104.8h2.5M241.2 102.3h5M182.7 122.6v2.6M205.6 158.2h17.8v2.5M213.2 158.2v2.5"/>
<path d="M223.4 158.2h40.6v2.5M233.5 158.2v2.5M243.7 158.2v2.5M253.9 158.2v2.5"/>
</g>
<g fill="none" stroke="#6e6eff" stroke-width="1.3">
<path d="M121.7 125.2h12.7v5h-12.7M121.7 132.8h12.7M131.8 120.1h2.6v5.1M134.4 132.8v2.5h-12.7M134.4 135.3v20.3M134.4 130.2v2.6M129.3 150.6v2.5h5.1M213.2 186.1v2.6M223.4 186.1v2.6M233.5 186.1v2.6M243.7 186.1v2.6M253.9 186.1v2.6"/>
<path d="M264 186.1v2.6h-58.4"/>
</g>
<circle cx="53" cy="56.6" r=".51" fill="#000080"/>
<circle cx="53" cy="56.6" r=".51" fill="none" stroke="#000080" stroke-width=".21"/>
<path d="M50.5 56.6h2.5" fill="none" stroke="#000" stroke-width=".25"/>
<circle cx="53" cy="56.6" r=".51" fill="#000080"/>
<circle cx="53" cy="56.6" r=".51" fill="none" stroke="#000080" stroke-width=".21"/>
<g fill="none" stroke="#000" stroke-width=".25">
<path d="M269.1 37.6v5"/>
<circle cx="49.2" cy="56.6" r="1.27"/>
</g>
<path d="M257.7 29.9v2.6M257.7 35v2.6h2.5M260.2 24.9h-2.5v2.5M262.8 37.6h2.5M262.8 24.9h2.5M267.8 37.6h2.6M267.8 24.9h2.6M272.9 37.6h2.6M272.9 24.9h2.6M278 24.9h2.6v2.5M280.6 35v2.6h-2.6M280.6 29.9v2.6" fill="none" stroke="#00f" stroke-width=".76"/>
<path d="M266.6 45.2h5M267.3 45.9h3.6M268.1 46.7h2M268.9 47.5h.5M269.1 42.6v2.6" fill="none" stroke="#800000" stroke-width=".25"/>
<path d="M231 24.9h22.9v12.7h-22.9z" fill-rule="evenodd" fill="#ffffb0"/>
<path d="M231 24.9h22.9v12.7h-22.9z" fill="none" stroke="#800000" stroke-width=".21"/>
<path d="M94.3 38.4h4v6h-4z" fill-rule="evenodd" fill="#ffffb0"/>
<path d="M94.3 38.4h4v6h-4z" fill="none" stroke="#800000" stroke-width=".21"/>
<path d="M94.8 39.4h1M95.3 38.9v1M98.3 38.4l-4 6M98.3 38.4h-4v6M98.3 38.4v6h-4" fill="none" stroke="#00f" stroke-width=".25"/>
<path d="M91.2 41.4h3M91.2 51.5h3.8M97.5 51.5h3.8M98.3 41.4h3" fill="none" stroke="#000" stroke-width=".25"/>
<path d="M84.8 36.3h2.6M86.1 36.3v2.5" fill="none" stroke="#800000" stroke-width=".25"/>
<path d="M94.8 51.5l3-2v4z" fill="#00f"/>
<path d="M94.8 51.5l3-2v4zM94.8 49.5v4M106.2 59.4v4.5M106.7 59.9h2.3M106.7 59.4v1M103.9 61.7h2.3M106.7 61.7h2.3v2.5M106.7 63.4h2.3M106.7 61.2v1M106.7 62.9v1" fill="none" stroke="#00f" stroke-width=".25"/>
<path d="M109 56.6v2.5M101.3 61.7h2.6M109 64.2v2.6" fill="none" stroke="#000" stroke-width=".25"/>
<path d="M106.7 61.7l1.5-.5v1z" fill="#00f"/>
<path d="M106.7 61.7l1.5-.5v1z" fill="none" stroke="#00f" stroke-width=".21"/>
<path d="M109 59.1v.8M85.1 66.3h2v6h-2z" fill="none" stroke="#00f" stroke-width=".25"/>
<path d="M83.5 79.5h5.1M86.1 76.9v2.6M106.4 79.5h5.1M109 76.9v2.6M84.3 80.2h3.6M85.1 81h2M85.8 81.7h.5M107.2 80.2h3.5M107.9 81h2.1M108.7 81.7h.5" fill="none" stroke="#800000" stroke-width=".25"/>
<path d="M86.1 64.2v2M86.1 72.4v2" fill="none" stroke="#000" stroke-width=".25"/>
<path d="M68.3 60.4h11.4l1.3 1.3-1.3 1.2h-11.4z" fill-rule="evenodd" fill="#ffff80"/>
<path d="M68.3 60.4h11.4l1.3 1.3-1.3 1.2h-11.4z" fill="none" stroke="#800000" stroke-width=".21"/>
<g fill="none" stroke="#000" stroke-width=".25">
<path d="M91.2 28.7h3M96.3 21.5v.8M96.3 22.8v.8M96.3 24.1v.8M96.3 25.3v.8M96.3 26.6v.8M96.3 27.9v.8M96.3 29.1v.8M96.3 30.4v.8M96.3 31.7v.8M96.3 33v.7M96.3 34.2v.8"/>
<path d="M96.3 35.5v.8M96.3 36.8v.8M96.3 38v.8M96.3 39.3v.8M96.3 21h.8M97.5 21h.8M98.8 21h.8M100.1 21h.8M101.3 21h.8M102.6 21h.8M103.9 21h.8M105.2 21h.7"/>
<path d="M106.4 21h.8M107.7 21h.8M109 31.2h2M109 21h.8M110.2 21h.8M111.5 21h.8M112.8 21h.8M114.1 21h.7M115.3 21h.8M116.6 21h.8M117.1 31.2h2M117.9 21h.8"/>
<path d="M119.1 36.3h2.6M119.1 21h.8M120.4 21h.8M121.7 21h.8M122.9 21h.8M124.2 21h.8M125.5 21h.8M126.8 36.3h2.5M126.8 21h.8M128 21h.8M129.3 31.2h2M129.3 21h.8"/>
<path d="M130.6 21h.8M131.8 21h.8M133.1 21h.8M134.4 21h.8M135.7 21h.7M136.9 21h.8M137.5 31.2h2M138.2 21h.8M139.5 21h.8M140.7 21h.8M142 21h.8M143.3 21h.8"/>
<path d="M144.6 21h.7M145.8 21h.8M147.1 21h.8M148.4 21h.8M149.6 21h.8M150.9 21h.8M152.2 21h.8M153.4 21h.8M154.7 21h.8M156 21h.8M157.3 21h.8M158.5 21h.8"/>
<path d="M159.8 21h.8M161.1 21h.8M162.3 21h.8M163.6 21h.8M164.9 21v.8M164.9 22.3v.8M164.9 23.6v.8M164.9 24.9v.8M164.9 26.1v.8M164.9 27.4v.8M96.3 40.6v.8M96.3 41.8v.8"/>
<path d="M96.3 43.1v.8M149.6 49v2M149.6 57.1v2M157.3 49v2.5M157.3 56.6v2.5M167.4 49v2.5M167.4 56.6v2.5"/>
</g>
<g fill="none" stroke="#00f" stroke-width=".25">
<path d="M94.3 28.7l3.5 1.5M111 30.2h6v2.1h-6zM121.7 36.3h2M123.7 34.3v4M124.7 36.3h2.1M124.7 34.3v4M131.4 30.2h6v2.1h-6zM148.7 51.1h2v6h-2zM155.3 54.6h4M155.3 53.6h4M157.3 51.5v2.1M157.3 54.6v2"/>
<path d="M165.4 54.6h4M165.4 53.6h4M167.4 51.5v2.1M167.4 54.6v2"/>
</g>
<g fill="none" stroke="#800000" stroke-width=".25">
<path d="M177.6 43.9h5.1M178.4 44.7h3.5M179.1 45.4h2.1M179.9 46.2h.5M180.1 41.4v2.5M147.1 69.3h5.1M147.9 70.1h3.5M148.6 70.8h2.1M149.4 71.6h.5M149.6 66.8v2.5M154.7 69.3h5.1M155.5 70.1h3.5"/>
<path d="M156.2 70.8h2.1M157 71.6h.5M157.3 66.8v2.5"/>
</g>
<path d="M97.8 30.2l.5 1h-1z" fill="#00f"/>
<path d="M97.3 26.1h1l-.5 1.1zM97.8 30.2l.5 1h-1zM162.9 26.1h1l-.5 1.1zM166.9 28.7l-3.5 1.5" fill="none" stroke="#00f" stroke-width=".25"/>
<path d="M98.3 31.2h3M98.3 26.1h3M167 28.7h3" fill="none" stroke="#000" stroke-width=".25"/>
<path d="M163.4 30.2l.5 1h-1z" fill="#00f"/>
<path d="M53 28.7h2.1M55.1 26.7v4M56.1 28.7h2M56.1 26.7v4M163.4 30.2l.5 1h-1zM57.1 66.3h2v6h-2zM90.7 60.6h6v2.1h-6z" fill="none" stroke="#00f" stroke-width=".25"/>
<path d="M50.5 28.7h2.5M58.1 28.7h2.6M159.8 26.1h3M159.8 31.2h3M58.1 64.2v2M58.1 72.4v2M88.6 61.7h2M96.8 61.7h2" fill="none" stroke="#000" stroke-width=".25"/>
<path d="M32.7 46.4h5.1M33.5 47.2h3.5M34.2 48h2.1M35 48.7h.5M35.2 43.9v2.5M55.6 79.5h5.1M58.1 76.9v2.6M56.3 80.2h3.6M57.1 81h2M57.9 81.7h.5" fill="none" stroke="#800000" stroke-width=".25"/>
<path d="M51.8 68l1.2-1.2 1.3 1.2v11.5h-2.5z" fill-rule="evenodd" fill="#ffff80"/>
<path d="M51.8 68l1.2-1.2 1.3 1.2v11.5h-2.5z" fill="none" stroke="#800000" stroke-width=".21"/>
<circle cx="35.2" cy="36.3" r="2.54" fill="none" stroke="#00f" stroke-width=".25"/>
<path d="M34.2 34.3h2l-1 1.5z" fill="#00f"/>
<path d="M34.2 34.3h2l-1 1.5z" fill="none" stroke="#00f" stroke-width=".25"/>
<path d="M35.2 36.8l1 1.5h-2z" fill="#00f"/>
<path d="M35.2 36.8l1 1.5h-2z" fill="none" stroke="#00f" stroke-width=".25"/>
<path d="M35.2 31.2v2.9M35.2 38.4v3" fill="none" stroke="#000" stroke-width=".25"/>
<path d="M51.8 45.2h7.6v7.6h-7.6z" fill-rule="evenodd" fill="#ffffb0"/>
<path d="M51.8 45.2h7.6v7.6h-7.6z" fill="none" stroke="#800000" stroke-width=".21"/>
<path d="M180.1 31.2v2.5M180.1 36.3v2.5M53 43.9v1.3M53 52.8v1.3M58.1 43.9v1.3M58.1 52.8v1.3" fill="none" stroke="#000" stroke-width=".25"/>
<g fill="none" stroke="#00f" stroke-width=".25">
<path d="M179.1 33l2.3 4.6M53 45.2v2.3M53.1 48h2M53.8 47.2h.5l-.2 .3zM54.1 48v.5h3v-.5M54.1 47.5v-1h3v1M54.6 49.5h.5M55.1 49.5l-.5 .5M55.1 46.5v1h-2M55.1 49.5v.5M55.1 50.5l1 1-1 1zM55.1 51.5h-2.1v1.3"/>
<path d="M55.6 49.5h.5M56.1 49.5l-.5 .5M56.1 49.5v.5M56.1 50.5v2M56.1 48h2M56.1 51.5h2v1.3M56.8 47.2h.5l-.2 .3zM58.1 45v2.5h-2v-1"/>
</g>
<path d="M178.6 32.2l1 .8-.7 .5z" fill="#00f"/>
<g fill="none" stroke="#00f" stroke-width=".25">
<path d="M178.1 34.5h4.1M178.1 35.5h4.1M178.6 32.2l1 .8-.7 .5zM180.1 33.7v.8M180.1 35.5v.8"/>
<circle cx="17.5" cy="28.7" r="2.54"/>
</g>
<path d="M17.5 38.8v2.6M14.9 41.4h5.1M15.7 42.1h3.5M16.4 42.9h2.1M17.2 43.6h.5" fill="none" stroke="#800000" stroke-width=".25"/>
<path d="M17.5 28.7h5M17.5 31.2v2.5" fill="none" stroke="#000" stroke-width=".25"/>
<circle cx="17.5" cy="28.7" r=".64" fill="#00f"/>
<circle cx="17.5" cy="28.7" r=".64" fill="none" stroke="#00f" stroke-width=".21"/>
<circle cx="83.5" cy="61.7" r=".51" fill="#000080"/>
<circle cx="83.5" cy="61.7" r=".51" fill="none" stroke="#000080" stroke-width=".21"/>
<path d="M83.5 59.1v2.6" fill="none" stroke="#000" stroke-width=".25"/>
<circle cx="83.5" cy="61.7" r=".51" fill="#000080"/>
<circle cx="83.5" cy="61.7" r=".51" fill="none" stroke="#000080" stroke-width=".21"/>
<circle cx="83.5" cy="57.9" r="1.27" fill="none" stroke="#000" stroke-width=".25"/>
<path d="M12.4 150.6h5.1M13.1 151.3h3.6M13.9 152.1h2M14.7 152.8h.5M14.9 148v2.6" fill="none" stroke="#800000" stroke-width=".25"/>
<path d="M27.6 127.7l20.4 10.2-20.4 10.1z" fill="#ffffb0"/>
<path d="M27.6 127.7l20.4 10.2-20.4 10.1z" fill="none" stroke="#800000" stroke-width=".21"/>
<g fill="none" stroke="#000" stroke-width=".25">
<path d="M35.2 115h2.1M43.4 115h2M50.5 115h2.5M58.1 115h2.6M14.9 120.1v2M14.9 128.2v2M14.9 135.3v2M20 132.8h7.6M32.7 122.6v7.6M48 137.9h7.6M60.7 137.9h2M68.8 137.9h2"/>
<path d="M144.6 120.1v2M144.6 128.2v2M147.1 132.8h2M155.3 132.8h2M159.8 135.3v2.6M14.9 143.5v2M20 142.9h7.6M32.7 145.5v7.6M37.8 142.9v7.7M42.9 140.4v7.6M144.6 142.9v2M144.6 151.1v2"/>
<path d="M144.6 158.2v2M159.8 142.9v2.6M37.8 160.7h2.5M45.4 160.7h2.6M144.6 166.3v2M223.4 160.7v2.6M223.4 168.3v2.6M233.5 160.7v2.6M233.5 168.3v2.6M243.7 160.7v2.6M243.7 168.3v2.6M253.9 160.7v2.6"/>
<path d="M253.9 168.3v2.6M264 160.7v2.6M264 168.3v2.6"/>
</g>
<path d="M36.8 149.5l2 2.1M38.8 149.5l-2 2.1M41.9 147l2 2M43.9 147l-2 2" fill="none" stroke="#f00" stroke-width=".21"/>
<g fill="none" stroke="#00f" stroke-width=".25">
<path d="M37.3 114h6v2.1h-6zM53 115h2.1M55.1 113v4M56.1 115h2M56.1 113v4M13.9 122.2h2.1v6h-2.1zM13.9 137.4h2.1v6h-2.1zM62.7 136.8h6.1v2h-6.1zM143.6 122.2h2v6h-2zM149.2 131.7h6v2.1h-6zM157.8 139.9h4M159.8 137.9v2"/>
<path d="M42.4 158.7v4M43.4 158.7v4M143.6 145h2v6h-2zM157.8 140.9h4M159.8 140.9v2M40.3 160.7h2.1M43.4 160.7h2M143.6 160.3h2v6h-2zM221.4 165.3h4M221.4 166.3h4M223.4 163.3v2M223.4 166.3v2"/>
<path d="M231.5 165.3h4M231.5 166.3h4M233.5 163.3v2M233.5 166.3v2M241.7 165.3h4M241.7 166.3h4M243.7 163.3v2M243.7 166.3v2M251.9 165.3h4M251.9 166.3h4M253.9 163.3v2M253.9 166.3v2"/>
<path d="M262 165.3h4M262 166.3h4M264 163.3v2M264 166.3v2"/>
</g>
<g fill="none" stroke="#800000" stroke-width=".25">
<path d="M31.4 120.1h2.6M32.7 120.1v2.5M158.5 127.7h2.6M159.8 127.7v2.5M31.4 155.6h2.6M32.7 153.1v2.5M157.3 148h5M158 148.8h3.6M158.8 149.5h2M159.5 150.3h.6M159.8 145.5v2.5M142 173.4h5.1"/>
<path d="M142.8 174.2h3.5M143.5 174.9h2.1M144.3 175.7h.5M144.6 170.9v2.5"/>
</g>
<path d="M88.6 102.3h25.5v38.1h-25.5z" fill-rule="evenodd" fill="#ffffb0"/>
<path d="M88.6 102.3h25.5v38.1h-25.5z" fill="none" stroke="#800000" stroke-width=".21"/>
<g fill="none" stroke="#000" stroke-width=".25">
<path d="M81 109.9h7.6M81 115h7.6M81 107.4h7.6M81 104.8h7.6M114.1 115h7.6M154.7 115h2M162.9 115h2M68.3 120.1h2M76.5 120.1h2M81 120.1h7.6M81 125.2h7.6M81 130.2h7.6"/>
<path d="M81 132.8h7.6M81 135.3h7.6M81 137.9h7.6M114.1 120.1h9.6M114.1 125.2h7.6M114.1 130.2h7.6M114.1 132.8h7.6M114.1 135.3h7.6M114.1 137.9h7.6M129.8 120.1h2M73.4 140.4v2.5M73.4 148v2.6"/>
<path d="M124.2 140.4v2M124.2 148.6v2M159.8 158.2v2M154.7 163.3h4.1M159.8 166.3v2M213.2 160.7v2.6M213.2 168.3v2.6M213.2 176v2.5M223.4 176v2.5M233.5 176v2.5M243.7 176v2.5M253.9 176v2.5"/>
<path d="M264 176v2.5M213.2 183.6v2.5M223.4 183.6v2.5M233.5 183.6v2.5M243.7 183.6v2.5M253.9 183.6v2.5M264 183.6v2.5"/>
</g>
<path d="M80 129.2l2 2.1M80 131.8l2 2M80 134.3l2 2M82 129.2l-2 2.1M82 131.8l-2 2M82 134.3l-2 2M158.8 157.2l2 2M160.8 157.2l-2 2" fill="none" stroke="#f00" stroke-width=".21"/>
<g fill="none" stroke="#800000" stroke-width=".25">
<path d="M77.2 97.2h2.5M78.5 97.2v2.6M70.8 155.6h5.1M71.6 156.4h3.6M72.4 157.2h2M73.1 157.9h.5M73.4 153.1v2.5M78.5 155.6h5M79.2 156.4h3.6M80 157.2h2M80.8 157.9h.5M81 153.1v2.5"/>
<path d="M121.7 158.2h5.1M122.4 158.9h3.6M123.2 159.7h2M124.2 155.6v2.6M133.1 158.2h2.6M134.4 155.6v2.6M203 156.9v2.6M203 158.2h2.6M124 160.5h.5M157.3 173.4h5M158 174.2h3.6M158.8 174.9h2"/>
<path d="M159.6 175.7h.5M159.8 170.9v2.5M203 187.4v2.5M203 188.7h2.6"/>
</g>
<g fill="none" stroke="#00f" stroke-width=".25">
<path d="M70.4 119h6v2.1h-6zM123.8 119.1h6v2h-6zM156.8 114h6v2.1h-6zM71.4 146h4M71.4 145h4M73.4 142.9v2.1M73.4 146v2M123.2 142.5h2.1v6h-2.1zM158.8 160.3h2.1v6h-2.1zM211.2 166.3h4M211.2 165.3h4M213.2 163.3v2"/>
<path d="M213.2 166.3v2M213.2 178.5v2M223.4 178.5v2M233.5 178.5v2M243.7 178.5v2M253.9 178.5v2M264 178.5v2M211.2 181.5h4M211.2 180.5h4M213.2 181.5v2.1M221.4 181.5h4M221.4 180.5h4"/>
<path d="M223.4 181.5v2.1M231.5 181.5h4M231.5 180.5h4M233.5 181.5v2.1M241.7 181.5h4M241.7 180.5h4M243.7 181.5v2.1M251.9 181.5h4M251.9 180.5h4M253.9 181.5v2.1M262 181.5h4M262 180.5h4"/>
<path d="M264 181.5v2.1"/>
</g>
<path d="M158 162.5l.8 .8-.8 .7z" fill="#000"/>
<path d="M158 162.5l.8 .8-.8 .7z" fill="none" stroke="#000" stroke-width=".21"/>
<path d="M203 99.8h30.5v38.1h-30.5z" fill-rule="evenodd" fill="#ffffb0"/>
<path d="M203 99.8h30.5v38.1h-30.5z" fill="none" stroke="#800000" stroke-width=".21"/>
<path d="M195.4 102.3h7.6M195.4 104.9h7.6M195.4 107.4h7.6M233.5 107.4h7.7M233.5 122.6h7.7" fill="none" stroke="#000" stroke-width=".25"/>
<path d="M233.5 122.6l1.5-.5v1z" fill="#f8fcff"/>
<path d="M233.5 122.6l1.5-.5v1z" fill="none" stroke="#000" stroke-width=".21"/>
<path d="M233.5 117.6h7.7M233.5 115h7.7M233.5 127.7h7.7M233.5 130.3h7.7M233.5 135.3h7.7" fill="none" stroke="#000" stroke-width=".25"/>
<path d="M233.5 135.3l1.5-.5v1z" fill="#f8fcff"/>
<path d="M233.5 135.3l1.5-.5v1z" fill="none" stroke="#000" stroke-width=".21"/>
<path d="M195.4 115h7.6M195.4 117.6h7.6M233.5 102.3h7.7M233.5 104.9h7.7M195.4 135.3h7.6M195.4 132.8h7.6M195.4 130.3h7.6" fill="none" stroke="#000" stroke-width=".25"/>
<path d="M170 101h14l1.2 1.3-1.2 1.3h-14z" fill-rule="evenodd" fill="#ffff80"/>
<path d="M170 101h14l1.2 1.3-1.2 1.3h-14z" fill="none" stroke="#800000" stroke-width=".21"/>
<path d="M192.9 89.6v2M192.9 97.8v2" fill="none" stroke="#000" stroke-width=".25"/>
<path d="M191.9 91.7h2v6h-2z" fill="none" stroke="#00f" stroke-width=".25"/>
<path d="M191.6 84.5h2.5M192.9 84.5v2.6" fill="none" stroke="#800000" stroke-width=".25"/>
<path d="M170 106.1h14l1.2 1.3-1.2 1.3h-14z" fill-rule="evenodd" fill="#ffff80"/>
<path d="M170 106.1h14l1.2 1.3-1.2 1.3h-14z" fill="none" stroke="#800000" stroke-width=".21"/>
<path d="M170 103.6h14l1.2 1.3-1.2 1.2h-14z" fill-rule="evenodd" fill="#ffff80"/>
<path d="M170 103.6h14l1.2 1.3-1.2 1.2h-14z" fill="none" stroke="#800000" stroke-width=".21"/>
<path d="M192.9 137.9v2.5M190.3 140.4h5.1M191.1 141.2h3.5M191.8 141.9h2.1M192.6 142.7h.5" fill="none" stroke="#800000" stroke-width=".25"/>
<path d="M243.7 122.6l1.3-1.2h8.9v2.5h-8.9z" fill-rule="evenodd" fill="#ffff80"/>
<path d="M243.7 122.6l1.3-1.2h8.9v2.5h-8.9z" fill="none" stroke="#800000" stroke-width=".21"/>
<path d="M250 102.3h2.6M251.3 102.3v2.6M180.1 158.2h5.1M180.9 158.9h3.6M181.7 159.7h2M182.7 155.6v2.6M182.4 160.5h.5" fill="none" stroke="#800000" stroke-width=".25"/>
<path d="M182.7 125.2v2M182.7 133.3v2M182.7 142.9v2M182.7 151.1v2" fill="none" stroke="#000" stroke-width=".25"/>
<path d="M181.7 127.3h2v5.9h-2zM181.7 145h2v6h-2z" fill="none" stroke="#00f" stroke-width=".25"/>
<path d="M240.1 126.7l2.1 2M240.1 129.2l2.1 2.1M240.1 134.3l2.1 2M242.2 126.7l-2.1 2M242.2 129.2l-2.1 2.1M242.2 134.3l-2.1 2" fill="none" stroke="#f00" stroke-width=".21"/>
<path d="M170 136.6h8.9l1.2 1.3-1.2 1.2h-8.9z" fill-rule="evenodd" fill="#ffff80"/>
<path d="M170 136.6h8.9l1.2 1.3-1.2 1.2h-8.9z" fill="none" stroke="#800000" stroke-width=".21"/>
<path d="M181.4 120.1h2.6M182.7 120.1v2.5" fill="none" stroke="#800000" stroke-width=".25"/>
<circle cx="187.8" cy="122.6" r=".51" fill="#000080"/>
<circle cx="187.8" cy="122.6" r=".51" fill="none" stroke="#000080" stroke-width=".21"/>
<path d="M187.8 122.6h2.5" fill="none" stroke="#000" stroke-width=".25"/>
<circle cx="187.8" cy="122.6" r=".51" fill="#000080"/>
<circle cx="187.8" cy="122.6" r=".51" fill="none" stroke="#000080" stroke-width=".21"/>
<circle cx="191.6" cy="122.6" r="1.27" fill="none" stroke="#000" stroke-width=".25"/>
<path d="M274.2 113.7h11.4l1.3 1.3-1.3 1.3h-11.4z" fill-rule="evenodd" fill="#ffff80"/>
<path d="M274.2 113.7h11.4l1.3 1.3-1.3 1.3h-11.4z" fill="none" stroke="#800000" stroke-width=".21"/>
<path d="M274.2 116.3h11.4l1.3 1.3-1.3 1.2h-11.4z" fill-rule="evenodd" fill="#ffff80"/>
<path d="M274.2 116.3h11.4l1.3 1.3-1.3 1.2h-11.4z" fill="none" stroke="#800000" stroke-width=".21"/>
<path d="M261.5 115h2M261.5 117.6h2M269.7 115h1.9M269.7 117.6h1.9M248.8 132.8h5.1M248.8 135.3v2.6" fill="none" stroke="#000" stroke-width=".25"/>
<g fill="none" stroke="#00f" stroke-width=".25">
<path d="M263.6 114h6v2.1h-6zM263.6 116.6h6v2h-6z"/>
<circle cx="248.8" cy="132.8" r="2.54"/>
</g>
<circle cx="248.8" cy="132.8" r=".63" fill="#00f"/>
<circle cx="248.8" cy="132.8" r=".63" fill="none" stroke="#00f" stroke-width=".21"/>
<path d="M248.8 137.9v2.5M246.2 140.4h5.1M247 141.2h3.6M247.8 141.9h2M248.5 142.7h.5" fill="none" stroke="#800000" stroke-width=".25"/>
<circle cx="266.6" cy="132.8" r="2.54" fill="none" stroke="#00f" stroke-width=".25"/>
<path d="M261.5 132.8h5.1M266.6 135.3v2.6" fill="none" stroke="#000" stroke-width=".25"/>
<circle cx="266.6" cy="132.8" r=".63" fill="#00f"/>
<circle cx="266.6" cy="132.8" r=".63" fill="none" stroke="#00f" stroke-width=".21"/>
<path d="M266.6 137.9v2.5M264 140.4h5.1M264.8 141.2h3.6M265.6 141.9h2M266.3 142.7h.5" fill="none" stroke="#800000" stroke-width=".25"/>
<path d="M252.8 113.4h1.1l.5-.5h1l.5 .5h1M252.8 114h1.1l.5 .5h1l.5-.5h1" fill="none" stroke="#d0a19e" stroke-width=".25"/>
<path d="M252.8 114l-1.5 1" fill="none" stroke="#d0a19e" stroke-width=".21"/>
<path d="M252.6 113.1h1l.5-.5h1l.5 .5h1.1M252.6 113.7h1l.5 .5h1l.5-.5h1.1" fill="none" stroke="#f00" stroke-width=".25"/>
<path d="M252.6 113.7l-1.3 1.3" fill="none" stroke="#f00" stroke-width=".21"/>
<circle cx="187.8" cy="102.3" r=".51" fill="#000080"/>
<circle cx="187.8" cy="102.3" r=".51" fill="none" stroke="#000080" stroke-width=".21"/>
<path d="M187.8 99.8v2.5" fill="none" stroke="#000" stroke-width=".25"/>
<circle cx="187.8" cy="102.3" r=".51" fill="#000080"/>
<circle cx="187.8" cy="102.3" r=".51" fill="none" stroke="#000080" stroke-width=".21"/>
<g fill="none" stroke="#000" stroke-width=".25">
<path d="M233.5 61.7v2.5M233.5 69.3v2.5M251.3 61.7v2.5M251.3 69.3v2.5M258.9 61.7v2.5M258.9 69.3v2.5M266.6 61.7v2.5M266.6 69.3v2.5M274.2 61.7v2.5M274.2 69.3v2.5M129.3 140.4v2M129.3 148.6v2"/>
<circle cx="187.8" cy="98.5" r="1.27"/>
</g>
<g fill="none" stroke="#00f" stroke-width=".25">
<path d="M231.5 67.3h4M231.5 66.3h4M233.5 64.2v2.1M233.5 67.3v2M249.3 67.3h4M249.3 66.3h4M251.3 64.2v2.1M251.3 67.3v2M256.9 67.3h4M256.9 66.3h4M258.9 64.2v2.1M258.9 67.3v2"/>
<path d="M264.6 67.3h4M264.6 66.3h4M266.6 64.2v2.1M266.6 67.3v2M272.2 67.3h4M272.2 66.3h4M274.2 64.2v2.1M274.2 67.3v2M128.3 142.5h2.1v6h-2.1z"/>
</g>
<g fill="none" stroke="#800000" stroke-width=".25">
<path d="M232.3 54.1h2.5M233.5 54.1v2.5M280.6 54.1h2.5M281.8 54.1v2.5M231 74.4h5.1M231.8 75.1h3.5M232.5 75.9h2M233.3 76.7h.5M233.5 71.8v2.6M248.8 74.4h5.1M249.5 75.1h3.6M250.3 75.9h2"/>
<path d="M251.1 76.7h.5M251.3 71.8v2.6M256.4 74.4h5.1M257.2 75.1h3.5M257.9 75.9h2.1M258.7 76.7h.5M258.9 71.8v2.6M264 74.4h5.1M264.8 75.1h3.6M265.6 75.9h2M266.3 76.7h.5M266.6 71.8v2.6"/>
<path d="M271.6 74.4h5.1M272.4 75.1h3.6M273.2 75.9h2M273.9 76.7h.6M274.2 71.8v2.6M245 97.2h2.5M246.2 97.2v2.6M203.3 173.2v.5M204 172.4v2M204.8 171.6v3.6M205.6 170.9v5.1M205.6 173.4h2.5"/>
</g>
<path d="M252.8 115.9h1.1l.5-.5h1l.5 .5h1M252.8 116.5h1.1l.5 .5h1l.5-.5h1" fill="none" stroke="#d0a19e" stroke-width=".25"/>
<path d="M252.8 116.5l-1.5 1.1" fill="none" stroke="#d0a19e" stroke-width=".21"/>
<path d="M252.6 115.6h1l.5-.5h1l.5 .5h1.1M252.6 116.3h1l.5 .5h1l.5-.5h1.1" fill="none" stroke="#f00" stroke-width=".25"/>
<path d="M252.6 116.3l-1.3 1.3" fill="none" stroke="#f00" stroke-width=".21"/>
<path d="M65.7 28.7h25.5M180.1 38.8v2.6" fill="none" stroke="#000080" stroke-width=".25"/>
<circle cx="65.8" cy="28.7" r=".51" fill="#000080"/>
<circle cx="65.8" cy="28.7" r=".51" fill="none" stroke="#000080" stroke-width=".21"/>
<path d="M81 61.7h5.1" fill="none" stroke="#000080" stroke-width=".25"/>
<circle cx="86.1" cy="61.7" r=".51" fill="#000080"/>
<circle cx="86.1" cy="61.7" r=".51" fill="none" stroke="#000080" stroke-width=".21"/>
<circle cx="83.5" cy="61.7" r=".51" fill="#000080"/>
<circle cx="83.5" cy="61.7" r=".51" fill="none" stroke="#000080" stroke-width=".21"/>
<path d="M88.6 61.7h-2.5v2.5" fill="none" stroke="#000080" stroke-width=".25"/>
<circle cx="86.1" cy="61.7" r=".51" fill="#000080"/>
<circle cx="86.1" cy="61.7" r=".51" fill="none" stroke="#000080" stroke-width=".21"/>
<path d="M86.1 41.4v10.1h5.1" fill="none" stroke="#000080" stroke-width=".25"/>
<circle cx="86.1" cy="41.4" r=".51" fill="#000080"/>
<circle cx="86.1" cy="41.4" r=".51" fill="none" stroke="#000080" stroke-width=".21"/>
<path d="M86.1 38.8v2.6h5.1" fill="none" stroke="#000080" stroke-width=".25"/>
<circle cx="86.1" cy="41.4" r=".51" fill="#000080"/>
<circle cx="86.1" cy="41.4" r=".51" fill="none" stroke="#000080" stroke-width=".21"/>
<path d="M101.3 51.5h7.7M98.8 61.7h2.5" fill="none" stroke="#000080" stroke-width=".25"/>
<circle cx="109" cy="51.5" r=".51" fill="#000080"/>
<circle cx="109" cy="51.5" r=".51" fill="none" stroke="#000080" stroke-width=".21"/>
<path d="M101.3 26.1h58.5M103.9 31.2v5.1h15.2" fill="none" stroke="#000080" stroke-width=".25"/>
<circle cx="103.9" cy="31.2" r=".51" fill="#000080"/>
<circle cx="103.9" cy="31.2" r=".51" fill="none" stroke="#000080" stroke-width=".21"/>
<path d="M144.6 31.2v5.1h-15.3" fill="none" stroke="#000080" stroke-width=".25"/>
<circle cx="144.6" cy="31.2" r=".51" fill="#000080"/>
<circle cx="144.6" cy="31.2" r=".51" fill="none" stroke="#000080" stroke-width=".21"/>
<path d="M167.4 59.1v2.6h-10.1" fill="none" stroke="#000080" stroke-width=".25"/>
<circle cx="157.3" cy="61.7" r=".51" fill="#000080"/>
<circle cx="157.3" cy="61.7" r=".51" fill="none" stroke="#000080" stroke-width=".21"/>
<path d="M157.3 46.4h10.1v2.6" fill="none" stroke="#000080" stroke-width=".25"/>
<circle cx="157.3" cy="46.4" r=".51" fill="#000080"/>
<circle cx="157.3" cy="46.4" r=".51" fill="none" stroke="#000080" stroke-width=".21"/>
<path d="M35.2 28.7v2.5M35.2 41.4v2.5" fill="none" stroke="#000080" stroke-width=".25"/>
<circle cx="35.2" cy="28.7" r=".51" fill="#000080"/>
<circle cx="35.2" cy="28.7" r=".51" fill="none" stroke="#000080" stroke-width=".21"/>
<path d="M180.1 28.7v2.5M149.6 59.1v7.7M58.1 74.4v2.5M86.1 74.4v2.5M109 66.8v10.1" fill="none" stroke="#000080" stroke-width=".25"/>
<circle cx="180.1" cy="28.7" r=".51" fill="#000080"/>
<circle cx="180.1" cy="28.7" r=".51" fill="none" stroke="#000080" stroke-width=".21"/>
<path d="M149.6 31.2v17.8M58.1 54.1v10.1" fill="none" stroke="#000080" stroke-width=".25"/>
<circle cx="149.6" cy="31.2" r=".51" fill="#000080"/>
<circle cx="149.6" cy="31.2" r=".51" fill="none" stroke="#000080" stroke-width=".21"/>
<path d="M17.5 33.7v5.1M22.5 28.7h28M119.1 31.2h10.2" fill="none" stroke="#000080" stroke-width=".25"/>
<circle cx="35.2" cy="28.7" r=".51" fill="#000080"/>
<circle cx="35.2" cy="28.7" r=".51" fill="none" stroke="#000080" stroke-width=".21"/>
<circle cx="45.4" cy="28.7" r=".51" fill="#000080"/>
<circle cx="45.4" cy="28.7" r=".51" fill="none" stroke="#000080" stroke-width=".21"/>
<path d="M101.3 41.4h7.7v15.2" fill="none" stroke="#000080" stroke-width=".25"/>
<circle cx="109" cy="51.5" r=".51" fill="#000080"/>
<circle cx="109" cy="51.5" r=".51" fill="none" stroke="#000080" stroke-width=".21"/>
<path d="M101.3 31.2h7.7" fill="none" stroke="#000080" stroke-width=".25"/>
<circle cx="103.9" cy="31.2" r=".51" fill="#000080"/>
<circle cx="103.9" cy="31.2" r=".51" fill="none" stroke="#000080" stroke-width=".21"/>
<path d="M139.5 31.2h20.3" fill="none" stroke="#000080" stroke-width=".25"/>
<circle cx="144.6" cy="31.2" r=".51" fill="#000080"/>
<circle cx="144.6" cy="31.2" r=".51" fill="none" stroke="#000080" stroke-width=".21"/>
<circle cx="149.6" cy="31.2" r=".51" fill="#000080"/>
<circle cx="149.6" cy="31.2" r=".51" fill="none" stroke="#000080" stroke-width=".21"/>
<circle cx="157.3" cy="31.2" r=".51" fill="#000080"/>
<circle cx="157.3" cy="31.2" r=".51" fill="none" stroke="#000080" stroke-width=".21"/>
<path d="M157.3 59.1v7.7" fill="none" stroke="#000080" stroke-width=".25"/>
<circle cx="157.3" cy="61.7" r=".51" fill="#000080"/>
<circle cx="157.3" cy="61.7" r=".51" fill="none" stroke="#000080" stroke-width=".21"/>
<path d="M157.3 31.2v17.8" fill="none" stroke="#000080" stroke-width=".25"/>
<circle cx="157.3" cy="46.4" r=".51" fill="#000080"/>
<circle cx="157.3" cy="46.4" r=".51" fill="none" stroke="#000080" stroke-width=".21"/>
<circle cx="157.3" cy="31.2" r=".51" fill="#000080"/>
<circle cx="157.3" cy="31.2" r=".51" fill="none" stroke="#000080" stroke-width=".21"/>
<path d="M159.8 132.8v2.5" fill="none" stroke="#000080" stroke-width=".25"/>
<circle cx="159.8" cy="132.8" r=".51" fill="#000080"/>
<circle cx="159.8" cy="132.8" r=".51" fill="none" stroke="#000080" stroke-width=".21"/>
<path d="M20 132.8h-5.1v2.5" fill="none" stroke="#000080" stroke-width=".25"/>
<circle cx="14.9" cy="132.8" r=".51" fill="#000080"/>
<circle cx="14.9" cy="132.8" r=".51" fill="none" stroke="#000080" stroke-width=".21"/>
<path d="M55.6 137.9h2.5v22.8h-10.1" fill="none" stroke="#000080" stroke-width=".25"/>
<circle cx="58.1" cy="137.9" r=".51" fill="#000080"/>
<circle cx="58.1" cy="137.9" r=".51" fill="none" stroke="#000080" stroke-width=".21"/>
<path d="M144.6 132.8h2.5" fill="none" stroke="#000080" stroke-width=".25"/>
<circle cx="144.6" cy="132.8" r=".51" fill="#000080"/>
<circle cx="144.6" cy="132.8" r=".51" fill="none" stroke="#000080" stroke-width=".21"/>
<path d="M213.2 158.2v2.5" fill="none" stroke="#000080" stroke-width=".25"/>
<circle cx="213.2" cy="158.2" r=".51" fill="#000080"/>
<circle cx="213.2" cy="158.2" r=".51" fill="none" stroke="#000080" stroke-width=".21"/>
<path d="M233.5 158.2v2.5" fill="none" stroke="#000080" stroke-width=".25"/>
<circle cx="233.5" cy="158.2" r=".51" fill="#000080"/>
<circle cx="233.5" cy="158.2" r=".51" fill="none" stroke="#000080" stroke-width=".21"/>
<path d="M243.7 158.2v2.5" fill="none" stroke="#000080" stroke-width=".25"/>
<circle cx="243.7" cy="158.2" r=".51" fill="#000080"/>
<circle cx="243.7" cy="158.2" r=".51" fill="none" stroke="#000080" stroke-width=".21"/>
<path d="M14.9 130.2v2.6M14.9 145.5v2.5" fill="none" stroke="#000080" stroke-width=".25"/>
<circle cx="14.9" cy="132.8" r=".51" fill="#000080"/>
<circle cx="14.9" cy="132.8" r=".51" fill="none" stroke="#000080" stroke-width=".21"/>
<path d="M253.9 158.2v2.5" fill="none" stroke="#000080" stroke-width=".25"/>
<circle cx="253.9" cy="158.2" r=".51" fill="#000080"/>
<circle cx="253.9" cy="158.2" r=".51" fill="none" stroke="#000080" stroke-width=".21"/>
<path d="M45.4 115h5.1M58.1 137.9h2.6M144.6 168.3v2.6" fill="none" stroke="#000080" stroke-width=".25"/>
<circle cx="58.1" cy="137.9" r=".51" fill="#000080"/>
<circle cx="58.1" cy="137.9" r=".51" fill="none" stroke="#000080" stroke-width=".21"/>
<path d="M35.2 115h-20.3v5.1M81 137.9v15.2M124.2 137.9v2.5" fill="none" stroke="#000080" stroke-width=".25"/>
<circle cx="124.2" cy="137.9" r=".51" fill="#000080"/>
<circle cx="124.2" cy="137.9" r=".51" fill="none" stroke="#000080" stroke-width=".21"/>
<path d="M131.8 120.1h2.6v5.1M124.2 150.6v5" fill="none" stroke="#000080" stroke-width=".25"/>
<circle cx="134.4" cy="125.2" r=".51" fill="#000080"/>
<circle cx="134.4" cy="125.2" r=".51" fill="none" stroke="#000080" stroke-width=".21"/>
<path d="M78.5 107.4h2.5" fill="none" stroke="#000080" stroke-width=".25"/>
<circle cx="78.5" cy="107.4" r=".51" fill="#000080"/>
<circle cx="78.5" cy="107.4" r=".51" fill="none" stroke="#000080" stroke-width=".21"/>
<path d="M78.5 104.8h2.5" fill="none" stroke="#000080" stroke-width=".25"/>
<circle cx="78.5" cy="104.8" r=".51" fill="#000080"/>
<circle cx="78.5" cy="104.8" r=".51" fill="none" stroke="#000080" stroke-width=".21"/>
<path d="M73.4 137.9v2.5" fill="none" stroke="#000080" stroke-width=".25"/>
<circle cx="73.4" cy="137.9" r=".51" fill="#000080"/>
<circle cx="73.4" cy="137.9" r=".51" fill="none" stroke="#000080" stroke-width=".21"/>
<path d="M73.4 150.6v2.5M144.6 155.6h7.6v7.7h2.5M159.8 168.3v2.6" fill="none" stroke="#000080" stroke-width=".25"/>
<circle cx="144.6" cy="155.6" r=".51" fill="#000080"/>
<circle cx="144.6" cy="155.6" r=".51" fill="none" stroke="#000080" stroke-width=".21"/>
<path d="M243.7 186.1v2.6" fill="none" stroke="#000080" stroke-width=".25"/>
<circle cx="243.7" cy="188.7" r=".51" fill="#000080"/>
<circle cx="243.7" cy="188.7" r=".51" fill="none" stroke="#000080" stroke-width=".21"/>
<path d="M233.5 186.1v2.6" fill="none" stroke="#000080" stroke-width=".25"/>
<circle cx="233.5" cy="188.7" r=".51" fill="#000080"/>
<circle cx="233.5" cy="188.7" r=".51" fill="none" stroke="#000080" stroke-width=".21"/>
<path d="M223.4 186.1v2.6" fill="none" stroke="#000080" stroke-width=".25"/>
<circle cx="223.4" cy="188.7" r=".51" fill="#000080"/>
<circle cx="223.4" cy="188.7" r=".51" fill="none" stroke="#000080" stroke-width=".21"/>
<path d="M144.6 115v5.1" fill="none" stroke="#000080" stroke-width=".25"/>
<circle cx="144.6" cy="115" r=".51" fill="#000080"/>
<circle cx="144.6" cy="115" r=".51" fill="none" stroke="#000080" stroke-width=".21"/>
<path d="M65.7 115v5.1h2.6M78.5 120.1h2.5" fill="none" stroke="#000080" stroke-width=".25"/>
<circle cx="65.7" cy="115" r=".51" fill="#000080"/>
<circle cx="65.7" cy="115" r=".51" fill="none" stroke="#000080" stroke-width=".21"/>
<path d="M121.7 132.8h12.7" fill="none" stroke="#000080" stroke-width=".25"/>
<circle cx="134.4" cy="132.8" r=".51" fill="#000080"/>
<circle cx="134.4" cy="132.8" r=".51" fill="none" stroke="#000080" stroke-width=".21"/>
<path d="M164.9 115h30.5M185.2 107.4h10.2M185.2 104.9h10.2M192.9 132.8h2.5" fill="none" stroke="#000080" stroke-width=".25"/>
<circle cx="192.9" cy="132.8" r=".51" fill="#000080"/>
<circle cx="192.9" cy="132.8" r=".51" fill="none" stroke="#000080" stroke-width=".21"/>
<path d="M241.2 102.3h5M241.2 122.6h2.5" fill="none" stroke="#000080" stroke-width=".25"/>
<circle cx="246.2" cy="102.3" r=".51" fill="#000080"/>
<circle cx="246.2" cy="102.3" r=".51" fill="none" stroke="#000080" stroke-width=".21"/>
<path d="M182.7 122.6v2.6M192.9 135.3v2.6M182.7 153.1v2.5" fill="none" stroke="#000080" stroke-width=".25"/>
<circle cx="192.9" cy="135.3" r=".51" fill="#000080"/>
<circle cx="192.9" cy="135.3" r=".51" fill="none" stroke="#000080" stroke-width=".21"/>
<path d="M192.9 99.8v2.5" fill="none" stroke="#000080" stroke-width=".25"/>
<circle cx="192.9" cy="102.3" r=".51" fill="#000080"/>
<circle cx="192.9" cy="102.3" r=".51" fill="none" stroke="#000080" stroke-width=".21"/>
<path d="M192.9 87.1v2.5M195.4 117.6h-7.6v22.8h-5.1" fill="none" stroke="#000080" stroke-width=".25"/>
<circle cx="187.8" cy="122.6" r=".51" fill="#000080"/>
<circle cx="187.8" cy="122.6" r=".51" fill="none" stroke="#000080" stroke-width=".21"/>
<circle cx="182.7" cy="140.4" r=".51" fill="#000080"/>
<circle cx="182.7" cy="140.4" r=".51" fill="none" stroke="#000080" stroke-width=".21"/>
<path d="M78.5 99.8v10.1h2.5" fill="none" stroke="#000080" stroke-width=".25"/>
<circle cx="78.5" cy="107.4" r=".51" fill="#000080"/>
<circle cx="78.5" cy="107.4" r=".51" fill="none" stroke="#000080" stroke-width=".21"/>
<circle cx="78.5" cy="104.8" r=".51" fill="#000080"/>
<circle cx="78.5" cy="104.8" r=".51" fill="none" stroke="#000080" stroke-width=".21"/>
<path d="M195.4 130.3h-2.5v5h2.5" fill="none" stroke="#000080" stroke-width=".25"/>
<circle cx="192.9" cy="132.8" r=".51" fill="#000080"/>
<circle cx="192.9" cy="132.8" r=".51" fill="none" stroke="#000080" stroke-width=".21"/>
<circle cx="192.9" cy="135.3" r=".51" fill="#000080"/>
<circle cx="192.9" cy="135.3" r=".51" fill="none" stroke="#000080" stroke-width=".21"/>
<path d="M246.2 99.8v5.1h-5M251.3 104.9v2.5h-10.1" fill="none" stroke="#000080" stroke-width=".25"/>
<circle cx="246.2" cy="102.3" r=".51" fill="#000080"/>
<circle cx="246.2" cy="102.3" r=".51" fill="none" stroke="#000080" stroke-width=".21"/>
<path d="M159.8 130.2v2.6h-2.5" fill="none" stroke="#000080" stroke-width=".25"/>
<circle cx="159.8" cy="132.8" r=".51" fill="#000080"/>
<circle cx="159.8" cy="132.8" r=".51" fill="none" stroke="#000080" stroke-width=".21"/>
<path d="M256.4 117.6v15.2h-2.5M271.6 115h2.6M271.6 117.6h2.6" fill="none" stroke="#000080" stroke-width=".25"/>
<circle cx="256.4" cy="117.6" r=".51" fill="#000080"/>
<circle cx="256.4" cy="117.6" r=".51" fill="none" stroke="#000080" stroke-width=".21"/>
<path d="M274.2 59.1v2.6" fill="none" stroke="#000080" stroke-width=".25"/>
<circle cx="274.2" cy="59.1" r=".51" fill="#000080"/>
<circle cx="274.2" cy="59.1" r=".51" fill="none" stroke="#000080" stroke-width=".21"/>
<path d="M258.9 59.1h-7.6v2.6" fill="none" stroke="#000080" stroke-width=".25"/>
<circle cx="258.9" cy="59.1" r=".51" fill="#000080"/>
<circle cx="258.9" cy="59.1" r=".51" fill="none" stroke="#000080" stroke-width=".21"/>
<path d="M266.6 59.1h-7.7v2.6" fill="none" stroke="#000080" stroke-width=".25"/>
<circle cx="258.9" cy="59.1" r=".51" fill="#000080"/>
<circle cx="258.9" cy="59.1" r=".51" fill="none" stroke="#000080" stroke-width=".21"/>
<circle cx="266.6" cy="59.1" r=".51" fill="#000080"/>
<circle cx="266.6" cy="59.1" r=".51" fill="none" stroke="#000080" stroke-width=".21"/>
<path d="M233.5 56.6v5.1M281.8 56.6v2.5h-15.2v2.6" fill="none" stroke="#000080" stroke-width=".25"/>
<circle cx="266.6" cy="59.1" r=".51" fill="#000080"/>
<circle cx="266.6" cy="59.1" r=".51" fill="none" stroke="#000080" stroke-width=".21"/>
<circle cx="274.2" cy="59.1" r=".51" fill="#000080"/>
<circle cx="274.2" cy="59.1" r=".51" fill="none" stroke="#000080" stroke-width=".21"/>
<path d="M223.4 158.2h40.6v2.5" fill="none" stroke="#000080" stroke-width=".25"/>
<circle cx="223.4" cy="158.2" r=".51" fill="#000080"/>
<circle cx="223.4" cy="158.2" r=".51" fill="none" stroke="#000080" stroke-width=".21"/>
<circle cx="233.5" cy="158.2" r=".51" fill="#000080"/>
<circle cx="233.5" cy="158.2" r=".51" fill="none" stroke="#000080" stroke-width=".21"/>
<circle cx="243.7" cy="158.2" r=".51" fill="#000080"/>
<circle cx="243.7" cy="158.2" r=".51" fill="none" stroke="#000080" stroke-width=".21"/>
<circle cx="253.9" cy="158.2" r=".51" fill="#000080"/>
<circle cx="253.9" cy="158.2" r=".51" fill="none" stroke="#000080" stroke-width=".21"/>
<path d="M205.6 158.2h17.8v2.5" fill="none" stroke="#000080" stroke-width=".25"/>
<circle cx="213.2" cy="158.2" r=".51" fill="#000080"/>
<circle cx="213.2" cy="158.2" r=".51" fill="none" stroke="#000080" stroke-width=".21"/>
<circle cx="223.4" cy="158.2" r=".51" fill="#000080"/>
<circle cx="223.4" cy="158.2" r=".51" fill="none" stroke="#000080" stroke-width=".21"/>
<path d="M60.7 115h20.3" fill="none" stroke="#000080" stroke-width=".25"/>
<circle cx="65.7" cy="115" r=".51" fill="#000080"/>
<circle cx="65.7" cy="115" r=".51" fill="none" stroke="#000080" stroke-width=".21"/>
<path d="M121.7 137.9h7.6v2.5" fill="none" stroke="#000080" stroke-width=".25"/>
<circle cx="124.2" cy="137.9" r=".51" fill="#000080"/>
<circle cx="124.2" cy="137.9" r=".51" fill="none" stroke="#000080" stroke-width=".21"/>
<path d="M121.7 125.2h12.7v5h-12.7" fill="none" stroke="#000080" stroke-width=".25"/>
<circle cx="134.4" cy="130.2" r=".51" fill="#000080"/>
<circle cx="134.4" cy="130.2" r=".51" fill="none" stroke="#000080" stroke-width=".21"/>
<circle cx="134.4" cy="125.2" r=".51" fill="#000080"/>
<circle cx="134.4" cy="125.2" r=".51" fill="none" stroke="#000080" stroke-width=".21"/>
<path d="M134.4 130.2v2.6" fill="none" stroke="#000080" stroke-width=".25"/>
<circle cx="134.4" cy="132.8" r=".51" fill="#000080"/>
<circle cx="134.4" cy="132.8" r=".51" fill="none" stroke="#000080" stroke-width=".21"/>
<circle cx="134.4" cy="130.2" r=".51" fill="#000080"/>
<circle cx="134.4" cy="130.2" r=".51" fill="none" stroke="#000080" stroke-width=".21"/>
<path d="M134.4 132.8v2.5h-12.7" fill="none" stroke="#000080" stroke-width=".25"/>
<circle cx="134.4" cy="135.3" r=".51" fill="#000080"/>
<circle cx="134.4" cy="135.3" r=".51" fill="none" stroke="#000080" stroke-width=".21"/>
<circle cx="134.4" cy="132.8" r=".51" fill="#000080"/>
<circle cx="134.4" cy="132.8" r=".51" fill="none" stroke="#000080" stroke-width=".21"/>
<path d="M134.4 135.3v20.3" fill="none" stroke="#000080" stroke-width=".25"/>
<circle cx="134.4" cy="153.1" r=".51" fill="#000080"/>
<circle cx="134.4" cy="153.1" r=".51" fill="none" stroke="#000080" stroke-width=".21"/>
<circle cx="134.4" cy="135.3" r=".51" fill="#000080"/>
<circle cx="134.4" cy="135.3" r=".51" fill="none" stroke="#000080" stroke-width=".21"/>
<path d="M129.3 150.6v2.5h5.1" fill="none" stroke="#000080" stroke-width=".25"/>
<circle cx="134.4" cy="153.1" r=".51" fill="#000080"/>
<circle cx="134.4" cy="153.1" r=".51" fill="none" stroke="#000080" stroke-width=".21"/>
<path d="M121.7 115h33" fill="none" stroke="#000080" stroke-width=".25"/>
<circle cx="144.6" cy="115" r=".51" fill="#000080"/>
<circle cx="144.6" cy="115" r=".51" fill="none" stroke="#000080" stroke-width=".21"/>
<path d="M144.6 137.9h-5.1v30.4h-119.5v-7.6h17.8" fill="none" stroke="#000080" stroke-width=".25"/>
<circle cx="144.6" cy="137.9" r=".51" fill="#000080"/>
<circle cx="144.6" cy="137.9" r=".51" fill="none" stroke="#000080" stroke-width=".21"/>
<circle cx="20" cy="160.7" r=".51" fill="#000080"/>
<circle cx="20" cy="160.7" r=".51" fill="none" stroke="#000080" stroke-width=".21"/>
<path d="M20 142.9v17.8" fill="none" stroke="#000080" stroke-width=".25"/>
<circle cx="20" cy="160.7" r=".51" fill="#000080"/>
<circle cx="20" cy="160.7" r=".51" fill="none" stroke="#000080" stroke-width=".21"/>
<path d="M81 125.2h-7.6v12.7h-2.6" fill="none" stroke="#000080" stroke-width=".25"/>
<circle cx="73.4" cy="137.9" r=".51" fill="#000080"/>
<circle cx="73.4" cy="137.9" r=".51" fill="none" stroke="#000080" stroke-width=".21"/>
<path d="M170 28.7h25.4" fill="none" stroke="#000080" stroke-width=".25"/>
<circle cx="180.1" cy="28.7" r=".51" fill="#000080"/>
<circle cx="180.1" cy="28.7" r=".51" fill="none" stroke="#000080" stroke-width=".21"/>
<path d="M144.6 153.1v5.1" fill="none" stroke="#000080" stroke-width=".25"/>
<circle cx="144.6" cy="155.6" r=".51" fill="#000080"/>
<circle cx="144.6" cy="155.6" r=".51" fill="none" stroke="#000080" stroke-width=".21"/>
<path d="M144.6 130.2v12.7" fill="none" stroke="#000080" stroke-width=".25"/>
<circle cx="144.6" cy="132.8" r=".51" fill="#000080"/>
<circle cx="144.6" cy="132.8" r=".51" fill="none" stroke="#000080" stroke-width=".21"/>
<circle cx="144.6" cy="137.9" r=".51" fill="#000080"/>
<circle cx="144.6" cy="137.9" r=".51" fill="none" stroke="#000080" stroke-width=".21"/>
<path d="M182.7 140.4v2.5" fill="none" stroke="#000080" stroke-width=".25"/>
<circle cx="182.7" cy="140.4" r=".51" fill="#000080"/>
<circle cx="182.7" cy="140.4" r=".51" fill="none" stroke="#000080" stroke-width=".21"/>
<path d="M180.1 137.9h2.6" fill="none" stroke="#000080" stroke-width=".25"/>
<circle cx="182.7" cy="137.9" r=".51" fill="#000080"/>
<circle cx="182.7" cy="137.9" r=".51" fill="none" stroke="#000080" stroke-width=".21"/>
<path d="M182.7 135.3v5.1" fill="none" stroke="#000080" stroke-width=".25"/>
<circle cx="182.7" cy="140.4" r=".51" fill="#000080"/>
<circle cx="182.7" cy="140.4" r=".51" fill="none" stroke="#000080" stroke-width=".21"/>
<circle cx="182.7" cy="137.9" r=".51" fill="#000080"/>
<circle cx="182.7" cy="137.9" r=".51" fill="none" stroke="#000080" stroke-width=".21"/>
<path d="M258.9 115v17.8h2.6" fill="none" stroke="#000080" stroke-width=".25"/>
<circle cx="258.9" cy="115" r=".51" fill="#000080"/>
<circle cx="258.9" cy="115" r=".51" fill="none" stroke="#000080" stroke-width=".21"/>
<path d="M241.2 117.6h20.3" fill="none" stroke="#000080" stroke-width=".25"/>
<circle cx="256.4" cy="117.6" r=".51" fill="#000080"/>
<circle cx="256.4" cy="117.6" r=".51" fill="none" stroke="#000080" stroke-width=".21"/>
<path d="M241.2 115h20.3" fill="none" stroke="#000080" stroke-width=".25"/>
<circle cx="258.9" cy="115" r=".51" fill="#000080"/>
<circle cx="258.9" cy="115" r=".51" fill="none" stroke="#000080" stroke-width=".21"/>
<path d="M264 170.9v5.1" fill="none" stroke="#000080" stroke-width=".25"/>
<circle cx="264" cy="173.4" r=".51" fill="#000080"/>
<circle cx="264" cy="173.4" r=".51" fill="none" stroke="#000080" stroke-width=".21"/>
<path d="M253.9 173.4h10.1" fill="none" stroke="#000080" stroke-width=".25"/>
<circle cx="264" cy="173.4" r=".51" fill="#000080"/>
<circle cx="264" cy="173.4" r=".51" fill="none" stroke="#000080" stroke-width=".21"/>
<circle cx="253.9" cy="173.4" r=".51" fill="#000080"/>
<circle cx="253.9" cy="173.4" r=".51" fill="none" stroke="#000080" stroke-width=".21"/>
<path d="M243.7 173.4h10.2" fill="none" stroke="#000080" stroke-width=".25"/>
<circle cx="253.9" cy="173.4" r=".51" fill="#000080"/>
<circle cx="253.9" cy="173.4" r=".51" fill="none" stroke="#000080" stroke-width=".21"/>
<circle cx="243.7" cy="173.4" r=".51" fill="#000080"/>
<circle cx="243.7" cy="173.4" r=".51" fill="none" stroke="#000080" stroke-width=".21"/>
<path d="M233.5 173.4h10.2" fill="none" stroke="#000080" stroke-width=".25"/>
<circle cx="243.7" cy="173.4" r=".51" fill="#000080"/>
<circle cx="243.7" cy="173.4" r=".51" fill="none" stroke="#000080" stroke-width=".21"/>
<circle cx="233.5" cy="173.4" r=".51" fill="#000080"/>
<circle cx="233.5" cy="173.4" r=".51" fill="none" stroke="#000080" stroke-width=".21"/>
<path d="M223.4 173.4h10.1" fill="none" stroke="#000080" stroke-width=".25"/>
<circle cx="233.5" cy="173.4" r=".51" fill="#000080"/>
<circle cx="233.5" cy="173.4" r=".51" fill="none" stroke="#000080" stroke-width=".21"/>
<circle cx="223.4" cy="173.4" r=".51" fill="#000080"/>
<circle cx="223.4" cy="173.4" r=".51" fill="none" stroke="#000080" stroke-width=".21"/>
<path d="M213.2 173.4h10.2" fill="none" stroke="#000080" stroke-width=".25"/>
<circle cx="223.4" cy="173.4" r=".51" fill="#000080"/>
<circle cx="223.4" cy="173.4" r=".51" fill="none" stroke="#000080" stroke-width=".21"/>
<circle cx="213.2" cy="173.4" r=".51" fill="#000080"/>
<circle cx="213.2" cy="173.4" r=".51" fill="none" stroke="#000080" stroke-width=".21"/>
<path d="M208.1 173.4h5.1" fill="none" stroke="#000080" stroke-width=".25"/>
<circle cx="213.2" cy="173.4" r=".51" fill="#000080"/>
<circle cx="213.2" cy="173.4" r=".51" fill="none" stroke="#000080" stroke-width=".21"/>
<path d="M264 186.1v2.6h-58.4" fill="none" stroke="#000080" stroke-width=".25"/>
<circle cx="213.2" cy="188.7" r=".51" fill="#000080"/>
<circle cx="213.2" cy="188.7" r=".51" fill="none" stroke="#000080" stroke-width=".21"/>
<circle cx="223.4" cy="188.7" r=".51" fill="#000080"/>
<circle cx="223.4" cy="188.7" r=".51" fill="none" stroke="#000080" stroke-width=".21"/>
<circle cx="233.5" cy="188.7" r=".51" fill="#000080"/>
<circle cx="233.5" cy="188.7" r=".51" fill="none" stroke="#000080" stroke-width=".21"/>
<circle cx="243.7" cy="188.7" r=".51" fill="#000080"/>
<circle cx="243.7" cy="188.7" r=".51" fill="none" stroke="#000080" stroke-width=".21"/>
<circle cx="253.9" cy="188.7" r=".51" fill="#000080"/>
<circle cx="253.9" cy="188.7" r=".51" fill="none" stroke="#000080" stroke-width=".21"/>
<path d="M213.2 186.1v2.6" fill="none" stroke="#000080" stroke-width=".25"/>
<circle cx="213.2" cy="188.7" r=".51" fill="#000080"/>
<circle cx="213.2" cy="188.7" r=".51" fill="none" stroke="#000080" stroke-width=".21"/>
<path d="M253.9 186.1v2.6" fill="none" stroke="#000080" stroke-width=".25"/>
<circle cx="253.9" cy="188.7" r=".51" fill="#000080"/>
<circle cx="253.9" cy="188.7" r=".51" fill="none" stroke="#000080" stroke-width=".21"/>
<path d="M213.2 170.9v5.1" fill="none" stroke="#000080" stroke-width=".25"/>
<circle cx="213.2" cy="173.4" r=".51" fill="#000080"/>
<circle cx="213.2" cy="173.4" r=".51" fill="none" stroke="#000080" stroke-width=".21"/>
<path d="M223.4 170.9v5.1" fill="none" stroke="#000080" stroke-width=".25"/>
<circle cx="223.4" cy="173.4" r=".51" fill="#000080"/>
<circle cx="223.4" cy="173.4" r=".51" fill="none" stroke="#000080" stroke-width=".21"/>
<path d="M233.5 170.9v5.1" fill="none" stroke="#000080" stroke-width=".25"/>
<circle cx="233.5" cy="173.4" r=".51" fill="#000080"/>
<circle cx="233.5" cy="173.4" r=".51" fill="none" stroke="#000080" stroke-width=".21"/>
<path d="M243.7 170.9v5.1" fill="none" stroke="#000080" stroke-width=".25"/>
<circle cx="243.7" cy="173.4" r=".51" fill="#000080"/>
<circle cx="243.7" cy="173.4" r=".51" fill="none" stroke="#000080" stroke-width=".21"/>
<path d="M253.9 170.9v5.1" fill="none" stroke="#000080" stroke-width=".25"/>
<circle cx="253.9" cy="173.4" r=".51" fill="#000080"/>
<circle cx="253.9" cy="173.4" r=".51" fill="none" stroke="#000080" stroke-width=".21"/>
<path d="M185.2 102.3h10.2" fill="none" stroke="#000080" stroke-width=".25"/>
<circle cx="187.8" cy="102.3" r=".51" fill="#000080"/>
<circle cx="187.8" cy="102.3" r=".51" fill="none" stroke="#000080" stroke-width=".21"/>
<circle cx="192.9" cy="102.3" r=".51" fill="#000080"/>
<circle cx="192.9" cy="102.3" r=".51" fill="none" stroke="#000080" stroke-width=".21"/>
<path d="M53 54.1v12.7" fill="none" stroke="#000080" stroke-width=".25"/>
<circle cx="53" cy="56.6" r=".51" fill="#000080"/>
<circle cx="53" cy="56.6" r=".51" fill="none" stroke="#000080" stroke-width=".21"/>
<path d="M45.4 28.7v7.6h7.6v7.6" fill="none" stroke="#000080" stroke-width=".25"/>
<circle cx="45.4" cy="28.7" r=".51" fill="#000080"/>
<circle cx="45.4" cy="28.7" r=".51" fill="none" stroke="#000080" stroke-width=".21"/>
<path d="M60.7 28.7h5v7.6h-7.6v7.6" fill="none" stroke="#000080" stroke-width=".25"/>
<circle cx="65.8" cy="28.7" r=".51" fill="#000080"/>
<circle cx="65.8" cy="28.7" r=".51" fill="none" stroke="#000080" stroke-width=".21"/>
<use href="#words"/>
</svg>
